VERSION 5.8 ;
BUSBITCHARS "[]" ;
DIVIDERCHAR "/" ;
UNITS
    DATABASE MICRONS 1000 ;
END UNITS

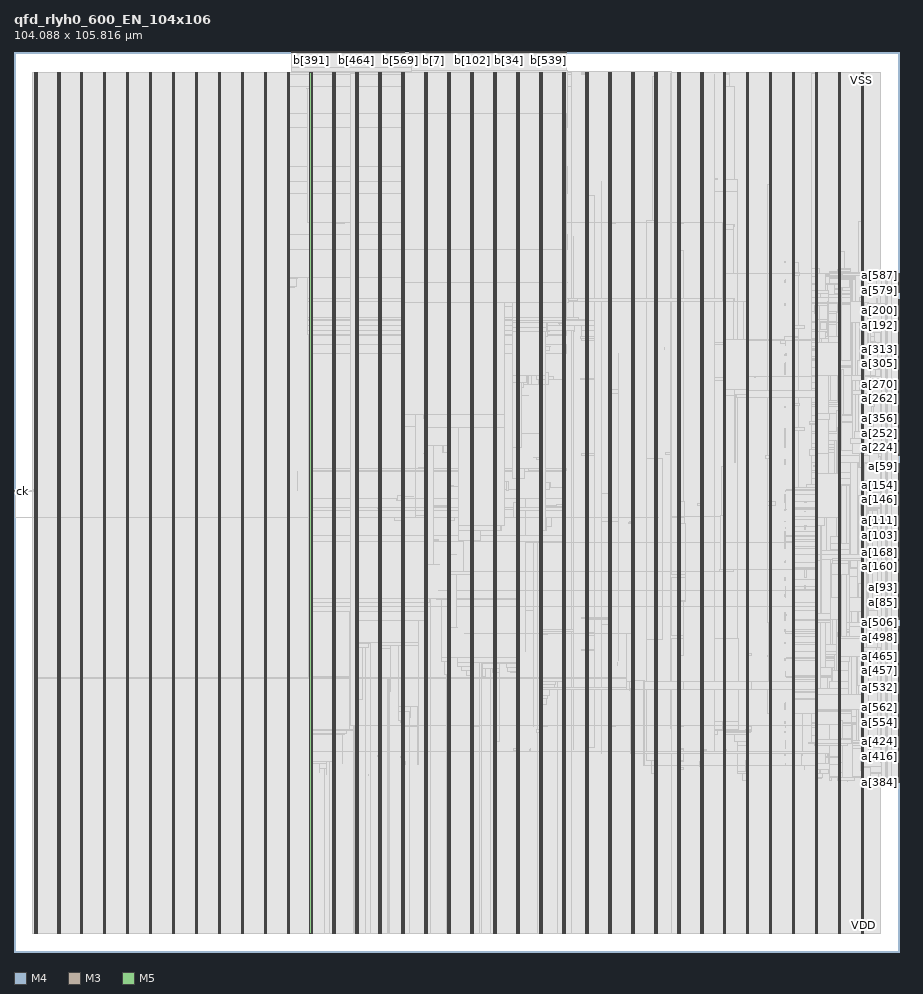
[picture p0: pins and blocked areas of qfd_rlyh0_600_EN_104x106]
MACRO qfd_rlyh0_600_EN_104x106
  FOREIGN qfd_rlyh0_600_EN_104x106 0 0 ;
  CLASS BLOCK ;
  SIZE 104.088 BY 105.816 ;
  PIN a[0]
    DIRECTION INPUT ;
    USE SIGNAL ;
    PORT
      LAYER M4 ;
        RECT  104.004 42.192 104.088 42.216 ;
    END
  END a[0]
  PIN a[100]
    DIRECTION INPUT ;
    USE SIGNAL ;
    PORT
      LAYER M4 ;
        RECT  104.004 48.72 104.088 48.744 ;
    END
  END a[100]
  PIN a[101]
    DIRECTION INPUT ;
    USE SIGNAL ;
    PORT
      LAYER M4 ;
        RECT  104.004 48.816 104.088 48.84 ;
    END
  END a[101]
  PIN a[102]
    DIRECTION INPUT ;
    USE SIGNAL ;
    PORT
      LAYER M4 ;
        RECT  104.004 48.912 104.088 48.936 ;
    END
  END a[102]
  PIN a[103]
    DIRECTION INPUT ;
    USE SIGNAL ;
    PORT
      LAYER M4 ;
        RECT  104.004 49.008 104.088 49.032 ;
    END
  END a[103]
  PIN a[104]
    DIRECTION INPUT ;
    USE SIGNAL ;
    PORT
      LAYER M4 ;
        RECT  104.004 49.104 104.088 49.128 ;
    END
  END a[104]
  PIN a[105]
    DIRECTION INPUT ;
    USE SIGNAL ;
    PORT
      LAYER M4 ;
        RECT  104.004 49.2 104.088 49.224 ;
    END
  END a[105]
  PIN a[106]
    DIRECTION INPUT ;
    USE SIGNAL ;
    PORT
      LAYER M4 ;
        RECT  104.004 49.296 104.088 49.32 ;
    END
  END a[106]
  PIN a[107]
    DIRECTION INPUT ;
    USE SIGNAL ;
    PORT
      LAYER M4 ;
        RECT  104.004 49.392 104.088 49.416 ;
    END
  END a[107]
  PIN a[108]
    DIRECTION INPUT ;
    USE SIGNAL ;
    PORT
      LAYER M4 ;
        RECT  104.004 49.488 104.088 49.512 ;
    END
  END a[108]
  PIN a[109]
    DIRECTION INPUT ;
    USE SIGNAL ;
    PORT
      LAYER M4 ;
        RECT  104.004 49.584 104.088 49.608 ;
    END
  END a[109]
  PIN a[10]
    DIRECTION INPUT ;
    USE SIGNAL ;
    PORT
      LAYER M4 ;
        RECT  104.004 43.152 104.088 43.176 ;
    END
  END a[10]
  PIN a[110]
    DIRECTION INPUT ;
    USE SIGNAL ;
    PORT
      LAYER M4 ;
        RECT  104.004 49.68 104.088 49.704 ;
    END
  END a[110]
  PIN a[111]
    DIRECTION INPUT ;
    USE SIGNAL ;
    PORT
      LAYER M4 ;
        RECT  104.004 49.776 104.088 49.8 ;
    END
  END a[111]
  PIN a[112]
    DIRECTION INPUT ;
    USE SIGNAL ;
    PORT
      LAYER M4 ;
        RECT  104.004 49.872 104.088 49.896 ;
    END
  END a[112]
  PIN a[113]
    DIRECTION INPUT ;
    USE SIGNAL ;
    PORT
      LAYER M4 ;
        RECT  104.004 49.968 104.088 49.992 ;
    END
  END a[113]
  PIN a[114]
    DIRECTION INPUT ;
    USE SIGNAL ;
    PORT
      LAYER M4 ;
        RECT  104.004 50.064 104.088 50.088 ;
    END
  END a[114]
  PIN a[115]
    DIRECTION INPUT ;
    USE SIGNAL ;
    PORT
      LAYER M4 ;
        RECT  104.004 50.16 104.088 50.184 ;
    END
  END a[115]
  PIN a[116]
    DIRECTION INPUT ;
    USE SIGNAL ;
    PORT
      LAYER M4 ;
        RECT  104.004 50.256 104.088 50.28 ;
    END
  END a[116]
  PIN a[117]
    DIRECTION INPUT ;
    USE SIGNAL ;
    PORT
      LAYER M4 ;
        RECT  104.004 50.352 104.088 50.376 ;
    END
  END a[117]
  PIN a[118]
    DIRECTION INPUT ;
    USE SIGNAL ;
    PORT
      LAYER M4 ;
        RECT  104.004 50.448 104.088 50.472 ;
    END
  END a[118]
  PIN a[119]
    DIRECTION INPUT ;
    USE SIGNAL ;
    PORT
      LAYER M4 ;
        RECT  104.004 50.544 104.088 50.568 ;
    END
  END a[119]
  PIN a[11]
    DIRECTION INPUT ;
    USE SIGNAL ;
    PORT
      LAYER M4 ;
        RECT  104.004 43.248 104.088 43.272 ;
    END
  END a[11]
  PIN a[120]
    DIRECTION INPUT ;
    USE SIGNAL ;
    PORT
      LAYER M4 ;
        RECT  104.004 50.64 104.088 50.664 ;
    END
  END a[120]
  PIN a[121]
    DIRECTION INPUT ;
    USE SIGNAL ;
    PORT
      LAYER M4 ;
        RECT  104.004 50.736 104.088 50.76 ;
    END
  END a[121]
  PIN a[122]
    DIRECTION INPUT ;
    USE SIGNAL ;
    PORT
      LAYER M4 ;
        RECT  104.004 50.832 104.088 50.856 ;
    END
  END a[122]
  PIN a[123]
    DIRECTION INPUT ;
    USE SIGNAL ;
    PORT
      LAYER M4 ;
        RECT  104.004 50.928 104.088 50.952 ;
    END
  END a[123]
  PIN a[124]
    DIRECTION INPUT ;
    USE SIGNAL ;
    PORT
      LAYER M4 ;
        RECT  104.004 51.024 104.088 51.048 ;
    END
  END a[124]
  PIN a[125]
    DIRECTION INPUT ;
    USE SIGNAL ;
    PORT
      LAYER M4 ;
        RECT  104.004 51.12 104.088 51.144 ;
    END
  END a[125]
  PIN a[126]
    DIRECTION INPUT ;
    USE SIGNAL ;
    PORT
      LAYER M4 ;
        RECT  104.004 51.216 104.088 51.24 ;
    END
  END a[126]
  PIN a[127]
    DIRECTION INPUT ;
    USE SIGNAL ;
    PORT
      LAYER M4 ;
        RECT  104.004 51.312 104.088 51.336 ;
    END
  END a[127]
  PIN a[128]
    DIRECTION INPUT ;
    USE SIGNAL ;
    PORT
      LAYER M4 ;
        RECT  104.004 51.408 104.088 51.432 ;
    END
  END a[128]
  PIN a[129]
    DIRECTION INPUT ;
    USE SIGNAL ;
    PORT
      LAYER M4 ;
        RECT  104.004 51.504 104.088 51.528 ;
    END
  END a[129]
  PIN a[12]
    DIRECTION INPUT ;
    USE SIGNAL ;
    PORT
      LAYER M4 ;
        RECT  104.004 43.344 104.088 43.368 ;
    END
  END a[12]
  PIN a[130]
    DIRECTION INPUT ;
    USE SIGNAL ;
    PORT
      LAYER M4 ;
        RECT  104.004 51.6 104.088 51.624 ;
    END
  END a[130]
  PIN a[131]
    DIRECTION INPUT ;
    USE SIGNAL ;
    PORT
      LAYER M4 ;
        RECT  104.004 51.696 104.088 51.72 ;
    END
  END a[131]
  PIN a[132]
    DIRECTION INPUT ;
    USE SIGNAL ;
    PORT
      LAYER M4 ;
        RECT  104.004 51.792 104.088 51.816 ;
    END
  END a[132]
  PIN a[133]
    DIRECTION INPUT ;
    USE SIGNAL ;
    PORT
      LAYER M4 ;
        RECT  104.004 51.888 104.088 51.912 ;
    END
  END a[133]
  PIN a[134]
    DIRECTION INPUT ;
    USE SIGNAL ;
    PORT
      LAYER M4 ;
        RECT  104.004 51.984 104.088 52.008 ;
    END
  END a[134]
  PIN a[135]
    DIRECTION INPUT ;
    USE SIGNAL ;
    PORT
      LAYER M4 ;
        RECT  104.004 52.08 104.088 52.104 ;
    END
  END a[135]
  PIN a[136]
    DIRECTION INPUT ;
    USE SIGNAL ;
    PORT
      LAYER M4 ;
        RECT  104.004 52.176 104.088 52.2 ;
    END
  END a[136]
  PIN a[137]
    DIRECTION INPUT ;
    USE SIGNAL ;
    PORT
      LAYER M4 ;
        RECT  104.004 52.272 104.088 52.296 ;
    END
  END a[137]
  PIN a[138]
    DIRECTION INPUT ;
    USE SIGNAL ;
    PORT
      LAYER M4 ;
        RECT  104.004 52.368 104.088 52.392 ;
    END
  END a[138]
  PIN a[139]
    DIRECTION INPUT ;
    USE SIGNAL ;
    PORT
      LAYER M4 ;
        RECT  104.004 52.464 104.088 52.488 ;
    END
  END a[139]
  PIN a[13]
    DIRECTION INPUT ;
    USE SIGNAL ;
    PORT
      LAYER M4 ;
        RECT  104.004 43.44 104.088 43.464 ;
    END
  END a[13]
  PIN a[140]
    DIRECTION INPUT ;
    USE SIGNAL ;
    PORT
      LAYER M4 ;
        RECT  104.004 52.56 104.088 52.584 ;
    END
  END a[140]
  PIN a[141]
    DIRECTION INPUT ;
    USE SIGNAL ;
    PORT
      LAYER M4 ;
        RECT  104.004 52.656 104.088 52.68 ;
    END
  END a[141]
  PIN a[142]
    DIRECTION INPUT ;
    USE SIGNAL ;
    PORT
      LAYER M4 ;
        RECT  104.004 52.752 104.088 52.776 ;
    END
  END a[142]
  PIN a[143]
    DIRECTION INPUT ;
    USE SIGNAL ;
    PORT
      LAYER M4 ;
        RECT  104.004 52.848 104.088 52.872 ;
    END
  END a[143]
  PIN a[144]
    DIRECTION INPUT ;
    USE SIGNAL ;
    PORT
      LAYER M4 ;
        RECT  104.004 52.944 104.088 52.968 ;
    END
  END a[144]
  PIN a[145]
    DIRECTION INPUT ;
    USE SIGNAL ;
    PORT
      LAYER M4 ;
        RECT  104.004 53.04 104.088 53.064 ;
    END
  END a[145]
  PIN a[146]
    DIRECTION INPUT ;
    USE SIGNAL ;
    PORT
      LAYER M4 ;
        RECT  104.004 53.136 104.088 53.16 ;
    END
  END a[146]
  PIN a[147]
    DIRECTION INPUT ;
    USE SIGNAL ;
    PORT
      LAYER M4 ;
        RECT  104.004 53.232 104.088 53.256 ;
    END
  END a[147]
  PIN a[148]
    DIRECTION INPUT ;
    USE SIGNAL ;
    PORT
      LAYER M4 ;
        RECT  104.004 53.328 104.088 53.352 ;
    END
  END a[148]
  PIN a[149]
    DIRECTION INPUT ;
    USE SIGNAL ;
    PORT
      LAYER M4 ;
        RECT  104.004 53.424 104.088 53.448 ;
    END
  END a[149]
  PIN a[14]
    DIRECTION INPUT ;
    USE SIGNAL ;
    PORT
      LAYER M4 ;
        RECT  104.004 43.536 104.088 43.56 ;
    END
  END a[14]
  PIN a[150]
    DIRECTION INPUT ;
    USE SIGNAL ;
    PORT
      LAYER M4 ;
        RECT  104.004 53.52 104.088 53.544 ;
    END
  END a[150]
  PIN a[151]
    DIRECTION INPUT ;
    USE SIGNAL ;
    PORT
      LAYER M4 ;
        RECT  104.004 53.616 104.088 53.64 ;
    END
  END a[151]
  PIN a[152]
    DIRECTION INPUT ;
    USE SIGNAL ;
    PORT
      LAYER M4 ;
        RECT  104.004 53.712 104.088 53.736 ;
    END
  END a[152]
  PIN a[153]
    DIRECTION INPUT ;
    USE SIGNAL ;
    PORT
      LAYER M4 ;
        RECT  104.004 53.808 104.088 53.832 ;
    END
  END a[153]
  PIN a[154]
    DIRECTION INPUT ;
    USE SIGNAL ;
    PORT
      LAYER M4 ;
        RECT  104.004 53.904 104.088 53.928 ;
    END
  END a[154]
  PIN a[155]
    DIRECTION INPUT ;
    USE SIGNAL ;
    PORT
      LAYER M4 ;
        RECT  104.004 54 104.088 54.024 ;
    END
  END a[155]
  PIN a[156]
    DIRECTION INPUT ;
    USE SIGNAL ;
    PORT
      LAYER M4 ;
        RECT  104.004 54.096 104.088 54.12 ;
    END
  END a[156]
  PIN a[157]
    DIRECTION INPUT ;
    USE SIGNAL ;
    PORT
      LAYER M4 ;
        RECT  104.004 54.192 104.088 54.216 ;
    END
  END a[157]
  PIN a[158]
    DIRECTION INPUT ;
    USE SIGNAL ;
    PORT
      LAYER M4 ;
        RECT  104.004 54.288 104.088 54.312 ;
    END
  END a[158]
  PIN a[159]
    DIRECTION INPUT ;
    USE SIGNAL ;
    PORT
      LAYER M4 ;
        RECT  104.004 54.384 104.088 54.408 ;
    END
  END a[159]
  PIN a[15]
    DIRECTION INPUT ;
    USE SIGNAL ;
    PORT
      LAYER M4 ;
        RECT  104.004 43.632 104.088 43.656 ;
    END
  END a[15]
  PIN a[160]
    DIRECTION INPUT ;
    USE SIGNAL ;
    PORT
      LAYER M4 ;
        RECT  104.004 45.264 104.088 45.288 ;
    END
  END a[160]
  PIN a[161]
    DIRECTION INPUT ;
    USE SIGNAL ;
    PORT
      LAYER M4 ;
        RECT  104.004 45.36 104.088 45.384 ;
    END
  END a[161]
  PIN a[162]
    DIRECTION INPUT ;
    USE SIGNAL ;
    PORT
      LAYER M4 ;
        RECT  104.004 45.456 104.088 45.48 ;
    END
  END a[162]
  PIN a[163]
    DIRECTION INPUT ;
    USE SIGNAL ;
    PORT
      LAYER M4 ;
        RECT  104.004 45.552 104.088 45.576 ;
    END
  END a[163]
  PIN a[164]
    DIRECTION INPUT ;
    USE SIGNAL ;
    PORT
      LAYER M4 ;
        RECT  104.004 45.648 104.088 45.672 ;
    END
  END a[164]
  PIN a[165]
    DIRECTION INPUT ;
    USE SIGNAL ;
    PORT
      LAYER M4 ;
        RECT  104.004 45.744 104.088 45.768 ;
    END
  END a[165]
  PIN a[166]
    DIRECTION INPUT ;
    USE SIGNAL ;
    PORT
      LAYER M4 ;
        RECT  104.004 45.84 104.088 45.864 ;
    END
  END a[166]
  PIN a[167]
    DIRECTION INPUT ;
    USE SIGNAL ;
    PORT
      LAYER M4 ;
        RECT  104.004 45.936 104.088 45.96 ;
    END
  END a[167]
  PIN a[168]
    DIRECTION INPUT ;
    USE SIGNAL ;
    PORT
      LAYER M4 ;
        RECT  104.004 46.032 104.088 46.056 ;
    END
  END a[168]
  PIN a[169]
    DIRECTION INPUT ;
    USE SIGNAL ;
    PORT
      LAYER M4 ;
        RECT  104.004 46.128 104.088 46.152 ;
    END
  END a[169]
  PIN a[16]
    DIRECTION INPUT ;
    USE SIGNAL ;
    PORT
      LAYER M4 ;
        RECT  104.004 43.728 104.088 43.752 ;
    END
  END a[16]
  PIN a[170]
    DIRECTION INPUT ;
    USE SIGNAL ;
    PORT
      LAYER M4 ;
        RECT  104.004 46.224 104.088 46.248 ;
    END
  END a[170]
  PIN a[171]
    DIRECTION INPUT ;
    USE SIGNAL ;
    PORT
      LAYER M4 ;
        RECT  104.004 46.32 104.088 46.344 ;
    END
  END a[171]
  PIN a[172]
    DIRECTION INPUT ;
    USE SIGNAL ;
    PORT
      LAYER M4 ;
        RECT  104.004 46.416 104.088 46.44 ;
    END
  END a[172]
  PIN a[173]
    DIRECTION INPUT ;
    USE SIGNAL ;
    PORT
      LAYER M4 ;
        RECT  104.004 46.512 104.088 46.536 ;
    END
  END a[173]
  PIN a[174]
    DIRECTION INPUT ;
    USE SIGNAL ;
    PORT
      LAYER M4 ;
        RECT  104.004 46.608 104.088 46.632 ;
    END
  END a[174]
  PIN a[175]
    DIRECTION INPUT ;
    USE SIGNAL ;
    PORT
      LAYER M4 ;
        RECT  104.004 46.704 104.088 46.728 ;
    END
  END a[175]
  PIN a[176]
    DIRECTION INPUT ;
    USE SIGNAL ;
    PORT
      LAYER M4 ;
        RECT  104.004 46.8 104.088 46.824 ;
    END
  END a[176]
  PIN a[177]
    DIRECTION INPUT ;
    USE SIGNAL ;
    PORT
      LAYER M4 ;
        RECT  104.004 46.896 104.088 46.92 ;
    END
  END a[177]
  PIN a[178]
    DIRECTION INPUT ;
    USE SIGNAL ;
    PORT
      LAYER M4 ;
        RECT  104.004 46.992 104.088 47.016 ;
    END
  END a[178]
  PIN a[179]
    DIRECTION INPUT ;
    USE SIGNAL ;
    PORT
      LAYER M4 ;
        RECT  104.004 47.088 104.088 47.112 ;
    END
  END a[179]
  PIN a[17]
    DIRECTION INPUT ;
    USE SIGNAL ;
    PORT
      LAYER M4 ;
        RECT  104.004 43.824 104.088 43.848 ;
    END
  END a[17]
  PIN a[180]
    DIRECTION INPUT ;
    USE SIGNAL ;
    PORT
      LAYER M4 ;
        RECT  104.004 47.184 104.088 47.208 ;
    END
  END a[180]
  PIN a[181]
    DIRECTION INPUT ;
    USE SIGNAL ;
    PORT
      LAYER M4 ;
        RECT  104.004 47.28 104.088 47.304 ;
    END
  END a[181]
  PIN a[182]
    DIRECTION INPUT ;
    USE SIGNAL ;
    PORT
      LAYER M4 ;
        RECT  104.004 47.376 104.088 47.4 ;
    END
  END a[182]
  PIN a[183]
    DIRECTION INPUT ;
    USE SIGNAL ;
    PORT
      LAYER M4 ;
        RECT  104.004 47.472 104.088 47.496 ;
    END
  END a[183]
  PIN a[184]
    DIRECTION INPUT ;
    USE SIGNAL ;
    PORT
      LAYER M4 ;
        RECT  104.004 47.568 104.088 47.592 ;
    END
  END a[184]
  PIN a[185]
    DIRECTION INPUT ;
    USE SIGNAL ;
    PORT
      LAYER M4 ;
        RECT  104.004 47.664 104.088 47.688 ;
    END
  END a[185]
  PIN a[186]
    DIRECTION INPUT ;
    USE SIGNAL ;
    PORT
      LAYER M4 ;
        RECT  104.004 47.76 104.088 47.784 ;
    END
  END a[186]
  PIN a[187]
    DIRECTION INPUT ;
    USE SIGNAL ;
    PORT
      LAYER M4 ;
        RECT  104.004 47.856 104.088 47.88 ;
    END
  END a[187]
  PIN a[188]
    DIRECTION INPUT ;
    USE SIGNAL ;
    PORT
      LAYER M4 ;
        RECT  104.004 47.952 104.088 47.976 ;
    END
  END a[188]
  PIN a[189]
    DIRECTION INPUT ;
    USE SIGNAL ;
    PORT
      LAYER M4 ;
        RECT  104.004 48.048 104.088 48.072 ;
    END
  END a[189]
  PIN a[18]
    DIRECTION INPUT ;
    USE SIGNAL ;
    PORT
      LAYER M4 ;
        RECT  104.004 43.92 104.088 43.944 ;
    END
  END a[18]
  PIN a[190]
    DIRECTION INPUT ;
    USE SIGNAL ;
    PORT
      LAYER M4 ;
        RECT  104.004 48.144 104.088 48.168 ;
    END
  END a[190]
  PIN a[191]
    DIRECTION INPUT ;
    USE SIGNAL ;
    PORT
      LAYER M4 ;
        RECT  104.004 48.24 104.088 48.264 ;
    END
  END a[191]
  PIN a[192]
    DIRECTION INPUT ;
    USE SIGNAL ;
    PORT
      LAYER M4 ;
        RECT  104.004 73.68 104.088 73.704 ;
    END
  END a[192]
  PIN a[193]
    DIRECTION INPUT ;
    USE SIGNAL ;
    PORT
      LAYER M4 ;
        RECT  104.004 73.776 104.088 73.8 ;
    END
  END a[193]
  PIN a[194]
    DIRECTION INPUT ;
    USE SIGNAL ;
    PORT
      LAYER M4 ;
        RECT  104.004 73.872 104.088 73.896 ;
    END
  END a[194]
  PIN a[195]
    DIRECTION INPUT ;
    USE SIGNAL ;
    PORT
      LAYER M4 ;
        RECT  104.004 73.968 104.088 73.992 ;
    END
  END a[195]
  PIN a[196]
    DIRECTION INPUT ;
    USE SIGNAL ;
    PORT
      LAYER M4 ;
        RECT  104.004 74.064 104.088 74.088 ;
    END
  END a[196]
  PIN a[197]
    DIRECTION INPUT ;
    USE SIGNAL ;
    PORT
      LAYER M4 ;
        RECT  104.004 74.16 104.088 74.184 ;
    END
  END a[197]
  PIN a[198]
    DIRECTION INPUT ;
    USE SIGNAL ;
    PORT
      LAYER M4 ;
        RECT  104.004 74.256 104.088 74.28 ;
    END
  END a[198]
  PIN a[199]
    DIRECTION INPUT ;
    USE SIGNAL ;
    PORT
      LAYER M4 ;
        RECT  104.004 74.352 104.088 74.376 ;
    END
  END a[199]
  PIN a[19]
    DIRECTION INPUT ;
    USE SIGNAL ;
    PORT
      LAYER M4 ;
        RECT  104.004 44.016 104.088 44.04 ;
    END
  END a[19]
  PIN a[1]
    DIRECTION INPUT ;
    USE SIGNAL ;
    PORT
      LAYER M4 ;
        RECT  104.004 42.288 104.088 42.312 ;
    END
  END a[1]
  PIN a[200]
    DIRECTION INPUT ;
    USE SIGNAL ;
    PORT
      LAYER M4 ;
        RECT  104.004 74.448 104.088 74.472 ;
    END
  END a[200]
  PIN a[201]
    DIRECTION INPUT ;
    USE SIGNAL ;
    PORT
      LAYER M4 ;
        RECT  104.004 74.544 104.088 74.568 ;
    END
  END a[201]
  PIN a[202]
    DIRECTION INPUT ;
    USE SIGNAL ;
    PORT
      LAYER M4 ;
        RECT  104.004 74.64 104.088 74.664 ;
    END
  END a[202]
  PIN a[203]
    DIRECTION INPUT ;
    USE SIGNAL ;
    PORT
      LAYER M4 ;
        RECT  104.004 74.736 104.088 74.76 ;
    END
  END a[203]
  PIN a[204]
    DIRECTION INPUT ;
    USE SIGNAL ;
    PORT
      LAYER M4 ;
        RECT  104.004 74.832 104.088 74.856 ;
    END
  END a[204]
  PIN a[205]
    DIRECTION INPUT ;
    USE SIGNAL ;
    PORT
      LAYER M4 ;
        RECT  104.004 74.928 104.088 74.952 ;
    END
  END a[205]
  PIN a[206]
    DIRECTION INPUT ;
    USE SIGNAL ;
    PORT
      LAYER M4 ;
        RECT  104.004 75.024 104.088 75.048 ;
    END
  END a[206]
  PIN a[207]
    DIRECTION INPUT ;
    USE SIGNAL ;
    PORT
      LAYER M4 ;
        RECT  104.004 75.12 104.088 75.144 ;
    END
  END a[207]
  PIN a[208]
    DIRECTION INPUT ;
    USE SIGNAL ;
    PORT
      LAYER M4 ;
        RECT  104.004 75.216 104.088 75.24 ;
    END
  END a[208]
  PIN a[209]
    DIRECTION INPUT ;
    USE SIGNAL ;
    PORT
      LAYER M4 ;
        RECT  104.004 75.312 104.088 75.336 ;
    END
  END a[209]
  PIN a[20]
    DIRECTION INPUT ;
    USE SIGNAL ;
    PORT
      LAYER M4 ;
        RECT  104.004 44.112 104.088 44.136 ;
    END
  END a[20]
  PIN a[210]
    DIRECTION INPUT ;
    USE SIGNAL ;
    PORT
      LAYER M4 ;
        RECT  104.004 75.408 104.088 75.432 ;
    END
  END a[210]
  PIN a[211]
    DIRECTION INPUT ;
    USE SIGNAL ;
    PORT
      LAYER M4 ;
        RECT  104.004 75.504 104.088 75.528 ;
    END
  END a[211]
  PIN a[212]
    DIRECTION INPUT ;
    USE SIGNAL ;
    PORT
      LAYER M4 ;
        RECT  104.004 75.6 104.088 75.624 ;
    END
  END a[212]
  PIN a[213]
    DIRECTION INPUT ;
    USE SIGNAL ;
    PORT
      LAYER M4 ;
        RECT  104.004 75.696 104.088 75.72 ;
    END
  END a[213]
  PIN a[214]
    DIRECTION INPUT ;
    USE SIGNAL ;
    PORT
      LAYER M4 ;
        RECT  104.004 75.792 104.088 75.816 ;
    END
  END a[214]
  PIN a[215]
    DIRECTION INPUT ;
    USE SIGNAL ;
    PORT
      LAYER M4 ;
        RECT  104.004 75.888 104.088 75.912 ;
    END
  END a[215]
  PIN a[216]
    DIRECTION INPUT ;
    USE SIGNAL ;
    PORT
      LAYER M4 ;
        RECT  104.004 75.984 104.088 76.008 ;
    END
  END a[216]
  PIN a[217]
    DIRECTION INPUT ;
    USE SIGNAL ;
    PORT
      LAYER M4 ;
        RECT  104.004 76.08 104.088 76.104 ;
    END
  END a[217]
  PIN a[218]
    DIRECTION INPUT ;
    USE SIGNAL ;
    PORT
      LAYER M4 ;
        RECT  104.004 76.176 104.088 76.2 ;
    END
  END a[218]
  PIN a[219]
    DIRECTION INPUT ;
    USE SIGNAL ;
    PORT
      LAYER M4 ;
        RECT  104.004 76.272 104.088 76.296 ;
    END
  END a[219]
  PIN a[21]
    DIRECTION INPUT ;
    USE SIGNAL ;
    PORT
      LAYER M4 ;
        RECT  104.004 44.208 104.088 44.232 ;
    END
  END a[21]
  PIN a[220]
    DIRECTION INPUT ;
    USE SIGNAL ;
    PORT
      LAYER M4 ;
        RECT  104.004 76.368 104.088 76.392 ;
    END
  END a[220]
  PIN a[221]
    DIRECTION INPUT ;
    USE SIGNAL ;
    PORT
      LAYER M4 ;
        RECT  104.004 76.464 104.088 76.488 ;
    END
  END a[221]
  PIN a[222]
    DIRECTION INPUT ;
    USE SIGNAL ;
    PORT
      LAYER M4 ;
        RECT  104.004 76.56 104.088 76.584 ;
    END
  END a[222]
  PIN a[223]
    DIRECTION INPUT ;
    USE SIGNAL ;
    PORT
      LAYER M4 ;
        RECT  104.004 76.656 104.088 76.68 ;
    END
  END a[223]
  PIN a[224]
    DIRECTION INPUT ;
    USE SIGNAL ;
    PORT
      LAYER M4 ;
        RECT  104.004 58.32 104.088 58.344 ;
    END
  END a[224]
  PIN a[225]
    DIRECTION INPUT ;
    USE SIGNAL ;
    PORT
      LAYER M4 ;
        RECT  104.004 58.416 104.088 58.44 ;
    END
  END a[225]
  PIN a[226]
    DIRECTION INPUT ;
    USE SIGNAL ;
    PORT
      LAYER M4 ;
        RECT  104.004 58.512 104.088 58.536 ;
    END
  END a[226]
  PIN a[227]
    DIRECTION INPUT ;
    USE SIGNAL ;
    PORT
      LAYER M4 ;
        RECT  104.004 58.608 104.088 58.632 ;
    END
  END a[227]
  PIN a[228]
    DIRECTION INPUT ;
    USE SIGNAL ;
    PORT
      LAYER M4 ;
        RECT  104.004 58.704 104.088 58.728 ;
    END
  END a[228]
  PIN a[229]
    DIRECTION INPUT ;
    USE SIGNAL ;
    PORT
      LAYER M4 ;
        RECT  104.004 58.8 104.088 58.824 ;
    END
  END a[229]
  PIN a[22]
    DIRECTION INPUT ;
    USE SIGNAL ;
    PORT
      LAYER M4 ;
        RECT  104.004 44.304 104.088 44.328 ;
    END
  END a[22]
  PIN a[230]
    DIRECTION INPUT ;
    USE SIGNAL ;
    PORT
      LAYER M4 ;
        RECT  104.004 58.896 104.088 58.92 ;
    END
  END a[230]
  PIN a[231]
    DIRECTION INPUT ;
    USE SIGNAL ;
    PORT
      LAYER M4 ;
        RECT  104.004 58.992 104.088 59.016 ;
    END
  END a[231]
  PIN a[232]
    DIRECTION INPUT ;
    USE SIGNAL ;
    PORT
      LAYER M4 ;
        RECT  104.004 59.088 104.088 59.112 ;
    END
  END a[232]
  PIN a[233]
    DIRECTION INPUT ;
    USE SIGNAL ;
    PORT
      LAYER M4 ;
        RECT  104.004 59.184 104.088 59.208 ;
    END
  END a[233]
  PIN a[234]
    DIRECTION INPUT ;
    USE SIGNAL ;
    PORT
      LAYER M4 ;
        RECT  104.004 59.28 104.088 59.304 ;
    END
  END a[234]
  PIN a[235]
    DIRECTION INPUT ;
    USE SIGNAL ;
    PORT
      LAYER M4 ;
        RECT  104.004 59.376 104.088 59.4 ;
    END
  END a[235]
  PIN a[236]
    DIRECTION INPUT ;
    USE SIGNAL ;
    PORT
      LAYER M4 ;
        RECT  104.004 59.472 104.088 59.496 ;
    END
  END a[236]
  PIN a[237]
    DIRECTION INPUT ;
    USE SIGNAL ;
    PORT
      LAYER M4 ;
        RECT  104.004 59.568 104.088 59.592 ;
    END
  END a[237]
  PIN a[238]
    DIRECTION INPUT ;
    USE SIGNAL ;
    PORT
      LAYER M4 ;
        RECT  104.004 59.664 104.088 59.688 ;
    END
  END a[238]
  PIN a[239]
    DIRECTION INPUT ;
    USE SIGNAL ;
    PORT
      LAYER M4 ;
        RECT  104.004 59.76 104.088 59.784 ;
    END
  END a[239]
  PIN a[23]
    DIRECTION INPUT ;
    USE SIGNAL ;
    PORT
      LAYER M4 ;
        RECT  104.004 44.4 104.088 44.424 ;
    END
  END a[23]
  PIN a[240]
    DIRECTION INPUT ;
    USE SIGNAL ;
    PORT
      LAYER M4 ;
        RECT  104.004 59.856 104.088 59.88 ;
    END
  END a[240]
  PIN a[241]
    DIRECTION INPUT ;
    USE SIGNAL ;
    PORT
      LAYER M4 ;
        RECT  104.004 59.952 104.088 59.976 ;
    END
  END a[241]
  PIN a[242]
    DIRECTION INPUT ;
    USE SIGNAL ;
    PORT
      LAYER M4 ;
        RECT  104.004 60.048 104.088 60.072 ;
    END
  END a[242]
  PIN a[243]
    DIRECTION INPUT ;
    USE SIGNAL ;
    PORT
      LAYER M4 ;
        RECT  104.004 60.144 104.088 60.168 ;
    END
  END a[243]
  PIN a[244]
    DIRECTION INPUT ;
    USE SIGNAL ;
    PORT
      LAYER M4 ;
        RECT  104.004 60.24 104.088 60.264 ;
    END
  END a[244]
  PIN a[245]
    DIRECTION INPUT ;
    USE SIGNAL ;
    PORT
      LAYER M4 ;
        RECT  104.004 60.336 104.088 60.36 ;
    END
  END a[245]
  PIN a[246]
    DIRECTION INPUT ;
    USE SIGNAL ;
    PORT
      LAYER M4 ;
        RECT  104.004 60.432 104.088 60.456 ;
    END
  END a[246]
  PIN a[247]
    DIRECTION INPUT ;
    USE SIGNAL ;
    PORT
      LAYER M4 ;
        RECT  104.004 60.528 104.088 60.552 ;
    END
  END a[247]
  PIN a[248]
    DIRECTION INPUT ;
    USE SIGNAL ;
    PORT
      LAYER M4 ;
        RECT  104.004 60.624 104.088 60.648 ;
    END
  END a[248]
  PIN a[249]
    DIRECTION INPUT ;
    USE SIGNAL ;
    PORT
      LAYER M4 ;
        RECT  104.004 60.72 104.088 60.744 ;
    END
  END a[249]
  PIN a[24]
    DIRECTION INPUT ;
    USE SIGNAL ;
    PORT
      LAYER M4 ;
        RECT  104.004 44.496 104.088 44.52 ;
    END
  END a[24]
  PIN a[250]
    DIRECTION INPUT ;
    USE SIGNAL ;
    PORT
      LAYER M4 ;
        RECT  104.004 60.816 104.088 60.84 ;
    END
  END a[250]
  PIN a[251]
    DIRECTION INPUT ;
    USE SIGNAL ;
    PORT
      LAYER M4 ;
        RECT  104.004 60.912 104.088 60.936 ;
    END
  END a[251]
  PIN a[252]
    DIRECTION INPUT ;
    USE SIGNAL ;
    PORT
      LAYER M4 ;
        RECT  104.004 61.008 104.088 61.032 ;
    END
  END a[252]
  PIN a[253]
    DIRECTION INPUT ;
    USE SIGNAL ;
    PORT
      LAYER M4 ;
        RECT  104.004 61.104 104.088 61.128 ;
    END
  END a[253]
  PIN a[254]
    DIRECTION INPUT ;
    USE SIGNAL ;
    PORT
      LAYER M4 ;
        RECT  104.004 61.2 104.088 61.224 ;
    END
  END a[254]
  PIN a[255]
    DIRECTION INPUT ;
    USE SIGNAL ;
    PORT
      LAYER M4 ;
        RECT  104.004 61.296 104.088 61.32 ;
    END
  END a[255]
  PIN a[256]
    DIRECTION INPUT ;
    USE SIGNAL ;
    PORT
      LAYER M4 ;
        RECT  104.004 64.464 104.088 64.488 ;
    END
  END a[256]
  PIN a[257]
    DIRECTION INPUT ;
    USE SIGNAL ;
    PORT
      LAYER M4 ;
        RECT  104.004 64.56 104.088 64.584 ;
    END
  END a[257]
  PIN a[258]
    DIRECTION INPUT ;
    USE SIGNAL ;
    PORT
      LAYER M4 ;
        RECT  104.004 64.656 104.088 64.68 ;
    END
  END a[258]
  PIN a[259]
    DIRECTION INPUT ;
    USE SIGNAL ;
    PORT
      LAYER M4 ;
        RECT  104.004 64.752 104.088 64.776 ;
    END
  END a[259]
  PIN a[25]
    DIRECTION INPUT ;
    USE SIGNAL ;
    PORT
      LAYER M4 ;
        RECT  104.004 44.592 104.088 44.616 ;
    END
  END a[25]
  PIN a[260]
    DIRECTION INPUT ;
    USE SIGNAL ;
    PORT
      LAYER M4 ;
        RECT  104.004 64.848 104.088 64.872 ;
    END
  END a[260]
  PIN a[261]
    DIRECTION INPUT ;
    USE SIGNAL ;
    PORT
      LAYER M4 ;
        RECT  104.004 64.944 104.088 64.968 ;
    END
  END a[261]
  PIN a[262]
    DIRECTION INPUT ;
    USE SIGNAL ;
    PORT
      LAYER M4 ;
        RECT  104.004 65.04 104.088 65.064 ;
    END
  END a[262]
  PIN a[263]
    DIRECTION INPUT ;
    USE SIGNAL ;
    PORT
      LAYER M4 ;
        RECT  104.004 65.136 104.088 65.16 ;
    END
  END a[263]
  PIN a[264]
    DIRECTION INPUT ;
    USE SIGNAL ;
    PORT
      LAYER M4 ;
        RECT  104.004 65.232 104.088 65.256 ;
    END
  END a[264]
  PIN a[265]
    DIRECTION INPUT ;
    USE SIGNAL ;
    PORT
      LAYER M4 ;
        RECT  104.004 65.328 104.088 65.352 ;
    END
  END a[265]
  PIN a[266]
    DIRECTION INPUT ;
    USE SIGNAL ;
    PORT
      LAYER M4 ;
        RECT  104.004 65.424 104.088 65.448 ;
    END
  END a[266]
  PIN a[267]
    DIRECTION INPUT ;
    USE SIGNAL ;
    PORT
      LAYER M4 ;
        RECT  104.004 65.52 104.088 65.544 ;
    END
  END a[267]
  PIN a[268]
    DIRECTION INPUT ;
    USE SIGNAL ;
    PORT
      LAYER M4 ;
        RECT  104.004 65.616 104.088 65.64 ;
    END
  END a[268]
  PIN a[269]
    DIRECTION INPUT ;
    USE SIGNAL ;
    PORT
      LAYER M4 ;
        RECT  104.004 65.712 104.088 65.736 ;
    END
  END a[269]
  PIN a[26]
    DIRECTION INPUT ;
    USE SIGNAL ;
    PORT
      LAYER M4 ;
        RECT  104.004 44.688 104.088 44.712 ;
    END
  END a[26]
  PIN a[270]
    DIRECTION INPUT ;
    USE SIGNAL ;
    PORT
      LAYER M4 ;
        RECT  104.004 65.808 104.088 65.832 ;
    END
  END a[270]
  PIN a[271]
    DIRECTION INPUT ;
    USE SIGNAL ;
    PORT
      LAYER M4 ;
        RECT  104.004 65.904 104.088 65.928 ;
    END
  END a[271]
  PIN a[272]
    DIRECTION INPUT ;
    USE SIGNAL ;
    PORT
      LAYER M4 ;
        RECT  104.004 66 104.088 66.024 ;
    END
  END a[272]
  PIN a[273]
    DIRECTION INPUT ;
    USE SIGNAL ;
    PORT
      LAYER M4 ;
        RECT  104.004 66.096 104.088 66.12 ;
    END
  END a[273]
  PIN a[274]
    DIRECTION INPUT ;
    USE SIGNAL ;
    PORT
      LAYER M4 ;
        RECT  104.004 66.192 104.088 66.216 ;
    END
  END a[274]
  PIN a[275]
    DIRECTION INPUT ;
    USE SIGNAL ;
    PORT
      LAYER M4 ;
        RECT  104.004 66.288 104.088 66.312 ;
    END
  END a[275]
  PIN a[276]
    DIRECTION INPUT ;
    USE SIGNAL ;
    PORT
      LAYER M4 ;
        RECT  104.004 66.384 104.088 66.408 ;
    END
  END a[276]
  PIN a[277]
    DIRECTION INPUT ;
    USE SIGNAL ;
    PORT
      LAYER M4 ;
        RECT  104.004 66.48 104.088 66.504 ;
    END
  END a[277]
  PIN a[278]
    DIRECTION INPUT ;
    USE SIGNAL ;
    PORT
      LAYER M4 ;
        RECT  104.004 66.576 104.088 66.6 ;
    END
  END a[278]
  PIN a[279]
    DIRECTION INPUT ;
    USE SIGNAL ;
    PORT
      LAYER M4 ;
        RECT  104.004 66.672 104.088 66.696 ;
    END
  END a[279]
  PIN a[27]
    DIRECTION INPUT ;
    USE SIGNAL ;
    PORT
      LAYER M4 ;
        RECT  104.004 44.784 104.088 44.808 ;
    END
  END a[27]
  PIN a[280]
    DIRECTION INPUT ;
    USE SIGNAL ;
    PORT
      LAYER M4 ;
        RECT  104.004 66.768 104.088 66.792 ;
    END
  END a[280]
  PIN a[281]
    DIRECTION INPUT ;
    USE SIGNAL ;
    PORT
      LAYER M4 ;
        RECT  104.004 66.864 104.088 66.888 ;
    END
  END a[281]
  PIN a[282]
    DIRECTION INPUT ;
    USE SIGNAL ;
    PORT
      LAYER M4 ;
        RECT  104.004 66.96 104.088 66.984 ;
    END
  END a[282]
  PIN a[283]
    DIRECTION INPUT ;
    USE SIGNAL ;
    PORT
      LAYER M4 ;
        RECT  104.004 67.056 104.088 67.08 ;
    END
  END a[283]
  PIN a[284]
    DIRECTION INPUT ;
    USE SIGNAL ;
    PORT
      LAYER M4 ;
        RECT  104.004 67.152 104.088 67.176 ;
    END
  END a[284]
  PIN a[285]
    DIRECTION INPUT ;
    USE SIGNAL ;
    PORT
      LAYER M4 ;
        RECT  104.004 67.248 104.088 67.272 ;
    END
  END a[285]
  PIN a[286]
    DIRECTION INPUT ;
    USE SIGNAL ;
    PORT
      LAYER M4 ;
        RECT  104.004 67.344 104.088 67.368 ;
    END
  END a[286]
  PIN a[287]
    DIRECTION INPUT ;
    USE SIGNAL ;
    PORT
      LAYER M4 ;
        RECT  104.004 67.44 104.088 67.464 ;
    END
  END a[287]
  PIN a[288]
    DIRECTION INPUT ;
    USE SIGNAL ;
    PORT
      LAYER M4 ;
        RECT  104.004 67.536 104.088 67.56 ;
    END
  END a[288]
  PIN a[289]
    DIRECTION INPUT ;
    USE SIGNAL ;
    PORT
      LAYER M4 ;
        RECT  104.004 67.632 104.088 67.656 ;
    END
  END a[289]
  PIN a[28]
    DIRECTION INPUT ;
    USE SIGNAL ;
    PORT
      LAYER M4 ;
        RECT  104.004 44.88 104.088 44.904 ;
    END
  END a[28]
  PIN a[290]
    DIRECTION INPUT ;
    USE SIGNAL ;
    PORT
      LAYER M4 ;
        RECT  104.004 67.728 104.088 67.752 ;
    END
  END a[290]
  PIN a[291]
    DIRECTION INPUT ;
    USE SIGNAL ;
    PORT
      LAYER M4 ;
        RECT  104.004 67.824 104.088 67.848 ;
    END
  END a[291]
  PIN a[292]
    DIRECTION INPUT ;
    USE SIGNAL ;
    PORT
      LAYER M4 ;
        RECT  104.004 67.92 104.088 67.944 ;
    END
  END a[292]
  PIN a[293]
    DIRECTION INPUT ;
    USE SIGNAL ;
    PORT
      LAYER M4 ;
        RECT  104.004 68.016 104.088 68.04 ;
    END
  END a[293]
  PIN a[294]
    DIRECTION INPUT ;
    USE SIGNAL ;
    PORT
      LAYER M4 ;
        RECT  104.004 68.112 104.088 68.136 ;
    END
  END a[294]
  PIN a[295]
    DIRECTION INPUT ;
    USE SIGNAL ;
    PORT
      LAYER M4 ;
        RECT  104.004 68.208 104.088 68.232 ;
    END
  END a[295]
  PIN a[296]
    DIRECTION INPUT ;
    USE SIGNAL ;
    PORT
      LAYER M4 ;
        RECT  104.004 68.304 104.088 68.328 ;
    END
  END a[296]
  PIN a[297]
    DIRECTION INPUT ;
    USE SIGNAL ;
    PORT
      LAYER M4 ;
        RECT  104.004 68.4 104.088 68.424 ;
    END
  END a[297]
  PIN a[298]
    DIRECTION INPUT ;
    USE SIGNAL ;
    PORT
      LAYER M4 ;
        RECT  104.004 68.496 104.088 68.52 ;
    END
  END a[298]
  PIN a[299]
    DIRECTION INPUT ;
    USE SIGNAL ;
    PORT
      LAYER M4 ;
        RECT  104.004 68.592 104.088 68.616 ;
    END
  END a[299]
  PIN a[29]
    DIRECTION INPUT ;
    USE SIGNAL ;
    PORT
      LAYER M4 ;
        RECT  104.004 44.976 104.088 45 ;
    END
  END a[29]
  PIN a[2]
    DIRECTION INPUT ;
    USE SIGNAL ;
    PORT
      LAYER M4 ;
        RECT  104.004 42.384 104.088 42.408 ;
    END
  END a[2]
  PIN a[300]
    DIRECTION INPUT ;
    USE SIGNAL ;
    PORT
      LAYER M4 ;
        RECT  104.004 68.688 104.088 68.712 ;
    END
  END a[300]
  PIN a[301]
    DIRECTION INPUT ;
    USE SIGNAL ;
    PORT
      LAYER M4 ;
        RECT  104.004 68.784 104.088 68.808 ;
    END
  END a[301]
  PIN a[302]
    DIRECTION INPUT ;
    USE SIGNAL ;
    PORT
      LAYER M4 ;
        RECT  104.004 68.88 104.088 68.904 ;
    END
  END a[302]
  PIN a[303]
    DIRECTION INPUT ;
    USE SIGNAL ;
    PORT
      LAYER M4 ;
        RECT  104.004 68.976 104.088 69 ;
    END
  END a[303]
  PIN a[304]
    DIRECTION INPUT ;
    USE SIGNAL ;
    PORT
      LAYER M4 ;
        RECT  104.004 69.072 104.088 69.096 ;
    END
  END a[304]
  PIN a[305]
    DIRECTION INPUT ;
    USE SIGNAL ;
    PORT
      LAYER M4 ;
        RECT  104.004 69.168 104.088 69.192 ;
    END
  END a[305]
  PIN a[306]
    DIRECTION INPUT ;
    USE SIGNAL ;
    PORT
      LAYER M4 ;
        RECT  104.004 69.264 104.088 69.288 ;
    END
  END a[306]
  PIN a[307]
    DIRECTION INPUT ;
    USE SIGNAL ;
    PORT
      LAYER M4 ;
        RECT  104.004 69.36 104.088 69.384 ;
    END
  END a[307]
  PIN a[308]
    DIRECTION INPUT ;
    USE SIGNAL ;
    PORT
      LAYER M4 ;
        RECT  104.004 69.456 104.088 69.48 ;
    END
  END a[308]
  PIN a[309]
    DIRECTION INPUT ;
    USE SIGNAL ;
    PORT
      LAYER M4 ;
        RECT  104.004 69.552 104.088 69.576 ;
    END
  END a[309]
  PIN a[30]
    DIRECTION INPUT ;
    USE SIGNAL ;
    PORT
      LAYER M4 ;
        RECT  104.004 45.072 104.088 45.096 ;
    END
  END a[30]
  PIN a[310]
    DIRECTION INPUT ;
    USE SIGNAL ;
    PORT
      LAYER M4 ;
        RECT  104.004 69.648 104.088 69.672 ;
    END
  END a[310]
  PIN a[311]
    DIRECTION INPUT ;
    USE SIGNAL ;
    PORT
      LAYER M4 ;
        RECT  104.004 69.744 104.088 69.768 ;
    END
  END a[311]
  PIN a[312]
    DIRECTION INPUT ;
    USE SIGNAL ;
    PORT
      LAYER M4 ;
        RECT  104.004 69.84 104.088 69.864 ;
    END
  END a[312]
  PIN a[313]
    DIRECTION INPUT ;
    USE SIGNAL ;
    PORT
      LAYER M4 ;
        RECT  104.004 69.936 104.088 69.96 ;
    END
  END a[313]
  PIN a[314]
    DIRECTION INPUT ;
    USE SIGNAL ;
    PORT
      LAYER M4 ;
        RECT  104.004 70.032 104.088 70.056 ;
    END
  END a[314]
  PIN a[315]
    DIRECTION INPUT ;
    USE SIGNAL ;
    PORT
      LAYER M4 ;
        RECT  104.004 70.128 104.088 70.152 ;
    END
  END a[315]
  PIN a[316]
    DIRECTION INPUT ;
    USE SIGNAL ;
    PORT
      LAYER M4 ;
        RECT  104.004 70.224 104.088 70.248 ;
    END
  END a[316]
  PIN a[317]
    DIRECTION INPUT ;
    USE SIGNAL ;
    PORT
      LAYER M4 ;
        RECT  104.004 70.32 104.088 70.344 ;
    END
  END a[317]
  PIN a[318]
    DIRECTION INPUT ;
    USE SIGNAL ;
    PORT
      LAYER M4 ;
        RECT  104.004 70.416 104.088 70.44 ;
    END
  END a[318]
  PIN a[319]
    DIRECTION INPUT ;
    USE SIGNAL ;
    PORT
      LAYER M4 ;
        RECT  104.004 70.512 104.088 70.536 ;
    END
  END a[319]
  PIN a[31]
    DIRECTION INPUT ;
    USE SIGNAL ;
    PORT
      LAYER M4 ;
        RECT  104.004 45.168 104.088 45.192 ;
    END
  END a[31]
  PIN a[320]
    DIRECTION INPUT ;
    USE SIGNAL ;
    PORT
      LAYER M4 ;
        RECT  104.004 70.608 104.088 70.632 ;
    END
  END a[320]
  PIN a[321]
    DIRECTION INPUT ;
    USE SIGNAL ;
    PORT
      LAYER M4 ;
        RECT  104.004 70.704 104.088 70.728 ;
    END
  END a[321]
  PIN a[322]
    DIRECTION INPUT ;
    USE SIGNAL ;
    PORT
      LAYER M4 ;
        RECT  104.004 70.8 104.088 70.824 ;
    END
  END a[322]
  PIN a[323]
    DIRECTION INPUT ;
    USE SIGNAL ;
    PORT
      LAYER M4 ;
        RECT  104.004 70.896 104.088 70.92 ;
    END
  END a[323]
  PIN a[324]
    DIRECTION INPUT ;
    USE SIGNAL ;
    PORT
      LAYER M4 ;
        RECT  104.004 70.992 104.088 71.016 ;
    END
  END a[324]
  PIN a[325]
    DIRECTION INPUT ;
    USE SIGNAL ;
    PORT
      LAYER M4 ;
        RECT  104.004 71.088 104.088 71.112 ;
    END
  END a[325]
  PIN a[326]
    DIRECTION INPUT ;
    USE SIGNAL ;
    PORT
      LAYER M4 ;
        RECT  104.004 71.184 104.088 71.208 ;
    END
  END a[326]
  PIN a[327]
    DIRECTION INPUT ;
    USE SIGNAL ;
    PORT
      LAYER M4 ;
        RECT  104.004 71.28 104.088 71.304 ;
    END
  END a[327]
  PIN a[328]
    DIRECTION INPUT ;
    USE SIGNAL ;
    PORT
      LAYER M4 ;
        RECT  104.004 71.376 104.088 71.4 ;
    END
  END a[328]
  PIN a[329]
    DIRECTION INPUT ;
    USE SIGNAL ;
    PORT
      LAYER M4 ;
        RECT  104.004 71.472 104.088 71.496 ;
    END
  END a[329]
  PIN a[32]
    DIRECTION INPUT ;
    USE SIGNAL ;
    PORT
      LAYER M4 ;
        RECT  104.004 54.48 104.088 54.504 ;
    END
  END a[32]
  PIN a[330]
    DIRECTION INPUT ;
    USE SIGNAL ;
    PORT
      LAYER M4 ;
        RECT  104.004 71.568 104.088 71.592 ;
    END
  END a[330]
  PIN a[331]
    DIRECTION INPUT ;
    USE SIGNAL ;
    PORT
      LAYER M4 ;
        RECT  104.004 71.664 104.088 71.688 ;
    END
  END a[331]
  PIN a[332]
    DIRECTION INPUT ;
    USE SIGNAL ;
    PORT
      LAYER M4 ;
        RECT  104.004 71.76 104.088 71.784 ;
    END
  END a[332]
  PIN a[333]
    DIRECTION INPUT ;
    USE SIGNAL ;
    PORT
      LAYER M4 ;
        RECT  104.004 71.856 104.088 71.88 ;
    END
  END a[333]
  PIN a[334]
    DIRECTION INPUT ;
    USE SIGNAL ;
    PORT
      LAYER M4 ;
        RECT  104.004 71.952 104.088 71.976 ;
    END
  END a[334]
  PIN a[335]
    DIRECTION INPUT ;
    USE SIGNAL ;
    PORT
      LAYER M4 ;
        RECT  104.004 72.048 104.088 72.072 ;
    END
  END a[335]
  PIN a[336]
    DIRECTION INPUT ;
    USE SIGNAL ;
    PORT
      LAYER M4 ;
        RECT  104.004 72.144 104.088 72.168 ;
    END
  END a[336]
  PIN a[337]
    DIRECTION INPUT ;
    USE SIGNAL ;
    PORT
      LAYER M4 ;
        RECT  104.004 72.24 104.088 72.264 ;
    END
  END a[337]
  PIN a[338]
    DIRECTION INPUT ;
    USE SIGNAL ;
    PORT
      LAYER M4 ;
        RECT  104.004 72.336 104.088 72.36 ;
    END
  END a[338]
  PIN a[339]
    DIRECTION INPUT ;
    USE SIGNAL ;
    PORT
      LAYER M4 ;
        RECT  104.004 72.432 104.088 72.456 ;
    END
  END a[339]
  PIN a[33]
    DIRECTION INPUT ;
    USE SIGNAL ;
    PORT
      LAYER M4 ;
        RECT  104.004 54.576 104.088 54.6 ;
    END
  END a[33]
  PIN a[340]
    DIRECTION INPUT ;
    USE SIGNAL ;
    PORT
      LAYER M4 ;
        RECT  104.004 72.528 104.088 72.552 ;
    END
  END a[340]
  PIN a[341]
    DIRECTION INPUT ;
    USE SIGNAL ;
    PORT
      LAYER M4 ;
        RECT  104.004 72.624 104.088 72.648 ;
    END
  END a[341]
  PIN a[342]
    DIRECTION INPUT ;
    USE SIGNAL ;
    PORT
      LAYER M4 ;
        RECT  104.004 72.72 104.088 72.744 ;
    END
  END a[342]
  PIN a[343]
    DIRECTION INPUT ;
    USE SIGNAL ;
    PORT
      LAYER M4 ;
        RECT  104.004 72.816 104.088 72.84 ;
    END
  END a[343]
  PIN a[344]
    DIRECTION INPUT ;
    USE SIGNAL ;
    PORT
      LAYER M4 ;
        RECT  104.004 72.912 104.088 72.936 ;
    END
  END a[344]
  PIN a[345]
    DIRECTION INPUT ;
    USE SIGNAL ;
    PORT
      LAYER M4 ;
        RECT  104.004 73.008 104.088 73.032 ;
    END
  END a[345]
  PIN a[346]
    DIRECTION INPUT ;
    USE SIGNAL ;
    PORT
      LAYER M4 ;
        RECT  104.004 73.104 104.088 73.128 ;
    END
  END a[346]
  PIN a[347]
    DIRECTION INPUT ;
    USE SIGNAL ;
    PORT
      LAYER M4 ;
        RECT  104.004 73.2 104.088 73.224 ;
    END
  END a[347]
  PIN a[348]
    DIRECTION INPUT ;
    USE SIGNAL ;
    PORT
      LAYER M4 ;
        RECT  104.004 73.296 104.088 73.32 ;
    END
  END a[348]
  PIN a[349]
    DIRECTION INPUT ;
    USE SIGNAL ;
    PORT
      LAYER M4 ;
        RECT  104.004 73.392 104.088 73.416 ;
    END
  END a[349]
  PIN a[34]
    DIRECTION INPUT ;
    USE SIGNAL ;
    PORT
      LAYER M4 ;
        RECT  104.004 54.672 104.088 54.696 ;
    END
  END a[34]
  PIN a[350]
    DIRECTION INPUT ;
    USE SIGNAL ;
    PORT
      LAYER M4 ;
        RECT  104.004 73.488 104.088 73.512 ;
    END
  END a[350]
  PIN a[351]
    DIRECTION INPUT ;
    USE SIGNAL ;
    PORT
      LAYER M4 ;
        RECT  104.004 73.584 104.088 73.608 ;
    END
  END a[351]
  PIN a[352]
    DIRECTION INPUT ;
    USE SIGNAL ;
    PORT
      LAYER M4 ;
        RECT  104.004 61.392 104.088 61.416 ;
    END
  END a[352]
  PIN a[353]
    DIRECTION INPUT ;
    USE SIGNAL ;
    PORT
      LAYER M4 ;
        RECT  104.004 61.488 104.088 61.512 ;
    END
  END a[353]
  PIN a[354]
    DIRECTION INPUT ;
    USE SIGNAL ;
    PORT
      LAYER M4 ;
        RECT  104.004 61.584 104.088 61.608 ;
    END
  END a[354]
  PIN a[355]
    DIRECTION INPUT ;
    USE SIGNAL ;
    PORT
      LAYER M4 ;
        RECT  104.004 61.68 104.088 61.704 ;
    END
  END a[355]
  PIN a[356]
    DIRECTION INPUT ;
    USE SIGNAL ;
    PORT
      LAYER M4 ;
        RECT  104.004 61.776 104.088 61.8 ;
    END
  END a[356]
  PIN a[357]
    DIRECTION INPUT ;
    USE SIGNAL ;
    PORT
      LAYER M4 ;
        RECT  104.004 61.872 104.088 61.896 ;
    END
  END a[357]
  PIN a[358]
    DIRECTION INPUT ;
    USE SIGNAL ;
    PORT
      LAYER M4 ;
        RECT  104.004 61.968 104.088 61.992 ;
    END
  END a[358]
  PIN a[359]
    DIRECTION INPUT ;
    USE SIGNAL ;
    PORT
      LAYER M4 ;
        RECT  104.004 62.064 104.088 62.088 ;
    END
  END a[359]
  PIN a[35]
    DIRECTION INPUT ;
    USE SIGNAL ;
    PORT
      LAYER M4 ;
        RECT  104.004 54.768 104.088 54.792 ;
    END
  END a[35]
  PIN a[360]
    DIRECTION INPUT ;
    USE SIGNAL ;
    PORT
      LAYER M4 ;
        RECT  104.004 62.16 104.088 62.184 ;
    END
  END a[360]
  PIN a[361]
    DIRECTION INPUT ;
    USE SIGNAL ;
    PORT
      LAYER M4 ;
        RECT  104.004 62.256 104.088 62.28 ;
    END
  END a[361]
  PIN a[362]
    DIRECTION INPUT ;
    USE SIGNAL ;
    PORT
      LAYER M4 ;
        RECT  104.004 62.352 104.088 62.376 ;
    END
  END a[362]
  PIN a[363]
    DIRECTION INPUT ;
    USE SIGNAL ;
    PORT
      LAYER M4 ;
        RECT  104.004 62.448 104.088 62.472 ;
    END
  END a[363]
  PIN a[364]
    DIRECTION INPUT ;
    USE SIGNAL ;
    PORT
      LAYER M4 ;
        RECT  104.004 62.544 104.088 62.568 ;
    END
  END a[364]
  PIN a[365]
    DIRECTION INPUT ;
    USE SIGNAL ;
    PORT
      LAYER M4 ;
        RECT  104.004 62.64 104.088 62.664 ;
    END
  END a[365]
  PIN a[366]
    DIRECTION INPUT ;
    USE SIGNAL ;
    PORT
      LAYER M4 ;
        RECT  104.004 62.736 104.088 62.76 ;
    END
  END a[366]
  PIN a[367]
    DIRECTION INPUT ;
    USE SIGNAL ;
    PORT
      LAYER M4 ;
        RECT  104.004 62.832 104.088 62.856 ;
    END
  END a[367]
  PIN a[368]
    DIRECTION INPUT ;
    USE SIGNAL ;
    PORT
      LAYER M4 ;
        RECT  104.004 62.928 104.088 62.952 ;
    END
  END a[368]
  PIN a[369]
    DIRECTION INPUT ;
    USE SIGNAL ;
    PORT
      LAYER M4 ;
        RECT  104.004 63.024 104.088 63.048 ;
    END
  END a[369]
  PIN a[36]
    DIRECTION INPUT ;
    USE SIGNAL ;
    PORT
      LAYER M4 ;
        RECT  104.004 54.864 104.088 54.888 ;
    END
  END a[36]
  PIN a[370]
    DIRECTION INPUT ;
    USE SIGNAL ;
    PORT
      LAYER M4 ;
        RECT  104.004 63.12 104.088 63.144 ;
    END
  END a[370]
  PIN a[371]
    DIRECTION INPUT ;
    USE SIGNAL ;
    PORT
      LAYER M4 ;
        RECT  104.004 63.216 104.088 63.24 ;
    END
  END a[371]
  PIN a[372]
    DIRECTION INPUT ;
    USE SIGNAL ;
    PORT
      LAYER M4 ;
        RECT  104.004 63.312 104.088 63.336 ;
    END
  END a[372]
  PIN a[373]
    DIRECTION INPUT ;
    USE SIGNAL ;
    PORT
      LAYER M4 ;
        RECT  104.004 63.408 104.088 63.432 ;
    END
  END a[373]
  PIN a[374]
    DIRECTION INPUT ;
    USE SIGNAL ;
    PORT
      LAYER M4 ;
        RECT  104.004 63.504 104.088 63.528 ;
    END
  END a[374]
  PIN a[375]
    DIRECTION INPUT ;
    USE SIGNAL ;
    PORT
      LAYER M4 ;
        RECT  104.004 63.6 104.088 63.624 ;
    END
  END a[375]
  PIN a[376]
    DIRECTION INPUT ;
    USE SIGNAL ;
    PORT
      LAYER M4 ;
        RECT  104.004 63.696 104.088 63.72 ;
    END
  END a[376]
  PIN a[377]
    DIRECTION INPUT ;
    USE SIGNAL ;
    PORT
      LAYER M4 ;
        RECT  104.004 63.792 104.088 63.816 ;
    END
  END a[377]
  PIN a[378]
    DIRECTION INPUT ;
    USE SIGNAL ;
    PORT
      LAYER M4 ;
        RECT  104.004 63.888 104.088 63.912 ;
    END
  END a[378]
  PIN a[379]
    DIRECTION INPUT ;
    USE SIGNAL ;
    PORT
      LAYER M4 ;
        RECT  104.004 63.984 104.088 64.008 ;
    END
  END a[379]
  PIN a[37]
    DIRECTION INPUT ;
    USE SIGNAL ;
    PORT
      LAYER M4 ;
        RECT  104.004 54.96 104.088 54.984 ;
    END
  END a[37]
  PIN a[380]
    DIRECTION INPUT ;
    USE SIGNAL ;
    PORT
      LAYER M4 ;
        RECT  104.004 64.08 104.088 64.104 ;
    END
  END a[380]
  PIN a[381]
    DIRECTION INPUT ;
    USE SIGNAL ;
    PORT
      LAYER M4 ;
        RECT  104.004 64.176 104.088 64.2 ;
    END
  END a[381]
  PIN a[382]
    DIRECTION INPUT ;
    USE SIGNAL ;
    PORT
      LAYER M4 ;
        RECT  104.004 64.272 104.088 64.296 ;
    END
  END a[382]
  PIN a[383]
    DIRECTION INPUT ;
    USE SIGNAL ;
    PORT
      LAYER M4 ;
        RECT  104.004 64.368 104.088 64.392 ;
    END
  END a[383]
  PIN a[384]
    DIRECTION INPUT ;
    USE SIGNAL ;
    PORT
      LAYER M4 ;
        RECT  104.004 19.92 104.088 19.944 ;
    END
  END a[384]
  PIN a[385]
    DIRECTION INPUT ;
    USE SIGNAL ;
    PORT
      LAYER M4 ;
        RECT  104.004 20.016 104.088 20.04 ;
    END
  END a[385]
  PIN a[386]
    DIRECTION INPUT ;
    USE SIGNAL ;
    PORT
      LAYER M4 ;
        RECT  104.004 20.112 104.088 20.136 ;
    END
  END a[386]
  PIN a[387]
    DIRECTION INPUT ;
    USE SIGNAL ;
    PORT
      LAYER M4 ;
        RECT  104.004 20.208 104.088 20.232 ;
    END
  END a[387]
  PIN a[388]
    DIRECTION INPUT ;
    USE SIGNAL ;
    PORT
      LAYER M4 ;
        RECT  104.004 20.304 104.088 20.328 ;
    END
  END a[388]
  PIN a[389]
    DIRECTION INPUT ;
    USE SIGNAL ;
    PORT
      LAYER M4 ;
        RECT  104.004 20.4 104.088 20.424 ;
    END
  END a[389]
  PIN a[38]
    DIRECTION INPUT ;
    USE SIGNAL ;
    PORT
      LAYER M4 ;
        RECT  104.004 55.056 104.088 55.08 ;
    END
  END a[38]
  PIN a[390]
    DIRECTION INPUT ;
    USE SIGNAL ;
    PORT
      LAYER M4 ;
        RECT  104.004 20.496 104.088 20.52 ;
    END
  END a[390]
  PIN a[391]
    DIRECTION INPUT ;
    USE SIGNAL ;
    PORT
      LAYER M4 ;
        RECT  104.004 20.592 104.088 20.616 ;
    END
  END a[391]
  PIN a[392]
    DIRECTION INPUT ;
    USE SIGNAL ;
    PORT
      LAYER M4 ;
        RECT  104.004 20.688 104.088 20.712 ;
    END
  END a[392]
  PIN a[393]
    DIRECTION INPUT ;
    USE SIGNAL ;
    PORT
      LAYER M4 ;
        RECT  104.004 20.784 104.088 20.808 ;
    END
  END a[393]
  PIN a[394]
    DIRECTION INPUT ;
    USE SIGNAL ;
    PORT
      LAYER M4 ;
        RECT  104.004 20.88 104.088 20.904 ;
    END
  END a[394]
  PIN a[395]
    DIRECTION INPUT ;
    USE SIGNAL ;
    PORT
      LAYER M4 ;
        RECT  104.004 20.976 104.088 21 ;
    END
  END a[395]
  PIN a[396]
    DIRECTION INPUT ;
    USE SIGNAL ;
    PORT
      LAYER M4 ;
        RECT  104.004 21.072 104.088 21.096 ;
    END
  END a[396]
  PIN a[397]
    DIRECTION INPUT ;
    USE SIGNAL ;
    PORT
      LAYER M4 ;
        RECT  104.004 21.168 104.088 21.192 ;
    END
  END a[397]
  PIN a[398]
    DIRECTION INPUT ;
    USE SIGNAL ;
    PORT
      LAYER M4 ;
        RECT  104.004 21.264 104.088 21.288 ;
    END
  END a[398]
  PIN a[399]
    DIRECTION INPUT ;
    USE SIGNAL ;
    PORT
      LAYER M4 ;
        RECT  104.004 21.36 104.088 21.384 ;
    END
  END a[399]
  PIN a[39]
    DIRECTION INPUT ;
    USE SIGNAL ;
    PORT
      LAYER M4 ;
        RECT  104.004 55.152 104.088 55.176 ;
    END
  END a[39]
  PIN a[3]
    DIRECTION INPUT ;
    USE SIGNAL ;
    PORT
      LAYER M4 ;
        RECT  104.004 42.48 104.088 42.504 ;
    END
  END a[3]
  PIN a[400]
    DIRECTION INPUT ;
    USE SIGNAL ;
    PORT
      LAYER M4 ;
        RECT  104.004 21.456 104.088 21.48 ;
    END
  END a[400]
  PIN a[401]
    DIRECTION INPUT ;
    USE SIGNAL ;
    PORT
      LAYER M4 ;
        RECT  104.004 21.552 104.088 21.576 ;
    END
  END a[401]
  PIN a[402]
    DIRECTION INPUT ;
    USE SIGNAL ;
    PORT
      LAYER M4 ;
        RECT  104.004 21.648 104.088 21.672 ;
    END
  END a[402]
  PIN a[403]
    DIRECTION INPUT ;
    USE SIGNAL ;
    PORT
      LAYER M4 ;
        RECT  104.004 21.744 104.088 21.768 ;
    END
  END a[403]
  PIN a[404]
    DIRECTION INPUT ;
    USE SIGNAL ;
    PORT
      LAYER M4 ;
        RECT  104.004 21.84 104.088 21.864 ;
    END
  END a[404]
  PIN a[405]
    DIRECTION INPUT ;
    USE SIGNAL ;
    PORT
      LAYER M4 ;
        RECT  104.004 21.936 104.088 21.96 ;
    END
  END a[405]
  PIN a[406]
    DIRECTION INPUT ;
    USE SIGNAL ;
    PORT
      LAYER M4 ;
        RECT  104.004 22.032 104.088 22.056 ;
    END
  END a[406]
  PIN a[407]
    DIRECTION INPUT ;
    USE SIGNAL ;
    PORT
      LAYER M4 ;
        RECT  104.004 22.128 104.088 22.152 ;
    END
  END a[407]
  PIN a[408]
    DIRECTION INPUT ;
    USE SIGNAL ;
    PORT
      LAYER M4 ;
        RECT  104.004 22.224 104.088 22.248 ;
    END
  END a[408]
  PIN a[409]
    DIRECTION INPUT ;
    USE SIGNAL ;
    PORT
      LAYER M4 ;
        RECT  104.004 22.32 104.088 22.344 ;
    END
  END a[409]
  PIN a[40]
    DIRECTION INPUT ;
    USE SIGNAL ;
    PORT
      LAYER M4 ;
        RECT  104.004 55.248 104.088 55.272 ;
    END
  END a[40]
  PIN a[410]
    DIRECTION INPUT ;
    USE SIGNAL ;
    PORT
      LAYER M4 ;
        RECT  104.004 22.416 104.088 22.44 ;
    END
  END a[410]
  PIN a[411]
    DIRECTION INPUT ;
    USE SIGNAL ;
    PORT
      LAYER M4 ;
        RECT  104.004 22.512 104.088 22.536 ;
    END
  END a[411]
  PIN a[412]
    DIRECTION INPUT ;
    USE SIGNAL ;
    PORT
      LAYER M4 ;
        RECT  104.004 22.608 104.088 22.632 ;
    END
  END a[412]
  PIN a[413]
    DIRECTION INPUT ;
    USE SIGNAL ;
    PORT
      LAYER M4 ;
        RECT  104.004 22.704 104.088 22.728 ;
    END
  END a[413]
  PIN a[414]
    DIRECTION INPUT ;
    USE SIGNAL ;
    PORT
      LAYER M4 ;
        RECT  104.004 22.8 104.088 22.824 ;
    END
  END a[414]
  PIN a[415]
    DIRECTION INPUT ;
    USE SIGNAL ;
    PORT
      LAYER M4 ;
        RECT  104.004 22.896 104.088 22.92 ;
    END
  END a[415]
  PIN a[416]
    DIRECTION INPUT ;
    USE SIGNAL ;
    PORT
      LAYER M4 ;
        RECT  104.004 22.992 104.088 23.016 ;
    END
  END a[416]
  PIN a[417]
    DIRECTION INPUT ;
    USE SIGNAL ;
    PORT
      LAYER M4 ;
        RECT  104.004 23.088 104.088 23.112 ;
    END
  END a[417]
  PIN a[418]
    DIRECTION INPUT ;
    USE SIGNAL ;
    PORT
      LAYER M4 ;
        RECT  104.004 23.184 104.088 23.208 ;
    END
  END a[418]
  PIN a[419]
    DIRECTION INPUT ;
    USE SIGNAL ;
    PORT
      LAYER M4 ;
        RECT  104.004 23.28 104.088 23.304 ;
    END
  END a[419]
  PIN a[41]
    DIRECTION INPUT ;
    USE SIGNAL ;
    PORT
      LAYER M4 ;
        RECT  104.004 55.344 104.088 55.368 ;
    END
  END a[41]
  PIN a[420]
    DIRECTION INPUT ;
    USE SIGNAL ;
    PORT
      LAYER M4 ;
        RECT  104.004 23.376 104.088 23.4 ;
    END
  END a[420]
  PIN a[421]
    DIRECTION INPUT ;
    USE SIGNAL ;
    PORT
      LAYER M4 ;
        RECT  104.004 23.472 104.088 23.496 ;
    END
  END a[421]
  PIN a[422]
    DIRECTION INPUT ;
    USE SIGNAL ;
    PORT
      LAYER M4 ;
        RECT  104.004 23.568 104.088 23.592 ;
    END
  END a[422]
  PIN a[423]
    DIRECTION INPUT ;
    USE SIGNAL ;
    PORT
      LAYER M4 ;
        RECT  104.004 23.664 104.088 23.688 ;
    END
  END a[423]
  PIN a[424]
    DIRECTION INPUT ;
    USE SIGNAL ;
    PORT
      LAYER M4 ;
        RECT  104.004 23.76 104.088 23.784 ;
    END
  END a[424]
  PIN a[425]
    DIRECTION INPUT ;
    USE SIGNAL ;
    PORT
      LAYER M4 ;
        RECT  104.004 23.856 104.088 23.88 ;
    END
  END a[425]
  PIN a[426]
    DIRECTION INPUT ;
    USE SIGNAL ;
    PORT
      LAYER M4 ;
        RECT  104.004 23.952 104.088 23.976 ;
    END
  END a[426]
  PIN a[427]
    DIRECTION INPUT ;
    USE SIGNAL ;
    PORT
      LAYER M4 ;
        RECT  104.004 24.048 104.088 24.072 ;
    END
  END a[427]
  PIN a[428]
    DIRECTION INPUT ;
    USE SIGNAL ;
    PORT
      LAYER M4 ;
        RECT  104.004 24.144 104.088 24.168 ;
    END
  END a[428]
  PIN a[429]
    DIRECTION INPUT ;
    USE SIGNAL ;
    PORT
      LAYER M4 ;
        RECT  104.004 24.24 104.088 24.264 ;
    END
  END a[429]
  PIN a[42]
    DIRECTION INPUT ;
    USE SIGNAL ;
    PORT
      LAYER M4 ;
        RECT  104.004 55.44 104.088 55.464 ;
    END
  END a[42]
  PIN a[430]
    DIRECTION INPUT ;
    USE SIGNAL ;
    PORT
      LAYER M4 ;
        RECT  104.004 24.336 104.088 24.36 ;
    END
  END a[430]
  PIN a[431]
    DIRECTION INPUT ;
    USE SIGNAL ;
    PORT
      LAYER M4 ;
        RECT  104.004 24.432 104.088 24.456 ;
    END
  END a[431]
  PIN a[432]
    DIRECTION INPUT ;
    USE SIGNAL ;
    PORT
      LAYER M4 ;
        RECT  104.004 24.528 104.088 24.552 ;
    END
  END a[432]
  PIN a[433]
    DIRECTION INPUT ;
    USE SIGNAL ;
    PORT
      LAYER M4 ;
        RECT  104.004 24.624 104.088 24.648 ;
    END
  END a[433]
  PIN a[434]
    DIRECTION INPUT ;
    USE SIGNAL ;
    PORT
      LAYER M4 ;
        RECT  104.004 24.72 104.088 24.744 ;
    END
  END a[434]
  PIN a[435]
    DIRECTION INPUT ;
    USE SIGNAL ;
    PORT
      LAYER M4 ;
        RECT  104.004 24.816 104.088 24.84 ;
    END
  END a[435]
  PIN a[436]
    DIRECTION INPUT ;
    USE SIGNAL ;
    PORT
      LAYER M4 ;
        RECT  104.004 24.912 104.088 24.936 ;
    END
  END a[436]
  PIN a[437]
    DIRECTION INPUT ;
    USE SIGNAL ;
    PORT
      LAYER M4 ;
        RECT  104.004 25.008 104.088 25.032 ;
    END
  END a[437]
  PIN a[438]
    DIRECTION INPUT ;
    USE SIGNAL ;
    PORT
      LAYER M4 ;
        RECT  104.004 25.104 104.088 25.128 ;
    END
  END a[438]
  PIN a[439]
    DIRECTION INPUT ;
    USE SIGNAL ;
    PORT
      LAYER M4 ;
        RECT  104.004 25.2 104.088 25.224 ;
    END
  END a[439]
  PIN a[43]
    DIRECTION INPUT ;
    USE SIGNAL ;
    PORT
      LAYER M4 ;
        RECT  104.004 55.536 104.088 55.56 ;
    END
  END a[43]
  PIN a[440]
    DIRECTION INPUT ;
    USE SIGNAL ;
    PORT
      LAYER M4 ;
        RECT  104.004 25.296 104.088 25.32 ;
    END
  END a[440]
  PIN a[441]
    DIRECTION INPUT ;
    USE SIGNAL ;
    PORT
      LAYER M4 ;
        RECT  104.004 25.392 104.088 25.416 ;
    END
  END a[441]
  PIN a[442]
    DIRECTION INPUT ;
    USE SIGNAL ;
    PORT
      LAYER M4 ;
        RECT  104.004 25.488 104.088 25.512 ;
    END
  END a[442]
  PIN a[443]
    DIRECTION INPUT ;
    USE SIGNAL ;
    PORT
      LAYER M4 ;
        RECT  104.004 25.584 104.088 25.608 ;
    END
  END a[443]
  PIN a[444]
    DIRECTION INPUT ;
    USE SIGNAL ;
    PORT
      LAYER M4 ;
        RECT  104.004 25.68 104.088 25.704 ;
    END
  END a[444]
  PIN a[445]
    DIRECTION INPUT ;
    USE SIGNAL ;
    PORT
      LAYER M4 ;
        RECT  104.004 25.776 104.088 25.8 ;
    END
  END a[445]
  PIN a[446]
    DIRECTION INPUT ;
    USE SIGNAL ;
    PORT
      LAYER M4 ;
        RECT  104.004 25.872 104.088 25.896 ;
    END
  END a[446]
  PIN a[447]
    DIRECTION INPUT ;
    USE SIGNAL ;
    PORT
      LAYER M4 ;
        RECT  104.004 25.968 104.088 25.992 ;
    END
  END a[447]
  PIN a[448]
    DIRECTION INPUT ;
    USE SIGNAL ;
    PORT
      LAYER M4 ;
        RECT  104.004 32.208 104.088 32.232 ;
    END
  END a[448]
  PIN a[449]
    DIRECTION INPUT ;
    USE SIGNAL ;
    PORT
      LAYER M4 ;
        RECT  104.004 32.304 104.088 32.328 ;
    END
  END a[449]
  PIN a[44]
    DIRECTION INPUT ;
    USE SIGNAL ;
    PORT
      LAYER M4 ;
        RECT  104.004 55.632 104.088 55.656 ;
    END
  END a[44]
  PIN a[450]
    DIRECTION INPUT ;
    USE SIGNAL ;
    PORT
      LAYER M4 ;
        RECT  104.004 32.4 104.088 32.424 ;
    END
  END a[450]
  PIN a[451]
    DIRECTION INPUT ;
    USE SIGNAL ;
    PORT
      LAYER M4 ;
        RECT  104.004 32.496 104.088 32.52 ;
    END
  END a[451]
  PIN a[452]
    DIRECTION INPUT ;
    USE SIGNAL ;
    PORT
      LAYER M4 ;
        RECT  104.004 32.592 104.088 32.616 ;
    END
  END a[452]
  PIN a[453]
    DIRECTION INPUT ;
    USE SIGNAL ;
    PORT
      LAYER M4 ;
        RECT  104.004 32.688 104.088 32.712 ;
    END
  END a[453]
  PIN a[454]
    DIRECTION INPUT ;
    USE SIGNAL ;
    PORT
      LAYER M4 ;
        RECT  104.004 32.784 104.088 32.808 ;
    END
  END a[454]
  PIN a[455]
    DIRECTION INPUT ;
    USE SIGNAL ;
    PORT
      LAYER M4 ;
        RECT  104.004 32.88 104.088 32.904 ;
    END
  END a[455]
  PIN a[456]
    DIRECTION INPUT ;
    USE SIGNAL ;
    PORT
      LAYER M4 ;
        RECT  104.004 32.976 104.088 33 ;
    END
  END a[456]
  PIN a[457]
    DIRECTION INPUT ;
    USE SIGNAL ;
    PORT
      LAYER M4 ;
        RECT  104.004 33.072 104.088 33.096 ;
    END
  END a[457]
  PIN a[458]
    DIRECTION INPUT ;
    USE SIGNAL ;
    PORT
      LAYER M4 ;
        RECT  104.004 33.168 104.088 33.192 ;
    END
  END a[458]
  PIN a[459]
    DIRECTION INPUT ;
    USE SIGNAL ;
    PORT
      LAYER M4 ;
        RECT  104.004 33.264 104.088 33.288 ;
    END
  END a[459]
  PIN a[45]
    DIRECTION INPUT ;
    USE SIGNAL ;
    PORT
      LAYER M4 ;
        RECT  104.004 55.728 104.088 55.752 ;
    END
  END a[45]
  PIN a[460]
    DIRECTION INPUT ;
    USE SIGNAL ;
    PORT
      LAYER M4 ;
        RECT  104.004 33.36 104.088 33.384 ;
    END
  END a[460]
  PIN a[461]
    DIRECTION INPUT ;
    USE SIGNAL ;
    PORT
      LAYER M4 ;
        RECT  104.004 33.456 104.088 33.48 ;
    END
  END a[461]
  PIN a[462]
    DIRECTION INPUT ;
    USE SIGNAL ;
    PORT
      LAYER M4 ;
        RECT  104.004 33.552 104.088 33.576 ;
    END
  END a[462]
  PIN a[463]
    DIRECTION INPUT ;
    USE SIGNAL ;
    PORT
      LAYER M4 ;
        RECT  104.004 33.648 104.088 33.672 ;
    END
  END a[463]
  PIN a[464]
    DIRECTION INPUT ;
    USE SIGNAL ;
    PORT
      LAYER M4 ;
        RECT  104.004 33.744 104.088 33.768 ;
    END
  END a[464]
  PIN a[465]
    DIRECTION INPUT ;
    USE SIGNAL ;
    PORT
      LAYER M4 ;
        RECT  104.004 33.84 104.088 33.864 ;
    END
  END a[465]
  PIN a[466]
    DIRECTION INPUT ;
    USE SIGNAL ;
    PORT
      LAYER M4 ;
        RECT  104.004 33.936 104.088 33.96 ;
    END
  END a[466]
  PIN a[467]
    DIRECTION INPUT ;
    USE SIGNAL ;
    PORT
      LAYER M4 ;
        RECT  104.004 34.032 104.088 34.056 ;
    END
  END a[467]
  PIN a[468]
    DIRECTION INPUT ;
    USE SIGNAL ;
    PORT
      LAYER M4 ;
        RECT  104.004 34.128 104.088 34.152 ;
    END
  END a[468]
  PIN a[469]
    DIRECTION INPUT ;
    USE SIGNAL ;
    PORT
      LAYER M4 ;
        RECT  104.004 34.224 104.088 34.248 ;
    END
  END a[469]
  PIN a[46]
    DIRECTION INPUT ;
    USE SIGNAL ;
    PORT
      LAYER M4 ;
        RECT  104.004 55.824 104.088 55.848 ;
    END
  END a[46]
  PIN a[470]
    DIRECTION INPUT ;
    USE SIGNAL ;
    PORT
      LAYER M4 ;
        RECT  104.004 34.32 104.088 34.344 ;
    END
  END a[470]
  PIN a[471]
    DIRECTION INPUT ;
    USE SIGNAL ;
    PORT
      LAYER M4 ;
        RECT  104.004 34.416 104.088 34.44 ;
    END
  END a[471]
  PIN a[472]
    DIRECTION INPUT ;
    USE SIGNAL ;
    PORT
      LAYER M4 ;
        RECT  104.004 34.512 104.088 34.536 ;
    END
  END a[472]
  PIN a[473]
    DIRECTION INPUT ;
    USE SIGNAL ;
    PORT
      LAYER M4 ;
        RECT  104.004 34.608 104.088 34.632 ;
    END
  END a[473]
  PIN a[474]
    DIRECTION INPUT ;
    USE SIGNAL ;
    PORT
      LAYER M4 ;
        RECT  104.004 34.704 104.088 34.728 ;
    END
  END a[474]
  PIN a[475]
    DIRECTION INPUT ;
    USE SIGNAL ;
    PORT
      LAYER M4 ;
        RECT  104.004 34.8 104.088 34.824 ;
    END
  END a[475]
  PIN a[476]
    DIRECTION INPUT ;
    USE SIGNAL ;
    PORT
      LAYER M4 ;
        RECT  104.004 34.896 104.088 34.92 ;
    END
  END a[476]
  PIN a[477]
    DIRECTION INPUT ;
    USE SIGNAL ;
    PORT
      LAYER M4 ;
        RECT  104.004 34.992 104.088 35.016 ;
    END
  END a[477]
  PIN a[478]
    DIRECTION INPUT ;
    USE SIGNAL ;
    PORT
      LAYER M4 ;
        RECT  104.004 35.088 104.088 35.112 ;
    END
  END a[478]
  PIN a[479]
    DIRECTION INPUT ;
    USE SIGNAL ;
    PORT
      LAYER M4 ;
        RECT  104.004 35.184 104.088 35.208 ;
    END
  END a[479]
  PIN a[47]
    DIRECTION INPUT ;
    USE SIGNAL ;
    PORT
      LAYER M4 ;
        RECT  104.004 55.92 104.088 55.944 ;
    END
  END a[47]
  PIN a[480]
    DIRECTION INPUT ;
    USE SIGNAL ;
    PORT
      LAYER M4 ;
        RECT  104.004 35.28 104.088 35.304 ;
    END
  END a[480]
  PIN a[481]
    DIRECTION INPUT ;
    USE SIGNAL ;
    PORT
      LAYER M4 ;
        RECT  104.004 35.376 104.088 35.4 ;
    END
  END a[481]
  PIN a[482]
    DIRECTION INPUT ;
    USE SIGNAL ;
    PORT
      LAYER M4 ;
        RECT  104.004 35.472 104.088 35.496 ;
    END
  END a[482]
  PIN a[483]
    DIRECTION INPUT ;
    USE SIGNAL ;
    PORT
      LAYER M4 ;
        RECT  104.004 35.568 104.088 35.592 ;
    END
  END a[483]
  PIN a[484]
    DIRECTION INPUT ;
    USE SIGNAL ;
    PORT
      LAYER M4 ;
        RECT  104.004 35.664 104.088 35.688 ;
    END
  END a[484]
  PIN a[485]
    DIRECTION INPUT ;
    USE SIGNAL ;
    PORT
      LAYER M4 ;
        RECT  104.004 35.76 104.088 35.784 ;
    END
  END a[485]
  PIN a[486]
    DIRECTION INPUT ;
    USE SIGNAL ;
    PORT
      LAYER M4 ;
        RECT  104.004 35.856 104.088 35.88 ;
    END
  END a[486]
  PIN a[487]
    DIRECTION INPUT ;
    USE SIGNAL ;
    PORT
      LAYER M4 ;
        RECT  104.004 35.952 104.088 35.976 ;
    END
  END a[487]
  PIN a[488]
    DIRECTION INPUT ;
    USE SIGNAL ;
    PORT
      LAYER M4 ;
        RECT  104.004 36.048 104.088 36.072 ;
    END
  END a[488]
  PIN a[489]
    DIRECTION INPUT ;
    USE SIGNAL ;
    PORT
      LAYER M4 ;
        RECT  104.004 36.144 104.088 36.168 ;
    END
  END a[489]
  PIN a[48]
    DIRECTION INPUT ;
    USE SIGNAL ;
    PORT
      LAYER M4 ;
        RECT  104.004 56.016 104.088 56.04 ;
    END
  END a[48]
  PIN a[490]
    DIRECTION INPUT ;
    USE SIGNAL ;
    PORT
      LAYER M4 ;
        RECT  104.004 36.24 104.088 36.264 ;
    END
  END a[490]
  PIN a[491]
    DIRECTION INPUT ;
    USE SIGNAL ;
    PORT
      LAYER M4 ;
        RECT  104.004 36.336 104.088 36.36 ;
    END
  END a[491]
  PIN a[492]
    DIRECTION INPUT ;
    USE SIGNAL ;
    PORT
      LAYER M4 ;
        RECT  104.004 36.432 104.088 36.456 ;
    END
  END a[492]
  PIN a[493]
    DIRECTION INPUT ;
    USE SIGNAL ;
    PORT
      LAYER M4 ;
        RECT  104.004 36.528 104.088 36.552 ;
    END
  END a[493]
  PIN a[494]
    DIRECTION INPUT ;
    USE SIGNAL ;
    PORT
      LAYER M4 ;
        RECT  104.004 36.624 104.088 36.648 ;
    END
  END a[494]
  PIN a[495]
    DIRECTION INPUT ;
    USE SIGNAL ;
    PORT
      LAYER M4 ;
        RECT  104.004 36.72 104.088 36.744 ;
    END
  END a[495]
  PIN a[496]
    DIRECTION INPUT ;
    USE SIGNAL ;
    PORT
      LAYER M4 ;
        RECT  104.004 36.816 104.088 36.84 ;
    END
  END a[496]
  PIN a[497]
    DIRECTION INPUT ;
    USE SIGNAL ;
    PORT
      LAYER M4 ;
        RECT  104.004 36.912 104.088 36.936 ;
    END
  END a[497]
  PIN a[498]
    DIRECTION INPUT ;
    USE SIGNAL ;
    PORT
      LAYER M4 ;
        RECT  104.004 37.008 104.088 37.032 ;
    END
  END a[498]
  PIN a[499]
    DIRECTION INPUT ;
    USE SIGNAL ;
    PORT
      LAYER M4 ;
        RECT  104.004 37.104 104.088 37.128 ;
    END
  END a[499]
  PIN a[49]
    DIRECTION INPUT ;
    USE SIGNAL ;
    PORT
      LAYER M4 ;
        RECT  104.004 56.112 104.088 56.136 ;
    END
  END a[49]
  PIN a[4]
    DIRECTION INPUT ;
    USE SIGNAL ;
    PORT
      LAYER M4 ;
        RECT  104.004 42.576 104.088 42.6 ;
    END
  END a[4]
  PIN a[500]
    DIRECTION INPUT ;
    USE SIGNAL ;
    PORT
      LAYER M4 ;
        RECT  104.004 37.2 104.088 37.224 ;
    END
  END a[500]
  PIN a[501]
    DIRECTION INPUT ;
    USE SIGNAL ;
    PORT
      LAYER M4 ;
        RECT  104.004 37.296 104.088 37.32 ;
    END
  END a[501]
  PIN a[502]
    DIRECTION INPUT ;
    USE SIGNAL ;
    PORT
      LAYER M4 ;
        RECT  104.004 37.392 104.088 37.416 ;
    END
  END a[502]
  PIN a[503]
    DIRECTION INPUT ;
    USE SIGNAL ;
    PORT
      LAYER M4 ;
        RECT  104.004 37.488 104.088 37.512 ;
    END
  END a[503]
  PIN a[504]
    DIRECTION INPUT ;
    USE SIGNAL ;
    PORT
      LAYER M4 ;
        RECT  104.004 37.584 104.088 37.608 ;
    END
  END a[504]
  PIN a[505]
    DIRECTION INPUT ;
    USE SIGNAL ;
    PORT
      LAYER M4 ;
        RECT  104.004 37.68 104.088 37.704 ;
    END
  END a[505]
  PIN a[506]
    DIRECTION INPUT ;
    USE SIGNAL ;
    PORT
      LAYER M4 ;
        RECT  104.004 37.776 104.088 37.8 ;
    END
  END a[506]
  PIN a[507]
    DIRECTION INPUT ;
    USE SIGNAL ;
    PORT
      LAYER M4 ;
        RECT  104.004 37.872 104.088 37.896 ;
    END
  END a[507]
  PIN a[508]
    DIRECTION INPUT ;
    USE SIGNAL ;
    PORT
      LAYER M4 ;
        RECT  104.004 37.968 104.088 37.992 ;
    END
  END a[508]
  PIN a[509]
    DIRECTION INPUT ;
    USE SIGNAL ;
    PORT
      LAYER M4 ;
        RECT  104.004 38.064 104.088 38.088 ;
    END
  END a[509]
  PIN a[50]
    DIRECTION INPUT ;
    USE SIGNAL ;
    PORT
      LAYER M4 ;
        RECT  104.004 56.208 104.088 56.232 ;
    END
  END a[50]
  PIN a[510]
    DIRECTION INPUT ;
    USE SIGNAL ;
    PORT
      LAYER M4 ;
        RECT  104.004 38.16 104.088 38.184 ;
    END
  END a[510]
  PIN a[511]
    DIRECTION INPUT ;
    USE SIGNAL ;
    PORT
      LAYER M4 ;
        RECT  104.004 38.256 104.088 38.28 ;
    END
  END a[511]
  PIN a[512]
    DIRECTION INPUT ;
    USE SIGNAL ;
    PORT
      LAYER M4 ;
        RECT  104.004 29.136 104.088 29.16 ;
    END
  END a[512]
  PIN a[513]
    DIRECTION INPUT ;
    USE SIGNAL ;
    PORT
      LAYER M4 ;
        RECT  104.004 29.232 104.088 29.256 ;
    END
  END a[513]
  PIN a[514]
    DIRECTION INPUT ;
    USE SIGNAL ;
    PORT
      LAYER M4 ;
        RECT  104.004 29.328 104.088 29.352 ;
    END
  END a[514]
  PIN a[515]
    DIRECTION INPUT ;
    USE SIGNAL ;
    PORT
      LAYER M4 ;
        RECT  104.004 29.424 104.088 29.448 ;
    END
  END a[515]
  PIN a[516]
    DIRECTION INPUT ;
    USE SIGNAL ;
    PORT
      LAYER M4 ;
        RECT  104.004 29.52 104.088 29.544 ;
    END
  END a[516]
  PIN a[517]
    DIRECTION INPUT ;
    USE SIGNAL ;
    PORT
      LAYER M4 ;
        RECT  104.004 29.616 104.088 29.64 ;
    END
  END a[517]
  PIN a[518]
    DIRECTION INPUT ;
    USE SIGNAL ;
    PORT
      LAYER M4 ;
        RECT  104.004 29.712 104.088 29.736 ;
    END
  END a[518]
  PIN a[519]
    DIRECTION INPUT ;
    USE SIGNAL ;
    PORT
      LAYER M4 ;
        RECT  104.004 29.808 104.088 29.832 ;
    END
  END a[519]
  PIN a[51]
    DIRECTION INPUT ;
    USE SIGNAL ;
    PORT
      LAYER M4 ;
        RECT  104.004 56.304 104.088 56.328 ;
    END
  END a[51]
  PIN a[520]
    DIRECTION INPUT ;
    USE SIGNAL ;
    PORT
      LAYER M4 ;
        RECT  104.004 29.904 104.088 29.928 ;
    END
  END a[520]
  PIN a[521]
    DIRECTION INPUT ;
    USE SIGNAL ;
    PORT
      LAYER M4 ;
        RECT  104.004 30 104.088 30.024 ;
    END
  END a[521]
  PIN a[522]
    DIRECTION INPUT ;
    USE SIGNAL ;
    PORT
      LAYER M4 ;
        RECT  104.004 30.096 104.088 30.12 ;
    END
  END a[522]
  PIN a[523]
    DIRECTION INPUT ;
    USE SIGNAL ;
    PORT
      LAYER M4 ;
        RECT  104.004 30.192 104.088 30.216 ;
    END
  END a[523]
  PIN a[524]
    DIRECTION INPUT ;
    USE SIGNAL ;
    PORT
      LAYER M4 ;
        RECT  104.004 30.288 104.088 30.312 ;
    END
  END a[524]
  PIN a[525]
    DIRECTION INPUT ;
    USE SIGNAL ;
    PORT
      LAYER M4 ;
        RECT  104.004 30.384 104.088 30.408 ;
    END
  END a[525]
  PIN a[526]
    DIRECTION INPUT ;
    USE SIGNAL ;
    PORT
      LAYER M4 ;
        RECT  104.004 30.48 104.088 30.504 ;
    END
  END a[526]
  PIN a[527]
    DIRECTION INPUT ;
    USE SIGNAL ;
    PORT
      LAYER M4 ;
        RECT  104.004 30.576 104.088 30.6 ;
    END
  END a[527]
  PIN a[528]
    DIRECTION INPUT ;
    USE SIGNAL ;
    PORT
      LAYER M4 ;
        RECT  104.004 30.672 104.088 30.696 ;
    END
  END a[528]
  PIN a[529]
    DIRECTION INPUT ;
    USE SIGNAL ;
    PORT
      LAYER M4 ;
        RECT  104.004 30.768 104.088 30.792 ;
    END
  END a[529]
  PIN a[52]
    DIRECTION INPUT ;
    USE SIGNAL ;
    PORT
      LAYER M4 ;
        RECT  104.004 56.4 104.088 56.424 ;
    END
  END a[52]
  PIN a[530]
    DIRECTION INPUT ;
    USE SIGNAL ;
    PORT
      LAYER M4 ;
        RECT  104.004 30.864 104.088 30.888 ;
    END
  END a[530]
  PIN a[531]
    DIRECTION INPUT ;
    USE SIGNAL ;
    PORT
      LAYER M4 ;
        RECT  104.004 30.96 104.088 30.984 ;
    END
  END a[531]
  PIN a[532]
    DIRECTION INPUT ;
    USE SIGNAL ;
    PORT
      LAYER M4 ;
        RECT  104.004 31.056 104.088 31.08 ;
    END
  END a[532]
  PIN a[533]
    DIRECTION INPUT ;
    USE SIGNAL ;
    PORT
      LAYER M4 ;
        RECT  104.004 31.152 104.088 31.176 ;
    END
  END a[533]
  PIN a[534]
    DIRECTION INPUT ;
    USE SIGNAL ;
    PORT
      LAYER M4 ;
        RECT  104.004 31.248 104.088 31.272 ;
    END
  END a[534]
  PIN a[535]
    DIRECTION INPUT ;
    USE SIGNAL ;
    PORT
      LAYER M4 ;
        RECT  104.004 31.344 104.088 31.368 ;
    END
  END a[535]
  PIN a[536]
    DIRECTION INPUT ;
    USE SIGNAL ;
    PORT
      LAYER M4 ;
        RECT  104.004 31.44 104.088 31.464 ;
    END
  END a[536]
  PIN a[537]
    DIRECTION INPUT ;
    USE SIGNAL ;
    PORT
      LAYER M4 ;
        RECT  104.004 31.536 104.088 31.56 ;
    END
  END a[537]
  PIN a[538]
    DIRECTION INPUT ;
    USE SIGNAL ;
    PORT
      LAYER M4 ;
        RECT  104.004 31.632 104.088 31.656 ;
    END
  END a[538]
  PIN a[539]
    DIRECTION INPUT ;
    USE SIGNAL ;
    PORT
      LAYER M4 ;
        RECT  104.004 31.728 104.088 31.752 ;
    END
  END a[539]
  PIN a[53]
    DIRECTION INPUT ;
    USE SIGNAL ;
    PORT
      LAYER M4 ;
        RECT  104.004 56.496 104.088 56.52 ;
    END
  END a[53]
  PIN a[540]
    DIRECTION INPUT ;
    USE SIGNAL ;
    PORT
      LAYER M4 ;
        RECT  104.004 31.824 104.088 31.848 ;
    END
  END a[540]
  PIN a[541]
    DIRECTION INPUT ;
    USE SIGNAL ;
    PORT
      LAYER M4 ;
        RECT  104.004 31.92 104.088 31.944 ;
    END
  END a[541]
  PIN a[542]
    DIRECTION INPUT ;
    USE SIGNAL ;
    PORT
      LAYER M4 ;
        RECT  104.004 32.016 104.088 32.04 ;
    END
  END a[542]
  PIN a[543]
    DIRECTION INPUT ;
    USE SIGNAL ;
    PORT
      LAYER M4 ;
        RECT  104.004 32.112 104.088 32.136 ;
    END
  END a[543]
  PIN a[544]
    DIRECTION INPUT ;
    USE SIGNAL ;
    PORT
      LAYER M4 ;
        RECT  104.004 26.064 104.088 26.088 ;
    END
  END a[544]
  PIN a[545]
    DIRECTION INPUT ;
    USE SIGNAL ;
    PORT
      LAYER M4 ;
        RECT  104.004 26.16 104.088 26.184 ;
    END
  END a[545]
  PIN a[546]
    DIRECTION INPUT ;
    USE SIGNAL ;
    PORT
      LAYER M4 ;
        RECT  104.004 26.256 104.088 26.28 ;
    END
  END a[546]
  PIN a[547]
    DIRECTION INPUT ;
    USE SIGNAL ;
    PORT
      LAYER M4 ;
        RECT  104.004 26.352 104.088 26.376 ;
    END
  END a[547]
  PIN a[548]
    DIRECTION INPUT ;
    USE SIGNAL ;
    PORT
      LAYER M4 ;
        RECT  104.004 26.448 104.088 26.472 ;
    END
  END a[548]
  PIN a[549]
    DIRECTION INPUT ;
    USE SIGNAL ;
    PORT
      LAYER M4 ;
        RECT  104.004 26.544 104.088 26.568 ;
    END
  END a[549]
  PIN a[54]
    DIRECTION INPUT ;
    USE SIGNAL ;
    PORT
      LAYER M4 ;
        RECT  104.004 56.592 104.088 56.616 ;
    END
  END a[54]
  PIN a[550]
    DIRECTION INPUT ;
    USE SIGNAL ;
    PORT
      LAYER M4 ;
        RECT  104.004 26.64 104.088 26.664 ;
    END
  END a[550]
  PIN a[551]
    DIRECTION INPUT ;
    USE SIGNAL ;
    PORT
      LAYER M4 ;
        RECT  104.004 26.736 104.088 26.76 ;
    END
  END a[551]
  PIN a[552]
    DIRECTION INPUT ;
    USE SIGNAL ;
    PORT
      LAYER M4 ;
        RECT  104.004 26.832 104.088 26.856 ;
    END
  END a[552]
  PIN a[553]
    DIRECTION INPUT ;
    USE SIGNAL ;
    PORT
      LAYER M4 ;
        RECT  104.004 26.928 104.088 26.952 ;
    END
  END a[553]
  PIN a[554]
    DIRECTION INPUT ;
    USE SIGNAL ;
    PORT
      LAYER M4 ;
        RECT  104.004 27.024 104.088 27.048 ;
    END
  END a[554]
  PIN a[555]
    DIRECTION INPUT ;
    USE SIGNAL ;
    PORT
      LAYER M4 ;
        RECT  104.004 27.12 104.088 27.144 ;
    END
  END a[555]
  PIN a[556]
    DIRECTION INPUT ;
    USE SIGNAL ;
    PORT
      LAYER M4 ;
        RECT  104.004 27.216 104.088 27.24 ;
    END
  END a[556]
  PIN a[557]
    DIRECTION INPUT ;
    USE SIGNAL ;
    PORT
      LAYER M4 ;
        RECT  104.004 27.312 104.088 27.336 ;
    END
  END a[557]
  PIN a[558]
    DIRECTION INPUT ;
    USE SIGNAL ;
    PORT
      LAYER M4 ;
        RECT  104.004 27.408 104.088 27.432 ;
    END
  END a[558]
  PIN a[559]
    DIRECTION INPUT ;
    USE SIGNAL ;
    PORT
      LAYER M4 ;
        RECT  104.004 27.504 104.088 27.528 ;
    END
  END a[559]
  PIN a[55]
    DIRECTION INPUT ;
    USE SIGNAL ;
    PORT
      LAYER M4 ;
        RECT  104.004 56.688 104.088 56.712 ;
    END
  END a[55]
  PIN a[560]
    DIRECTION INPUT ;
    USE SIGNAL ;
    PORT
      LAYER M4 ;
        RECT  104.004 27.6 104.088 27.624 ;
    END
  END a[560]
  PIN a[561]
    DIRECTION INPUT ;
    USE SIGNAL ;
    PORT
      LAYER M4 ;
        RECT  104.004 27.696 104.088 27.72 ;
    END
  END a[561]
  PIN a[562]
    DIRECTION INPUT ;
    USE SIGNAL ;
    PORT
      LAYER M4 ;
        RECT  104.004 27.792 104.088 27.816 ;
    END
  END a[562]
  PIN a[563]
    DIRECTION INPUT ;
    USE SIGNAL ;
    PORT
      LAYER M4 ;
        RECT  104.004 27.888 104.088 27.912 ;
    END
  END a[563]
  PIN a[564]
    DIRECTION INPUT ;
    USE SIGNAL ;
    PORT
      LAYER M4 ;
        RECT  104.004 27.984 104.088 28.008 ;
    END
  END a[564]
  PIN a[565]
    DIRECTION INPUT ;
    USE SIGNAL ;
    PORT
      LAYER M4 ;
        RECT  104.004 28.08 104.088 28.104 ;
    END
  END a[565]
  PIN a[566]
    DIRECTION INPUT ;
    USE SIGNAL ;
    PORT
      LAYER M4 ;
        RECT  104.004 28.176 104.088 28.2 ;
    END
  END a[566]
  PIN a[567]
    DIRECTION INPUT ;
    USE SIGNAL ;
    PORT
      LAYER M4 ;
        RECT  104.004 28.272 104.088 28.296 ;
    END
  END a[567]
  PIN a[568]
    DIRECTION INPUT ;
    USE SIGNAL ;
    PORT
      LAYER M4 ;
        RECT  104.004 28.368 104.088 28.392 ;
    END
  END a[568]
  PIN a[569]
    DIRECTION INPUT ;
    USE SIGNAL ;
    PORT
      LAYER M4 ;
        RECT  104.004 28.464 104.088 28.488 ;
    END
  END a[569]
  PIN a[56]
    DIRECTION INPUT ;
    USE SIGNAL ;
    PORT
      LAYER M4 ;
        RECT  104.004 56.784 104.088 56.808 ;
    END
  END a[56]
  PIN a[570]
    DIRECTION INPUT ;
    USE SIGNAL ;
    PORT
      LAYER M4 ;
        RECT  104.004 28.56 104.088 28.584 ;
    END
  END a[570]
  PIN a[571]
    DIRECTION INPUT ;
    USE SIGNAL ;
    PORT
      LAYER M4 ;
        RECT  104.004 28.656 104.088 28.68 ;
    END
  END a[571]
  PIN a[572]
    DIRECTION INPUT ;
    USE SIGNAL ;
    PORT
      LAYER M4 ;
        RECT  104.004 28.752 104.088 28.776 ;
    END
  END a[572]
  PIN a[573]
    DIRECTION INPUT ;
    USE SIGNAL ;
    PORT
      LAYER M4 ;
        RECT  104.004 28.848 104.088 28.872 ;
    END
  END a[573]
  PIN a[574]
    DIRECTION INPUT ;
    USE SIGNAL ;
    PORT
      LAYER M4 ;
        RECT  104.004 28.944 104.088 28.968 ;
    END
  END a[574]
  PIN a[575]
    DIRECTION INPUT ;
    USE SIGNAL ;
    PORT
      LAYER M4 ;
        RECT  104.004 29.04 104.088 29.064 ;
    END
  END a[575]
  PIN a[576]
    DIRECTION INPUT ;
    USE SIGNAL ;
    PORT
      LAYER M4 ;
        RECT  104.004 77.52 104.088 77.544 ;
    END
  END a[576]
  PIN a[577]
    DIRECTION INPUT ;
    USE SIGNAL ;
    PORT
      LAYER M4 ;
        RECT  104.004 77.616 104.088 77.64 ;
    END
  END a[577]
  PIN a[578]
    DIRECTION INPUT ;
    USE SIGNAL ;
    PORT
      LAYER M4 ;
        RECT  104.004 77.712 104.088 77.736 ;
    END
  END a[578]
  PIN a[579]
    DIRECTION INPUT ;
    USE SIGNAL ;
    PORT
      LAYER M4 ;
        RECT  104.004 77.808 104.088 77.832 ;
    END
  END a[579]
  PIN a[57]
    DIRECTION INPUT ;
    USE SIGNAL ;
    PORT
      LAYER M4 ;
        RECT  104.004 56.88 104.088 56.904 ;
    END
  END a[57]
  PIN a[580]
    DIRECTION INPUT ;
    USE SIGNAL ;
    PORT
      LAYER M4 ;
        RECT  104.004 77.904 104.088 77.928 ;
    END
  END a[580]
  PIN a[581]
    DIRECTION INPUT ;
    USE SIGNAL ;
    PORT
      LAYER M4 ;
        RECT  104.004 78 104.088 78.024 ;
    END
  END a[581]
  PIN a[582]
    DIRECTION INPUT ;
    USE SIGNAL ;
    PORT
      LAYER M4 ;
        RECT  104.004 78.096 104.088 78.12 ;
    END
  END a[582]
  PIN a[583]
    DIRECTION INPUT ;
    USE SIGNAL ;
    PORT
      LAYER M4 ;
        RECT  104.004 78.192 104.088 78.216 ;
    END
  END a[583]
  PIN a[584]
    DIRECTION INPUT ;
    USE SIGNAL ;
    PORT
      LAYER M4 ;
        RECT  104.004 78.288 104.088 78.312 ;
    END
  END a[584]
  PIN a[585]
    DIRECTION INPUT ;
    USE SIGNAL ;
    PORT
      LAYER M4 ;
        RECT  104.004 78.384 104.088 78.408 ;
    END
  END a[585]
  PIN a[586]
    DIRECTION INPUT ;
    USE SIGNAL ;
    PORT
      LAYER M4 ;
        RECT  104.004 78.48 104.088 78.504 ;
    END
  END a[586]
  PIN a[587]
    DIRECTION INPUT ;
    USE SIGNAL ;
    PORT
      LAYER M4 ;
        RECT  104.004 78.576 104.088 78.6 ;
    END
  END a[587]
  PIN a[588]
    DIRECTION INPUT ;
    USE SIGNAL ;
    PORT
      LAYER M4 ;
        RECT  104.004 78.672 104.088 78.696 ;
    END
  END a[588]
  PIN a[589]
    DIRECTION INPUT ;
    USE SIGNAL ;
    PORT
      LAYER M4 ;
        RECT  104.004 78.768 104.088 78.792 ;
    END
  END a[589]
  PIN a[58]
    DIRECTION INPUT ;
    USE SIGNAL ;
    PORT
      LAYER M4 ;
        RECT  104.004 56.976 104.088 57 ;
    END
  END a[58]
  PIN a[590]
    DIRECTION INPUT ;
    USE SIGNAL ;
    PORT
      LAYER M4 ;
        RECT  104.004 78.864 104.088 78.888 ;
    END
  END a[590]
  PIN a[591]
    DIRECTION INPUT ;
    USE SIGNAL ;
    PORT
      LAYER M4 ;
        RECT  104.004 78.96 104.088 78.984 ;
    END
  END a[591]
  PIN a[592]
    DIRECTION INPUT ;
    USE SIGNAL ;
    PORT
      LAYER M4 ;
        RECT  104.004 79.056 104.088 79.08 ;
    END
  END a[592]
  PIN a[593]
    DIRECTION INPUT ;
    USE SIGNAL ;
    PORT
      LAYER M4 ;
        RECT  104.004 79.152 104.088 79.176 ;
    END
  END a[593]
  PIN a[594]
    DIRECTION INPUT ;
    USE SIGNAL ;
    PORT
      LAYER M4 ;
        RECT  104.004 79.248 104.088 79.272 ;
    END
  END a[594]
  PIN a[595]
    DIRECTION INPUT ;
    USE SIGNAL ;
    PORT
      LAYER M4 ;
        RECT  104.004 79.344 104.088 79.368 ;
    END
  END a[595]
  PIN a[596]
    DIRECTION INPUT ;
    USE SIGNAL ;
    PORT
      LAYER M4 ;
        RECT  104.004 79.44 104.088 79.464 ;
    END
  END a[596]
  PIN a[597]
    DIRECTION INPUT ;
    USE SIGNAL ;
    PORT
      LAYER M4 ;
        RECT  104.004 79.536 104.088 79.56 ;
    END
  END a[597]
  PIN a[598]
    DIRECTION INPUT ;
    USE SIGNAL ;
    PORT
      LAYER M4 ;
        RECT  104.004 79.632 104.088 79.656 ;
    END
  END a[598]
  PIN a[599]
    DIRECTION INPUT ;
    USE SIGNAL ;
    PORT
      LAYER M4 ;
        RECT  104.004 79.728 104.088 79.752 ;
    END
  END a[599]
  PIN a[59]
    DIRECTION INPUT ;
    USE SIGNAL ;
    PORT
      LAYER M4 ;
        RECT  104.004 57.072 104.088 57.096 ;
    END
  END a[59]
  PIN a[5]
    DIRECTION INPUT ;
    USE SIGNAL ;
    PORT
      LAYER M4 ;
        RECT  104.004 42.672 104.088 42.696 ;
    END
  END a[5]
  PIN a[60]
    DIRECTION INPUT ;
    USE SIGNAL ;
    PORT
      LAYER M4 ;
        RECT  104.004 57.168 104.088 57.192 ;
    END
  END a[60]
  PIN a[61]
    DIRECTION INPUT ;
    USE SIGNAL ;
    PORT
      LAYER M4 ;
        RECT  104.004 57.264 104.088 57.288 ;
    END
  END a[61]
  PIN a[62]
    DIRECTION INPUT ;
    USE SIGNAL ;
    PORT
      LAYER M4 ;
        RECT  104.004 57.36 104.088 57.384 ;
    END
  END a[62]
  PIN a[63]
    DIRECTION INPUT ;
    USE SIGNAL ;
    PORT
      LAYER M4 ;
        RECT  104.004 57.456 104.088 57.48 ;
    END
  END a[63]
  PIN a[64]
    DIRECTION INPUT ;
    USE SIGNAL ;
    PORT
      LAYER M4 ;
        RECT  104.004 39.12 104.088 39.144 ;
    END
  END a[64]
  PIN a[65]
    DIRECTION INPUT ;
    USE SIGNAL ;
    PORT
      LAYER M4 ;
        RECT  104.004 39.216 104.088 39.24 ;
    END
  END a[65]
  PIN a[66]
    DIRECTION INPUT ;
    USE SIGNAL ;
    PORT
      LAYER M4 ;
        RECT  104.004 39.312 104.088 39.336 ;
    END
  END a[66]
  PIN a[67]
    DIRECTION INPUT ;
    USE SIGNAL ;
    PORT
      LAYER M4 ;
        RECT  104.004 39.408 104.088 39.432 ;
    END
  END a[67]
  PIN a[68]
    DIRECTION INPUT ;
    USE SIGNAL ;
    PORT
      LAYER M4 ;
        RECT  104.004 39.504 104.088 39.528 ;
    END
  END a[68]
  PIN a[69]
    DIRECTION INPUT ;
    USE SIGNAL ;
    PORT
      LAYER M4 ;
        RECT  104.004 39.6 104.088 39.624 ;
    END
  END a[69]
  PIN a[6]
    DIRECTION INPUT ;
    USE SIGNAL ;
    PORT
      LAYER M4 ;
        RECT  104.004 42.768 104.088 42.792 ;
    END
  END a[6]
  PIN a[70]
    DIRECTION INPUT ;
    USE SIGNAL ;
    PORT
      LAYER M4 ;
        RECT  104.004 39.696 104.088 39.72 ;
    END
  END a[70]
  PIN a[71]
    DIRECTION INPUT ;
    USE SIGNAL ;
    PORT
      LAYER M4 ;
        RECT  104.004 39.792 104.088 39.816 ;
    END
  END a[71]
  PIN a[72]
    DIRECTION INPUT ;
    USE SIGNAL ;
    PORT
      LAYER M4 ;
        RECT  104.004 39.888 104.088 39.912 ;
    END
  END a[72]
  PIN a[73]
    DIRECTION INPUT ;
    USE SIGNAL ;
    PORT
      LAYER M4 ;
        RECT  104.004 39.984 104.088 40.008 ;
    END
  END a[73]
  PIN a[74]
    DIRECTION INPUT ;
    USE SIGNAL ;
    PORT
      LAYER M4 ;
        RECT  104.004 40.08 104.088 40.104 ;
    END
  END a[74]
  PIN a[75]
    DIRECTION INPUT ;
    USE SIGNAL ;
    PORT
      LAYER M4 ;
        RECT  104.004 40.176 104.088 40.2 ;
    END
  END a[75]
  PIN a[76]
    DIRECTION INPUT ;
    USE SIGNAL ;
    PORT
      LAYER M4 ;
        RECT  104.004 40.272 104.088 40.296 ;
    END
  END a[76]
  PIN a[77]
    DIRECTION INPUT ;
    USE SIGNAL ;
    PORT
      LAYER M4 ;
        RECT  104.004 40.368 104.088 40.392 ;
    END
  END a[77]
  PIN a[78]
    DIRECTION INPUT ;
    USE SIGNAL ;
    PORT
      LAYER M4 ;
        RECT  104.004 40.464 104.088 40.488 ;
    END
  END a[78]
  PIN a[79]
    DIRECTION INPUT ;
    USE SIGNAL ;
    PORT
      LAYER M4 ;
        RECT  104.004 40.56 104.088 40.584 ;
    END
  END a[79]
  PIN a[7]
    DIRECTION INPUT ;
    USE SIGNAL ;
    PORT
      LAYER M4 ;
        RECT  104.004 42.864 104.088 42.888 ;
    END
  END a[7]
  PIN a[80]
    DIRECTION INPUT ;
    USE SIGNAL ;
    PORT
      LAYER M4 ;
        RECT  104.004 40.656 104.088 40.68 ;
    END
  END a[80]
  PIN a[81]
    DIRECTION INPUT ;
    USE SIGNAL ;
    PORT
      LAYER M4 ;
        RECT  104.004 40.752 104.088 40.776 ;
    END
  END a[81]
  PIN a[82]
    DIRECTION INPUT ;
    USE SIGNAL ;
    PORT
      LAYER M4 ;
        RECT  104.004 40.848 104.088 40.872 ;
    END
  END a[82]
  PIN a[83]
    DIRECTION INPUT ;
    USE SIGNAL ;
    PORT
      LAYER M4 ;
        RECT  104.004 40.944 104.088 40.968 ;
    END
  END a[83]
  PIN a[84]
    DIRECTION INPUT ;
    USE SIGNAL ;
    PORT
      LAYER M4 ;
        RECT  104.004 41.04 104.088 41.064 ;
    END
  END a[84]
  PIN a[85]
    DIRECTION INPUT ;
    USE SIGNAL ;
    PORT
      LAYER M4 ;
        RECT  104.004 41.136 104.088 41.16 ;
    END
  END a[85]
  PIN a[86]
    DIRECTION INPUT ;
    USE SIGNAL ;
    PORT
      LAYER M4 ;
        RECT  104.004 41.232 104.088 41.256 ;
    END
  END a[86]
  PIN a[87]
    DIRECTION INPUT ;
    USE SIGNAL ;
    PORT
      LAYER M4 ;
        RECT  104.004 41.328 104.088 41.352 ;
    END
  END a[87]
  PIN a[88]
    DIRECTION INPUT ;
    USE SIGNAL ;
    PORT
      LAYER M4 ;
        RECT  104.004 41.424 104.088 41.448 ;
    END
  END a[88]
  PIN a[89]
    DIRECTION INPUT ;
    USE SIGNAL ;
    PORT
      LAYER M4 ;
        RECT  104.004 41.52 104.088 41.544 ;
    END
  END a[89]
  PIN a[8]
    DIRECTION INPUT ;
    USE SIGNAL ;
    PORT
      LAYER M4 ;
        RECT  104.004 42.96 104.088 42.984 ;
    END
  END a[8]
  PIN a[90]
    DIRECTION INPUT ;
    USE SIGNAL ;
    PORT
      LAYER M4 ;
        RECT  104.004 41.616 104.088 41.64 ;
    END
  END a[90]
  PIN a[91]
    DIRECTION INPUT ;
    USE SIGNAL ;
    PORT
      LAYER M4 ;
        RECT  104.004 41.712 104.088 41.736 ;
    END
  END a[91]
  PIN a[92]
    DIRECTION INPUT ;
    USE SIGNAL ;
    PORT
      LAYER M4 ;
        RECT  104.004 41.808 104.088 41.832 ;
    END
  END a[92]
  PIN a[93]
    DIRECTION INPUT ;
    USE SIGNAL ;
    PORT
      LAYER M4 ;
        RECT  104.004 41.904 104.088 41.928 ;
    END
  END a[93]
  PIN a[94]
    DIRECTION INPUT ;
    USE SIGNAL ;
    PORT
      LAYER M4 ;
        RECT  104.004 42 104.088 42.024 ;
    END
  END a[94]
  PIN a[95]
    DIRECTION INPUT ;
    USE SIGNAL ;
    PORT
      LAYER M4 ;
        RECT  104.004 42.096 104.088 42.12 ;
    END
  END a[95]
  PIN a[96]
    DIRECTION INPUT ;
    USE SIGNAL ;
    PORT
      LAYER M4 ;
        RECT  104.004 48.336 104.088 48.36 ;
    END
  END a[96]
  PIN a[97]
    DIRECTION INPUT ;
    USE SIGNAL ;
    PORT
      LAYER M4 ;
        RECT  104.004 48.432 104.088 48.456 ;
    END
  END a[97]
  PIN a[98]
    DIRECTION INPUT ;
    USE SIGNAL ;
    PORT
      LAYER M4 ;
        RECT  104.004 48.528 104.088 48.552 ;
    END
  END a[98]
  PIN a[99]
    DIRECTION INPUT ;
    USE SIGNAL ;
    PORT
      LAYER M4 ;
        RECT  104.004 48.624 104.088 48.648 ;
    END
  END a[99]
  PIN a[9]
    DIRECTION INPUT ;
    USE SIGNAL ;
    PORT
      LAYER M4 ;
        RECT  104.004 43.056 104.088 43.08 ;
    END
  END a[9]
  PIN b[0]
    DIRECTION OUTPUT ;
    USE SIGNAL ;
    PORT
      LAYER M3 ;
        RECT  48.852 105.779 48.87 105.816 ;
    END
  END b[0]
  PIN b[100]
    DIRECTION OUTPUT ;
    USE SIGNAL ;
    PORT
      LAYER M3 ;
        RECT  53.748 105.779 53.766 105.816 ;
    END
  END b[100]
  PIN b[101]
    DIRECTION OUTPUT ;
    USE SIGNAL ;
    PORT
      LAYER M3 ;
        RECT  53.82 105.779 53.838 105.816 ;
    END
  END b[101]
  PIN b[102]
    DIRECTION OUTPUT ;
    USE SIGNAL ;
    PORT
      LAYER M3 ;
        RECT  53.892 105.779 53.91 105.816 ;
    END
  END b[102]
  PIN b[103]
    DIRECTION OUTPUT ;
    USE SIGNAL ;
    PORT
      LAYER M3 ;
        RECT  53.964 105.779 53.982 105.816 ;
    END
  END b[103]
  PIN b[104]
    DIRECTION OUTPUT ;
    USE SIGNAL ;
    PORT
      LAYER M3 ;
        RECT  54.036 105.779 54.054 105.816 ;
    END
  END b[104]
  PIN b[105]
    DIRECTION OUTPUT ;
    USE SIGNAL ;
    PORT
      LAYER M3 ;
        RECT  54.108 105.779 54.126 105.816 ;
    END
  END b[105]
  PIN b[106]
    DIRECTION OUTPUT ;
    USE SIGNAL ;
    PORT
      LAYER M3 ;
        RECT  54.18 105.779 54.198 105.816 ;
    END
  END b[106]
  PIN b[107]
    DIRECTION OUTPUT ;
    USE SIGNAL ;
    PORT
      LAYER M3 ;
        RECT  54.252 105.779 54.27 105.816 ;
    END
  END b[107]
  PIN b[108]
    DIRECTION OUTPUT ;
    USE SIGNAL ;
    PORT
      LAYER M3 ;
        RECT  54.324 105.779 54.342 105.816 ;
    END
  END b[108]
  PIN b[109]
    DIRECTION OUTPUT ;
    USE SIGNAL ;
    PORT
      LAYER M3 ;
        RECT  54.396 105.779 54.414 105.816 ;
    END
  END b[109]
  PIN b[10]
    DIRECTION OUTPUT ;
    USE SIGNAL ;
    PORT
      LAYER M3 ;
        RECT  49.572 105.779 49.59 105.816 ;
    END
  END b[10]
  PIN b[110]
    DIRECTION OUTPUT ;
    USE SIGNAL ;
    PORT
      LAYER M3 ;
        RECT  54.468 105.779 54.486 105.816 ;
    END
  END b[110]
  PIN b[111]
    DIRECTION OUTPUT ;
    USE SIGNAL ;
    PORT
      LAYER M3 ;
        RECT  54.54 105.779 54.558 105.816 ;
    END
  END b[111]
  PIN b[112]
    DIRECTION OUTPUT ;
    USE SIGNAL ;
    PORT
      LAYER M3 ;
        RECT  54.612 105.779 54.63 105.816 ;
    END
  END b[112]
  PIN b[113]
    DIRECTION OUTPUT ;
    USE SIGNAL ;
    PORT
      LAYER M3 ;
        RECT  54.684 105.779 54.702 105.816 ;
    END
  END b[113]
  PIN b[114]
    DIRECTION OUTPUT ;
    USE SIGNAL ;
    PORT
      LAYER M3 ;
        RECT  54.756 105.779 54.774 105.816 ;
    END
  END b[114]
  PIN b[115]
    DIRECTION OUTPUT ;
    USE SIGNAL ;
    PORT
      LAYER M3 ;
        RECT  54.828 105.779 54.846 105.816 ;
    END
  END b[115]
  PIN b[116]
    DIRECTION OUTPUT ;
    USE SIGNAL ;
    PORT
      LAYER M3 ;
        RECT  54.9 105.779 54.918 105.816 ;
    END
  END b[116]
  PIN b[117]
    DIRECTION OUTPUT ;
    USE SIGNAL ;
    PORT
      LAYER M3 ;
        RECT  54.972 105.779 54.99 105.816 ;
    END
  END b[117]
  PIN b[118]
    DIRECTION OUTPUT ;
    USE SIGNAL ;
    PORT
      LAYER M3 ;
        RECT  55.044 105.779 55.062 105.816 ;
    END
  END b[118]
  PIN b[119]
    DIRECTION OUTPUT ;
    USE SIGNAL ;
    PORT
      LAYER M3 ;
        RECT  55.116 105.779 55.134 105.816 ;
    END
  END b[119]
  PIN b[11]
    DIRECTION OUTPUT ;
    USE SIGNAL ;
    PORT
      LAYER M3 ;
        RECT  49.644 105.779 49.662 105.816 ;
    END
  END b[11]
  PIN b[120]
    DIRECTION OUTPUT ;
    USE SIGNAL ;
    PORT
      LAYER M3 ;
        RECT  55.188 105.779 55.206 105.816 ;
    END
  END b[120]
  PIN b[121]
    DIRECTION OUTPUT ;
    USE SIGNAL ;
    PORT
      LAYER M3 ;
        RECT  55.26 105.779 55.278 105.816 ;
    END
  END b[121]
  PIN b[122]
    DIRECTION OUTPUT ;
    USE SIGNAL ;
    PORT
      LAYER M3 ;
        RECT  55.332 105.779 55.35 105.816 ;
    END
  END b[122]
  PIN b[123]
    DIRECTION OUTPUT ;
    USE SIGNAL ;
    PORT
      LAYER M3 ;
        RECT  55.404 105.779 55.422 105.816 ;
    END
  END b[123]
  PIN b[124]
    DIRECTION OUTPUT ;
    USE SIGNAL ;
    PORT
      LAYER M3 ;
        RECT  55.476 105.779 55.494 105.816 ;
    END
  END b[124]
  PIN b[125]
    DIRECTION OUTPUT ;
    USE SIGNAL ;
    PORT
      LAYER M3 ;
        RECT  55.548 105.779 55.566 105.816 ;
    END
  END b[125]
  PIN b[126]
    DIRECTION OUTPUT ;
    USE SIGNAL ;
    PORT
      LAYER M3 ;
        RECT  55.62 105.779 55.638 105.816 ;
    END
  END b[126]
  PIN b[127]
    DIRECTION OUTPUT ;
    USE SIGNAL ;
    PORT
      LAYER M3 ;
        RECT  55.692 105.779 55.71 105.816 ;
    END
  END b[127]
  PIN b[128]
    DIRECTION OUTPUT ;
    USE SIGNAL ;
    PORT
      LAYER M3 ;
        RECT  55.764 105.779 55.782 105.816 ;
    END
  END b[128]
  PIN b[129]
    DIRECTION OUTPUT ;
    USE SIGNAL ;
    PORT
      LAYER M3 ;
        RECT  55.836 105.779 55.854 105.816 ;
    END
  END b[129]
  PIN b[12]
    DIRECTION OUTPUT ;
    USE SIGNAL ;
    PORT
      LAYER M3 ;
        RECT  49.716 105.779 49.734 105.816 ;
    END
  END b[12]
  PIN b[130]
    DIRECTION OUTPUT ;
    USE SIGNAL ;
    PORT
      LAYER M3 ;
        RECT  55.908 105.779 55.926 105.816 ;
    END
  END b[130]
  PIN b[131]
    DIRECTION OUTPUT ;
    USE SIGNAL ;
    PORT
      LAYER M3 ;
        RECT  55.98 105.779 55.998 105.816 ;
    END
  END b[131]
  PIN b[132]
    DIRECTION OUTPUT ;
    USE SIGNAL ;
    PORT
      LAYER M3 ;
        RECT  56.052 105.779 56.07 105.816 ;
    END
  END b[132]
  PIN b[133]
    DIRECTION OUTPUT ;
    USE SIGNAL ;
    PORT
      LAYER M3 ;
        RECT  56.124 105.779 56.142 105.816 ;
    END
  END b[133]
  PIN b[134]
    DIRECTION OUTPUT ;
    USE SIGNAL ;
    PORT
      LAYER M3 ;
        RECT  56.196 105.779 56.214 105.816 ;
    END
  END b[134]
  PIN b[135]
    DIRECTION OUTPUT ;
    USE SIGNAL ;
    PORT
      LAYER M3 ;
        RECT  56.268 105.779 56.286 105.816 ;
    END
  END b[135]
  PIN b[136]
    DIRECTION OUTPUT ;
    USE SIGNAL ;
    PORT
      LAYER M3 ;
        RECT  56.34 105.779 56.358 105.816 ;
    END
  END b[136]
  PIN b[137]
    DIRECTION OUTPUT ;
    USE SIGNAL ;
    PORT
      LAYER M3 ;
        RECT  56.412 105.779 56.43 105.816 ;
    END
  END b[137]
  PIN b[138]
    DIRECTION OUTPUT ;
    USE SIGNAL ;
    PORT
      LAYER M3 ;
        RECT  56.484 105.779 56.502 105.816 ;
    END
  END b[138]
  PIN b[139]
    DIRECTION OUTPUT ;
    USE SIGNAL ;
    PORT
      LAYER M3 ;
        RECT  56.556 105.779 56.574 105.816 ;
    END
  END b[139]
  PIN b[13]
    DIRECTION OUTPUT ;
    USE SIGNAL ;
    PORT
      LAYER M3 ;
        RECT  49.788 105.779 49.806 105.816 ;
    END
  END b[13]
  PIN b[140]
    DIRECTION OUTPUT ;
    USE SIGNAL ;
    PORT
      LAYER M3 ;
        RECT  56.628 105.779 56.646 105.816 ;
    END
  END b[140]
  PIN b[141]
    DIRECTION OUTPUT ;
    USE SIGNAL ;
    PORT
      LAYER M3 ;
        RECT  56.7 105.779 56.718 105.816 ;
    END
  END b[141]
  PIN b[142]
    DIRECTION OUTPUT ;
    USE SIGNAL ;
    PORT
      LAYER M3 ;
        RECT  56.772 105.779 56.79 105.816 ;
    END
  END b[142]
  PIN b[143]
    DIRECTION OUTPUT ;
    USE SIGNAL ;
    PORT
      LAYER M3 ;
        RECT  56.844 105.779 56.862 105.816 ;
    END
  END b[143]
  PIN b[144]
    DIRECTION OUTPUT ;
    USE SIGNAL ;
    PORT
      LAYER M3 ;
        RECT  56.916 105.779 56.934 105.816 ;
    END
  END b[144]
  PIN b[145]
    DIRECTION OUTPUT ;
    USE SIGNAL ;
    PORT
      LAYER M3 ;
        RECT  56.988 105.779 57.006 105.816 ;
    END
  END b[145]
  PIN b[146]
    DIRECTION OUTPUT ;
    USE SIGNAL ;
    PORT
      LAYER M3 ;
        RECT  57.06 105.779 57.078 105.816 ;
    END
  END b[146]
  PIN b[147]
    DIRECTION OUTPUT ;
    USE SIGNAL ;
    PORT
      LAYER M3 ;
        RECT  57.132 105.779 57.15 105.816 ;
    END
  END b[147]
  PIN b[148]
    DIRECTION OUTPUT ;
    USE SIGNAL ;
    PORT
      LAYER M3 ;
        RECT  57.204 105.779 57.222 105.816 ;
    END
  END b[148]
  PIN b[149]
    DIRECTION OUTPUT ;
    USE SIGNAL ;
    PORT
      LAYER M3 ;
        RECT  57.276 105.779 57.294 105.816 ;
    END
  END b[149]
  PIN b[14]
    DIRECTION OUTPUT ;
    USE SIGNAL ;
    PORT
      LAYER M3 ;
        RECT  49.86 105.779 49.878 105.816 ;
    END
  END b[14]
  PIN b[150]
    DIRECTION OUTPUT ;
    USE SIGNAL ;
    PORT
      LAYER M3 ;
        RECT  57.348 105.779 57.366 105.816 ;
    END
  END b[150]
  PIN b[151]
    DIRECTION OUTPUT ;
    USE SIGNAL ;
    PORT
      LAYER M3 ;
        RECT  57.42 105.779 57.438 105.816 ;
    END
  END b[151]
  PIN b[152]
    DIRECTION OUTPUT ;
    USE SIGNAL ;
    PORT
      LAYER M3 ;
        RECT  57.492 105.779 57.51 105.816 ;
    END
  END b[152]
  PIN b[153]
    DIRECTION OUTPUT ;
    USE SIGNAL ;
    PORT
      LAYER M3 ;
        RECT  57.564 105.779 57.582 105.816 ;
    END
  END b[153]
  PIN b[154]
    DIRECTION OUTPUT ;
    USE SIGNAL ;
    PORT
      LAYER M3 ;
        RECT  57.636 105.779 57.654 105.816 ;
    END
  END b[154]
  PIN b[155]
    DIRECTION OUTPUT ;
    USE SIGNAL ;
    PORT
      LAYER M3 ;
        RECT  57.708 105.779 57.726 105.816 ;
    END
  END b[155]
  PIN b[156]
    DIRECTION OUTPUT ;
    USE SIGNAL ;
    PORT
      LAYER M3 ;
        RECT  57.78 105.779 57.798 105.816 ;
    END
  END b[156]
  PIN b[157]
    DIRECTION OUTPUT ;
    USE SIGNAL ;
    PORT
      LAYER M3 ;
        RECT  57.852 105.779 57.87 105.816 ;
    END
  END b[157]
  PIN b[158]
    DIRECTION OUTPUT ;
    USE SIGNAL ;
    PORT
      LAYER M3 ;
        RECT  57.924 105.779 57.942 105.816 ;
    END
  END b[158]
  PIN b[159]
    DIRECTION OUTPUT ;
    USE SIGNAL ;
    PORT
      LAYER M3 ;
        RECT  57.996 105.779 58.014 105.816 ;
    END
  END b[159]
  PIN b[15]
    DIRECTION OUTPUT ;
    USE SIGNAL ;
    PORT
      LAYER M3 ;
        RECT  49.932 105.779 49.95 105.816 ;
    END
  END b[15]
  PIN b[160]
    DIRECTION OUTPUT ;
    USE SIGNAL ;
    PORT
      LAYER M3 ;
        RECT  51.156 105.779 51.174 105.816 ;
    END
  END b[160]
  PIN b[161]
    DIRECTION OUTPUT ;
    USE SIGNAL ;
    PORT
      LAYER M3 ;
        RECT  51.228 105.779 51.246 105.816 ;
    END
  END b[161]
  PIN b[162]
    DIRECTION OUTPUT ;
    USE SIGNAL ;
    PORT
      LAYER M3 ;
        RECT  51.3 105.779 51.318 105.816 ;
    END
  END b[162]
  PIN b[163]
    DIRECTION OUTPUT ;
    USE SIGNAL ;
    PORT
      LAYER M3 ;
        RECT  51.372 105.779 51.39 105.816 ;
    END
  END b[163]
  PIN b[164]
    DIRECTION OUTPUT ;
    USE SIGNAL ;
    PORT
      LAYER M3 ;
        RECT  51.444 105.779 51.462 105.816 ;
    END
  END b[164]
  PIN b[165]
    DIRECTION OUTPUT ;
    USE SIGNAL ;
    PORT
      LAYER M3 ;
        RECT  51.516 105.779 51.534 105.816 ;
    END
  END b[165]
  PIN b[166]
    DIRECTION OUTPUT ;
    USE SIGNAL ;
    PORT
      LAYER M3 ;
        RECT  51.588 105.779 51.606 105.816 ;
    END
  END b[166]
  PIN b[167]
    DIRECTION OUTPUT ;
    USE SIGNAL ;
    PORT
      LAYER M3 ;
        RECT  51.66 105.779 51.678 105.816 ;
    END
  END b[167]
  PIN b[168]
    DIRECTION OUTPUT ;
    USE SIGNAL ;
    PORT
      LAYER M3 ;
        RECT  51.732 105.779 51.75 105.816 ;
    END
  END b[168]
  PIN b[169]
    DIRECTION OUTPUT ;
    USE SIGNAL ;
    PORT
      LAYER M3 ;
        RECT  51.804 105.779 51.822 105.816 ;
    END
  END b[169]
  PIN b[16]
    DIRECTION OUTPUT ;
    USE SIGNAL ;
    PORT
      LAYER M3 ;
        RECT  50.004 105.779 50.022 105.816 ;
    END
  END b[16]
  PIN b[170]
    DIRECTION OUTPUT ;
    USE SIGNAL ;
    PORT
      LAYER M3 ;
        RECT  51.876 105.779 51.894 105.816 ;
    END
  END b[170]
  PIN b[171]
    DIRECTION OUTPUT ;
    USE SIGNAL ;
    PORT
      LAYER M3 ;
        RECT  51.948 105.779 51.966 105.816 ;
    END
  END b[171]
  PIN b[172]
    DIRECTION OUTPUT ;
    USE SIGNAL ;
    PORT
      LAYER M3 ;
        RECT  52.02 105.779 52.038 105.816 ;
    END
  END b[172]
  PIN b[173]
    DIRECTION OUTPUT ;
    USE SIGNAL ;
    PORT
      LAYER M3 ;
        RECT  52.092 105.779 52.11 105.816 ;
    END
  END b[173]
  PIN b[174]
    DIRECTION OUTPUT ;
    USE SIGNAL ;
    PORT
      LAYER M3 ;
        RECT  52.164 105.779 52.182 105.816 ;
    END
  END b[174]
  PIN b[175]
    DIRECTION OUTPUT ;
    USE SIGNAL ;
    PORT
      LAYER M3 ;
        RECT  52.236 105.779 52.254 105.816 ;
    END
  END b[175]
  PIN b[176]
    DIRECTION OUTPUT ;
    USE SIGNAL ;
    PORT
      LAYER M3 ;
        RECT  52.308 105.779 52.326 105.816 ;
    END
  END b[176]
  PIN b[177]
    DIRECTION OUTPUT ;
    USE SIGNAL ;
    PORT
      LAYER M3 ;
        RECT  52.38 105.779 52.398 105.816 ;
    END
  END b[177]
  PIN b[178]
    DIRECTION OUTPUT ;
    USE SIGNAL ;
    PORT
      LAYER M3 ;
        RECT  52.452 105.779 52.47 105.816 ;
    END
  END b[178]
  PIN b[179]
    DIRECTION OUTPUT ;
    USE SIGNAL ;
    PORT
      LAYER M3 ;
        RECT  52.524 105.779 52.542 105.816 ;
    END
  END b[179]
  PIN b[17]
    DIRECTION OUTPUT ;
    USE SIGNAL ;
    PORT
      LAYER M3 ;
        RECT  50.076 105.779 50.094 105.816 ;
    END
  END b[17]
  PIN b[180]
    DIRECTION OUTPUT ;
    USE SIGNAL ;
    PORT
      LAYER M3 ;
        RECT  52.596 105.779 52.614 105.816 ;
    END
  END b[180]
  PIN b[181]
    DIRECTION OUTPUT ;
    USE SIGNAL ;
    PORT
      LAYER M3 ;
        RECT  52.668 105.779 52.686 105.816 ;
    END
  END b[181]
  PIN b[182]
    DIRECTION OUTPUT ;
    USE SIGNAL ;
    PORT
      LAYER M3 ;
        RECT  52.74 105.779 52.758 105.816 ;
    END
  END b[182]
  PIN b[183]
    DIRECTION OUTPUT ;
    USE SIGNAL ;
    PORT
      LAYER M3 ;
        RECT  52.812 105.779 52.83 105.816 ;
    END
  END b[183]
  PIN b[184]
    DIRECTION OUTPUT ;
    USE SIGNAL ;
    PORT
      LAYER M3 ;
        RECT  52.884 105.779 52.902 105.816 ;
    END
  END b[184]
  PIN b[185]
    DIRECTION OUTPUT ;
    USE SIGNAL ;
    PORT
      LAYER M3 ;
        RECT  52.956 105.779 52.974 105.816 ;
    END
  END b[185]
  PIN b[186]
    DIRECTION OUTPUT ;
    USE SIGNAL ;
    PORT
      LAYER M3 ;
        RECT  53.028 105.779 53.046 105.816 ;
    END
  END b[186]
  PIN b[187]
    DIRECTION OUTPUT ;
    USE SIGNAL ;
    PORT
      LAYER M3 ;
        RECT  53.1 105.779 53.118 105.816 ;
    END
  END b[187]
  PIN b[188]
    DIRECTION OUTPUT ;
    USE SIGNAL ;
    PORT
      LAYER M3 ;
        RECT  53.172 105.779 53.19 105.816 ;
    END
  END b[188]
  PIN b[189]
    DIRECTION OUTPUT ;
    USE SIGNAL ;
    PORT
      LAYER M3 ;
        RECT  53.244 105.779 53.262 105.816 ;
    END
  END b[189]
  PIN b[18]
    DIRECTION OUTPUT ;
    USE SIGNAL ;
    PORT
      LAYER M3 ;
        RECT  50.148 105.779 50.166 105.816 ;
    END
  END b[18]
  PIN b[190]
    DIRECTION OUTPUT ;
    USE SIGNAL ;
    PORT
      LAYER M3 ;
        RECT  53.316 105.779 53.334 105.816 ;
    END
  END b[190]
  PIN b[191]
    DIRECTION OUTPUT ;
    USE SIGNAL ;
    PORT
      LAYER M3 ;
        RECT  53.388 105.779 53.406 105.816 ;
    END
  END b[191]
  PIN b[192]
    DIRECTION OUTPUT ;
    USE SIGNAL ;
    PORT
      LAYER M5 ;
        RECT  55.824 105.732 55.848 105.816 ;
    END
  END b[192]
  PIN b[193]
    DIRECTION OUTPUT ;
    USE SIGNAL ;
    PORT
      LAYER M5 ;
        RECT  55.92 105.732 55.944 105.816 ;
    END
  END b[193]
  PIN b[194]
    DIRECTION OUTPUT ;
    USE SIGNAL ;
    PORT
      LAYER M5 ;
        RECT  56.016 105.732 56.04 105.816 ;
    END
  END b[194]
  PIN b[195]
    DIRECTION OUTPUT ;
    USE SIGNAL ;
    PORT
      LAYER M5 ;
        RECT  56.112 105.732 56.136 105.816 ;
    END
  END b[195]
  PIN b[196]
    DIRECTION OUTPUT ;
    USE SIGNAL ;
    PORT
      LAYER M5 ;
        RECT  56.208 105.732 56.232 105.816 ;
    END
  END b[196]
  PIN b[197]
    DIRECTION OUTPUT ;
    USE SIGNAL ;
    PORT
      LAYER M5 ;
        RECT  56.304 105.732 56.328 105.816 ;
    END
  END b[197]
  PIN b[198]
    DIRECTION OUTPUT ;
    USE SIGNAL ;
    PORT
      LAYER M5 ;
        RECT  56.4 105.732 56.424 105.816 ;
    END
  END b[198]
  PIN b[199]
    DIRECTION OUTPUT ;
    USE SIGNAL ;
    PORT
      LAYER M5 ;
        RECT  56.496 105.732 56.52 105.816 ;
    END
  END b[199]
  PIN b[19]
    DIRECTION OUTPUT ;
    USE SIGNAL ;
    PORT
      LAYER M3 ;
        RECT  50.22 105.779 50.238 105.816 ;
    END
  END b[19]
  PIN b[1]
    DIRECTION OUTPUT ;
    USE SIGNAL ;
    PORT
      LAYER M3 ;
        RECT  48.924 105.779 48.942 105.816 ;
    END
  END b[1]
  PIN b[200]
    DIRECTION OUTPUT ;
    USE SIGNAL ;
    PORT
      LAYER M5 ;
        RECT  56.592 105.732 56.616 105.816 ;
    END
  END b[200]
  PIN b[201]
    DIRECTION OUTPUT ;
    USE SIGNAL ;
    PORT
      LAYER M5 ;
        RECT  56.688 105.732 56.712 105.816 ;
    END
  END b[201]
  PIN b[202]
    DIRECTION OUTPUT ;
    USE SIGNAL ;
    PORT
      LAYER M5 ;
        RECT  56.784 105.732 56.808 105.816 ;
    END
  END b[202]
  PIN b[203]
    DIRECTION OUTPUT ;
    USE SIGNAL ;
    PORT
      LAYER M5 ;
        RECT  56.88 105.732 56.904 105.816 ;
    END
  END b[203]
  PIN b[204]
    DIRECTION OUTPUT ;
    USE SIGNAL ;
    PORT
      LAYER M5 ;
        RECT  56.976 105.732 57 105.816 ;
    END
  END b[204]
  PIN b[205]
    DIRECTION OUTPUT ;
    USE SIGNAL ;
    PORT
      LAYER M5 ;
        RECT  57.072 105.732 57.096 105.816 ;
    END
  END b[205]
  PIN b[206]
    DIRECTION OUTPUT ;
    USE SIGNAL ;
    PORT
      LAYER M5 ;
        RECT  57.168 105.732 57.192 105.816 ;
    END
  END b[206]
  PIN b[207]
    DIRECTION OUTPUT ;
    USE SIGNAL ;
    PORT
      LAYER M5 ;
        RECT  57.264 105.732 57.288 105.816 ;
    END
  END b[207]
  PIN b[208]
    DIRECTION OUTPUT ;
    USE SIGNAL ;
    PORT
      LAYER M5 ;
        RECT  57.36 105.732 57.384 105.816 ;
    END
  END b[208]
  PIN b[209]
    DIRECTION OUTPUT ;
    USE SIGNAL ;
    PORT
      LAYER M5 ;
        RECT  57.456 105.732 57.48 105.816 ;
    END
  END b[209]
  PIN b[20]
    DIRECTION OUTPUT ;
    USE SIGNAL ;
    PORT
      LAYER M3 ;
        RECT  50.292 105.779 50.31 105.816 ;
    END
  END b[20]
  PIN b[210]
    DIRECTION OUTPUT ;
    USE SIGNAL ;
    PORT
      LAYER M5 ;
        RECT  57.552 105.732 57.576 105.816 ;
    END
  END b[210]
  PIN b[211]
    DIRECTION OUTPUT ;
    USE SIGNAL ;
    PORT
      LAYER M5 ;
        RECT  57.648 105.732 57.672 105.816 ;
    END
  END b[211]
  PIN b[212]
    DIRECTION OUTPUT ;
    USE SIGNAL ;
    PORT
      LAYER M5 ;
        RECT  57.744 105.732 57.768 105.816 ;
    END
  END b[212]
  PIN b[213]
    DIRECTION OUTPUT ;
    USE SIGNAL ;
    PORT
      LAYER M5 ;
        RECT  57.84 105.732 57.864 105.816 ;
    END
  END b[213]
  PIN b[214]
    DIRECTION OUTPUT ;
    USE SIGNAL ;
    PORT
      LAYER M5 ;
        RECT  57.936 105.732 57.96 105.816 ;
    END
  END b[214]
  PIN b[215]
    DIRECTION OUTPUT ;
    USE SIGNAL ;
    PORT
      LAYER M5 ;
        RECT  58.032 105.732 58.056 105.816 ;
    END
  END b[215]
  PIN b[216]
    DIRECTION OUTPUT ;
    USE SIGNAL ;
    PORT
      LAYER M5 ;
        RECT  58.128 105.732 58.152 105.816 ;
    END
  END b[216]
  PIN b[217]
    DIRECTION OUTPUT ;
    USE SIGNAL ;
    PORT
      LAYER M5 ;
        RECT  58.224 105.732 58.248 105.816 ;
    END
  END b[217]
  PIN b[218]
    DIRECTION OUTPUT ;
    USE SIGNAL ;
    PORT
      LAYER M5 ;
        RECT  58.32 105.732 58.344 105.816 ;
    END
  END b[218]
  PIN b[219]
    DIRECTION OUTPUT ;
    USE SIGNAL ;
    PORT
      LAYER M5 ;
        RECT  58.416 105.732 58.44 105.816 ;
    END
  END b[219]
  PIN b[21]
    DIRECTION OUTPUT ;
    USE SIGNAL ;
    PORT
      LAYER M3 ;
        RECT  50.364 105.779 50.382 105.816 ;
    END
  END b[21]
  PIN b[220]
    DIRECTION OUTPUT ;
    USE SIGNAL ;
    PORT
      LAYER M5 ;
        RECT  58.512 105.732 58.536 105.816 ;
    END
  END b[220]
  PIN b[221]
    DIRECTION OUTPUT ;
    USE SIGNAL ;
    PORT
      LAYER M5 ;
        RECT  58.608 105.732 58.632 105.816 ;
    END
  END b[221]
  PIN b[222]
    DIRECTION OUTPUT ;
    USE SIGNAL ;
    PORT
      LAYER M5 ;
        RECT  58.704 105.732 58.728 105.816 ;
    END
  END b[222]
  PIN b[223]
    DIRECTION OUTPUT ;
    USE SIGNAL ;
    PORT
      LAYER M5 ;
        RECT  58.8 105.732 58.824 105.816 ;
    END
  END b[223]
  PIN b[224]
    DIRECTION OUTPUT ;
    USE SIGNAL ;
    PORT
      LAYER M5 ;
        RECT  49.68 105.732 49.704 105.816 ;
    END
  END b[224]
  PIN b[225]
    DIRECTION OUTPUT ;
    USE SIGNAL ;
    PORT
      LAYER M5 ;
        RECT  49.776 105.732 49.8 105.816 ;
    END
  END b[225]
  PIN b[226]
    DIRECTION OUTPUT ;
    USE SIGNAL ;
    PORT
      LAYER M5 ;
        RECT  49.872 105.732 49.896 105.816 ;
    END
  END b[226]
  PIN b[227]
    DIRECTION OUTPUT ;
    USE SIGNAL ;
    PORT
      LAYER M5 ;
        RECT  49.968 105.732 49.992 105.816 ;
    END
  END b[227]
  PIN b[228]
    DIRECTION OUTPUT ;
    USE SIGNAL ;
    PORT
      LAYER M5 ;
        RECT  50.064 105.732 50.088 105.816 ;
    END
  END b[228]
  PIN b[229]
    DIRECTION OUTPUT ;
    USE SIGNAL ;
    PORT
      LAYER M5 ;
        RECT  50.16 105.732 50.184 105.816 ;
    END
  END b[229]
  PIN b[22]
    DIRECTION OUTPUT ;
    USE SIGNAL ;
    PORT
      LAYER M3 ;
        RECT  50.436 105.779 50.454 105.816 ;
    END
  END b[22]
  PIN b[230]
    DIRECTION OUTPUT ;
    USE SIGNAL ;
    PORT
      LAYER M5 ;
        RECT  50.256 105.732 50.28 105.816 ;
    END
  END b[230]
  PIN b[231]
    DIRECTION OUTPUT ;
    USE SIGNAL ;
    PORT
      LAYER M5 ;
        RECT  50.352 105.732 50.376 105.816 ;
    END
  END b[231]
  PIN b[232]
    DIRECTION OUTPUT ;
    USE SIGNAL ;
    PORT
      LAYER M5 ;
        RECT  50.448 105.732 50.472 105.816 ;
    END
  END b[232]
  PIN b[233]
    DIRECTION OUTPUT ;
    USE SIGNAL ;
    PORT
      LAYER M5 ;
        RECT  50.544 105.732 50.568 105.816 ;
    END
  END b[233]
  PIN b[234]
    DIRECTION OUTPUT ;
    USE SIGNAL ;
    PORT
      LAYER M5 ;
        RECT  50.64 105.732 50.664 105.816 ;
    END
  END b[234]
  PIN b[235]
    DIRECTION OUTPUT ;
    USE SIGNAL ;
    PORT
      LAYER M5 ;
        RECT  50.736 105.732 50.76 105.816 ;
    END
  END b[235]
  PIN b[236]
    DIRECTION OUTPUT ;
    USE SIGNAL ;
    PORT
      LAYER M5 ;
        RECT  50.832 105.732 50.856 105.816 ;
    END
  END b[236]
  PIN b[237]
    DIRECTION OUTPUT ;
    USE SIGNAL ;
    PORT
      LAYER M5 ;
        RECT  50.928 105.732 50.952 105.816 ;
    END
  END b[237]
  PIN b[238]
    DIRECTION OUTPUT ;
    USE SIGNAL ;
    PORT
      LAYER M5 ;
        RECT  51.024 105.732 51.048 105.816 ;
    END
  END b[238]
  PIN b[239]
    DIRECTION OUTPUT ;
    USE SIGNAL ;
    PORT
      LAYER M5 ;
        RECT  51.12 105.732 51.144 105.816 ;
    END
  END b[239]
  PIN b[23]
    DIRECTION OUTPUT ;
    USE SIGNAL ;
    PORT
      LAYER M3 ;
        RECT  50.508 105.779 50.526 105.816 ;
    END
  END b[23]
  PIN b[240]
    DIRECTION OUTPUT ;
    USE SIGNAL ;
    PORT
      LAYER M5 ;
        RECT  51.216 105.732 51.24 105.816 ;
    END
  END b[240]
  PIN b[241]
    DIRECTION OUTPUT ;
    USE SIGNAL ;
    PORT
      LAYER M5 ;
        RECT  51.312 105.732 51.336 105.816 ;
    END
  END b[241]
  PIN b[242]
    DIRECTION OUTPUT ;
    USE SIGNAL ;
    PORT
      LAYER M5 ;
        RECT  51.408 105.732 51.432 105.816 ;
    END
  END b[242]
  PIN b[243]
    DIRECTION OUTPUT ;
    USE SIGNAL ;
    PORT
      LAYER M5 ;
        RECT  51.504 105.732 51.528 105.816 ;
    END
  END b[243]
  PIN b[244]
    DIRECTION OUTPUT ;
    USE SIGNAL ;
    PORT
      LAYER M5 ;
        RECT  51.6 105.732 51.624 105.816 ;
    END
  END b[244]
  PIN b[245]
    DIRECTION OUTPUT ;
    USE SIGNAL ;
    PORT
      LAYER M5 ;
        RECT  51.696 105.732 51.72 105.816 ;
    END
  END b[245]
  PIN b[246]
    DIRECTION OUTPUT ;
    USE SIGNAL ;
    PORT
      LAYER M5 ;
        RECT  51.792 105.732 51.816 105.816 ;
    END
  END b[246]
  PIN b[247]
    DIRECTION OUTPUT ;
    USE SIGNAL ;
    PORT
      LAYER M5 ;
        RECT  51.888 105.732 51.912 105.816 ;
    END
  END b[247]
  PIN b[248]
    DIRECTION OUTPUT ;
    USE SIGNAL ;
    PORT
      LAYER M5 ;
        RECT  51.984 105.732 52.008 105.816 ;
    END
  END b[248]
  PIN b[249]
    DIRECTION OUTPUT ;
    USE SIGNAL ;
    PORT
      LAYER M5 ;
        RECT  52.08 105.732 52.104 105.816 ;
    END
  END b[249]
  PIN b[24]
    DIRECTION OUTPUT ;
    USE SIGNAL ;
    PORT
      LAYER M3 ;
        RECT  50.58 105.779 50.598 105.816 ;
    END
  END b[24]
  PIN b[250]
    DIRECTION OUTPUT ;
    USE SIGNAL ;
    PORT
      LAYER M5 ;
        RECT  52.176 105.732 52.2 105.816 ;
    END
  END b[250]
  PIN b[251]
    DIRECTION OUTPUT ;
    USE SIGNAL ;
    PORT
      LAYER M5 ;
        RECT  52.272 105.732 52.296 105.816 ;
    END
  END b[251]
  PIN b[252]
    DIRECTION OUTPUT ;
    USE SIGNAL ;
    PORT
      LAYER M5 ;
        RECT  52.368 105.732 52.392 105.816 ;
    END
  END b[252]
  PIN b[253]
    DIRECTION OUTPUT ;
    USE SIGNAL ;
    PORT
      LAYER M5 ;
        RECT  52.464 105.732 52.488 105.816 ;
    END
  END b[253]
  PIN b[254]
    DIRECTION OUTPUT ;
    USE SIGNAL ;
    PORT
      LAYER M5 ;
        RECT  52.56 105.732 52.584 105.816 ;
    END
  END b[254]
  PIN b[255]
    DIRECTION OUTPUT ;
    USE SIGNAL ;
    PORT
      LAYER M5 ;
        RECT  52.656 105.732 52.68 105.816 ;
    END
  END b[255]
  PIN b[256]
    DIRECTION OUTPUT ;
    USE SIGNAL ;
    PORT
      LAYER M5 ;
        RECT  58.896 105.732 58.92 105.816 ;
    END
  END b[256]
  PIN b[257]
    DIRECTION OUTPUT ;
    USE SIGNAL ;
    PORT
      LAYER M5 ;
        RECT  58.992 105.732 59.016 105.816 ;
    END
  END b[257]
  PIN b[258]
    DIRECTION OUTPUT ;
    USE SIGNAL ;
    PORT
      LAYER M5 ;
        RECT  59.088 105.732 59.112 105.816 ;
    END
  END b[258]
  PIN b[259]
    DIRECTION OUTPUT ;
    USE SIGNAL ;
    PORT
      LAYER M5 ;
        RECT  59.184 105.732 59.208 105.816 ;
    END
  END b[259]
  PIN b[25]
    DIRECTION OUTPUT ;
    USE SIGNAL ;
    PORT
      LAYER M3 ;
        RECT  50.652 105.779 50.67 105.816 ;
    END
  END b[25]
  PIN b[260]
    DIRECTION OUTPUT ;
    USE SIGNAL ;
    PORT
      LAYER M5 ;
        RECT  59.28 105.732 59.304 105.816 ;
    END
  END b[260]
  PIN b[261]
    DIRECTION OUTPUT ;
    USE SIGNAL ;
    PORT
      LAYER M5 ;
        RECT  59.376 105.732 59.4 105.816 ;
    END
  END b[261]
  PIN b[262]
    DIRECTION OUTPUT ;
    USE SIGNAL ;
    PORT
      LAYER M5 ;
        RECT  59.472 105.732 59.496 105.816 ;
    END
  END b[262]
  PIN b[263]
    DIRECTION OUTPUT ;
    USE SIGNAL ;
    PORT
      LAYER M5 ;
        RECT  59.568 105.732 59.592 105.816 ;
    END
  END b[263]
  PIN b[264]
    DIRECTION OUTPUT ;
    USE SIGNAL ;
    PORT
      LAYER M5 ;
        RECT  59.664 105.732 59.688 105.816 ;
    END
  END b[264]
  PIN b[265]
    DIRECTION OUTPUT ;
    USE SIGNAL ;
    PORT
      LAYER M5 ;
        RECT  59.76 105.732 59.784 105.816 ;
    END
  END b[265]
  PIN b[266]
    DIRECTION OUTPUT ;
    USE SIGNAL ;
    PORT
      LAYER M5 ;
        RECT  59.856 105.732 59.88 105.816 ;
    END
  END b[266]
  PIN b[267]
    DIRECTION OUTPUT ;
    USE SIGNAL ;
    PORT
      LAYER M5 ;
        RECT  59.952 105.732 59.976 105.816 ;
    END
  END b[267]
  PIN b[268]
    DIRECTION OUTPUT ;
    USE SIGNAL ;
    PORT
      LAYER M5 ;
        RECT  60.048 105.732 60.072 105.816 ;
    END
  END b[268]
  PIN b[269]
    DIRECTION OUTPUT ;
    USE SIGNAL ;
    PORT
      LAYER M5 ;
        RECT  60.144 105.732 60.168 105.816 ;
    END
  END b[269]
  PIN b[26]
    DIRECTION OUTPUT ;
    USE SIGNAL ;
    PORT
      LAYER M3 ;
        RECT  50.724 105.779 50.742 105.816 ;
    END
  END b[26]
  PIN b[270]
    DIRECTION OUTPUT ;
    USE SIGNAL ;
    PORT
      LAYER M5 ;
        RECT  60.24 105.732 60.264 105.816 ;
    END
  END b[270]
  PIN b[271]
    DIRECTION OUTPUT ;
    USE SIGNAL ;
    PORT
      LAYER M5 ;
        RECT  60.336 105.732 60.36 105.816 ;
    END
  END b[271]
  PIN b[272]
    DIRECTION OUTPUT ;
    USE SIGNAL ;
    PORT
      LAYER M5 ;
        RECT  60.432 105.732 60.456 105.816 ;
    END
  END b[272]
  PIN b[273]
    DIRECTION OUTPUT ;
    USE SIGNAL ;
    PORT
      LAYER M5 ;
        RECT  60.528 105.732 60.552 105.816 ;
    END
  END b[273]
  PIN b[274]
    DIRECTION OUTPUT ;
    USE SIGNAL ;
    PORT
      LAYER M5 ;
        RECT  60.624 105.732 60.648 105.816 ;
    END
  END b[274]
  PIN b[275]
    DIRECTION OUTPUT ;
    USE SIGNAL ;
    PORT
      LAYER M5 ;
        RECT  60.72 105.732 60.744 105.816 ;
    END
  END b[275]
  PIN b[276]
    DIRECTION OUTPUT ;
    USE SIGNAL ;
    PORT
      LAYER M5 ;
        RECT  60.816 105.732 60.84 105.816 ;
    END
  END b[276]
  PIN b[277]
    DIRECTION OUTPUT ;
    USE SIGNAL ;
    PORT
      LAYER M5 ;
        RECT  60.912 105.732 60.936 105.816 ;
    END
  END b[277]
  PIN b[278]
    DIRECTION OUTPUT ;
    USE SIGNAL ;
    PORT
      LAYER M5 ;
        RECT  61.008 105.732 61.032 105.816 ;
    END
  END b[278]
  PIN b[279]
    DIRECTION OUTPUT ;
    USE SIGNAL ;
    PORT
      LAYER M5 ;
        RECT  61.104 105.732 61.128 105.816 ;
    END
  END b[279]
  PIN b[27]
    DIRECTION OUTPUT ;
    USE SIGNAL ;
    PORT
      LAYER M3 ;
        RECT  50.796 105.779 50.814 105.816 ;
    END
  END b[27]
  PIN b[280]
    DIRECTION OUTPUT ;
    USE SIGNAL ;
    PORT
      LAYER M5 ;
        RECT  61.2 105.732 61.224 105.816 ;
    END
  END b[280]
  PIN b[281]
    DIRECTION OUTPUT ;
    USE SIGNAL ;
    PORT
      LAYER M5 ;
        RECT  61.296 105.732 61.32 105.816 ;
    END
  END b[281]
  PIN b[282]
    DIRECTION OUTPUT ;
    USE SIGNAL ;
    PORT
      LAYER M5 ;
        RECT  61.392 105.732 61.416 105.816 ;
    END
  END b[282]
  PIN b[283]
    DIRECTION OUTPUT ;
    USE SIGNAL ;
    PORT
      LAYER M5 ;
        RECT  61.488 105.732 61.512 105.816 ;
    END
  END b[283]
  PIN b[284]
    DIRECTION OUTPUT ;
    USE SIGNAL ;
    PORT
      LAYER M5 ;
        RECT  61.584 105.732 61.608 105.816 ;
    END
  END b[284]
  PIN b[285]
    DIRECTION OUTPUT ;
    USE SIGNAL ;
    PORT
      LAYER M5 ;
        RECT  61.68 105.732 61.704 105.816 ;
    END
  END b[285]
  PIN b[286]
    DIRECTION OUTPUT ;
    USE SIGNAL ;
    PORT
      LAYER M5 ;
        RECT  61.776 105.732 61.8 105.816 ;
    END
  END b[286]
  PIN b[287]
    DIRECTION OUTPUT ;
    USE SIGNAL ;
    PORT
      LAYER M5 ;
        RECT  61.872 105.732 61.896 105.816 ;
    END
  END b[287]
  PIN b[288]
    DIRECTION OUTPUT ;
    USE SIGNAL ;
    PORT
      LAYER M5 ;
        RECT  52.752 105.732 52.776 105.816 ;
    END
  END b[288]
  PIN b[289]
    DIRECTION OUTPUT ;
    USE SIGNAL ;
    PORT
      LAYER M5 ;
        RECT  52.848 105.732 52.872 105.816 ;
    END
  END b[289]
  PIN b[28]
    DIRECTION OUTPUT ;
    USE SIGNAL ;
    PORT
      LAYER M3 ;
        RECT  50.868 105.779 50.886 105.816 ;
    END
  END b[28]
  PIN b[290]
    DIRECTION OUTPUT ;
    USE SIGNAL ;
    PORT
      LAYER M5 ;
        RECT  52.944 105.732 52.968 105.816 ;
    END
  END b[290]
  PIN b[291]
    DIRECTION OUTPUT ;
    USE SIGNAL ;
    PORT
      LAYER M5 ;
        RECT  53.04 105.732 53.064 105.816 ;
    END
  END b[291]
  PIN b[292]
    DIRECTION OUTPUT ;
    USE SIGNAL ;
    PORT
      LAYER M5 ;
        RECT  53.136 105.732 53.16 105.816 ;
    END
  END b[292]
  PIN b[293]
    DIRECTION OUTPUT ;
    USE SIGNAL ;
    PORT
      LAYER M5 ;
        RECT  53.232 105.732 53.256 105.816 ;
    END
  END b[293]
  PIN b[294]
    DIRECTION OUTPUT ;
    USE SIGNAL ;
    PORT
      LAYER M5 ;
        RECT  53.328 105.732 53.352 105.816 ;
    END
  END b[294]
  PIN b[295]
    DIRECTION OUTPUT ;
    USE SIGNAL ;
    PORT
      LAYER M5 ;
        RECT  53.424 105.732 53.448 105.816 ;
    END
  END b[295]
  PIN b[296]
    DIRECTION OUTPUT ;
    USE SIGNAL ;
    PORT
      LAYER M5 ;
        RECT  53.52 105.732 53.544 105.816 ;
    END
  END b[296]
  PIN b[297]
    DIRECTION OUTPUT ;
    USE SIGNAL ;
    PORT
      LAYER M5 ;
        RECT  53.616 105.732 53.64 105.816 ;
    END
  END b[297]
  PIN b[298]
    DIRECTION OUTPUT ;
    USE SIGNAL ;
    PORT
      LAYER M5 ;
        RECT  53.712 105.732 53.736 105.816 ;
    END
  END b[298]
  PIN b[299]
    DIRECTION OUTPUT ;
    USE SIGNAL ;
    PORT
      LAYER M5 ;
        RECT  53.808 105.732 53.832 105.816 ;
    END
  END b[299]
  PIN b[29]
    DIRECTION OUTPUT ;
    USE SIGNAL ;
    PORT
      LAYER M3 ;
        RECT  50.94 105.779 50.958 105.816 ;
    END
  END b[29]
  PIN b[2]
    DIRECTION OUTPUT ;
    USE SIGNAL ;
    PORT
      LAYER M3 ;
        RECT  48.996 105.779 49.014 105.816 ;
    END
  END b[2]
  PIN b[300]
    DIRECTION OUTPUT ;
    USE SIGNAL ;
    PORT
      LAYER M5 ;
        RECT  53.904 105.732 53.928 105.816 ;
    END
  END b[300]
  PIN b[301]
    DIRECTION OUTPUT ;
    USE SIGNAL ;
    PORT
      LAYER M5 ;
        RECT  54 105.732 54.024 105.816 ;
    END
  END b[301]
  PIN b[302]
    DIRECTION OUTPUT ;
    USE SIGNAL ;
    PORT
      LAYER M5 ;
        RECT  54.096 105.732 54.12 105.816 ;
    END
  END b[302]
  PIN b[303]
    DIRECTION OUTPUT ;
    USE SIGNAL ;
    PORT
      LAYER M5 ;
        RECT  54.192 105.732 54.216 105.816 ;
    END
  END b[303]
  PIN b[304]
    DIRECTION OUTPUT ;
    USE SIGNAL ;
    PORT
      LAYER M5 ;
        RECT  54.288 105.732 54.312 105.816 ;
    END
  END b[304]
  PIN b[305]
    DIRECTION OUTPUT ;
    USE SIGNAL ;
    PORT
      LAYER M5 ;
        RECT  54.384 105.732 54.408 105.816 ;
    END
  END b[305]
  PIN b[306]
    DIRECTION OUTPUT ;
    USE SIGNAL ;
    PORT
      LAYER M5 ;
        RECT  54.48 105.732 54.504 105.816 ;
    END
  END b[306]
  PIN b[307]
    DIRECTION OUTPUT ;
    USE SIGNAL ;
    PORT
      LAYER M5 ;
        RECT  54.576 105.732 54.6 105.816 ;
    END
  END b[307]
  PIN b[308]
    DIRECTION OUTPUT ;
    USE SIGNAL ;
    PORT
      LAYER M5 ;
        RECT  54.672 105.732 54.696 105.816 ;
    END
  END b[308]
  PIN b[309]
    DIRECTION OUTPUT ;
    USE SIGNAL ;
    PORT
      LAYER M5 ;
        RECT  54.768 105.732 54.792 105.816 ;
    END
  END b[309]
  PIN b[30]
    DIRECTION OUTPUT ;
    USE SIGNAL ;
    PORT
      LAYER M3 ;
        RECT  51.012 105.779 51.03 105.816 ;
    END
  END b[30]
  PIN b[310]
    DIRECTION OUTPUT ;
    USE SIGNAL ;
    PORT
      LAYER M5 ;
        RECT  54.864 105.732 54.888 105.816 ;
    END
  END b[310]
  PIN b[311]
    DIRECTION OUTPUT ;
    USE SIGNAL ;
    PORT
      LAYER M5 ;
        RECT  54.96 105.732 54.984 105.816 ;
    END
  END b[311]
  PIN b[312]
    DIRECTION OUTPUT ;
    USE SIGNAL ;
    PORT
      LAYER M5 ;
        RECT  55.056 105.732 55.08 105.816 ;
    END
  END b[312]
  PIN b[313]
    DIRECTION OUTPUT ;
    USE SIGNAL ;
    PORT
      LAYER M5 ;
        RECT  55.152 105.732 55.176 105.816 ;
    END
  END b[313]
  PIN b[314]
    DIRECTION OUTPUT ;
    USE SIGNAL ;
    PORT
      LAYER M5 ;
        RECT  55.248 105.732 55.272 105.816 ;
    END
  END b[314]
  PIN b[315]
    DIRECTION OUTPUT ;
    USE SIGNAL ;
    PORT
      LAYER M5 ;
        RECT  55.344 105.732 55.368 105.816 ;
    END
  END b[315]
  PIN b[316]
    DIRECTION OUTPUT ;
    USE SIGNAL ;
    PORT
      LAYER M5 ;
        RECT  55.44 105.732 55.464 105.816 ;
    END
  END b[316]
  PIN b[317]
    DIRECTION OUTPUT ;
    USE SIGNAL ;
    PORT
      LAYER M5 ;
        RECT  55.536 105.732 55.56 105.816 ;
    END
  END b[317]
  PIN b[318]
    DIRECTION OUTPUT ;
    USE SIGNAL ;
    PORT
      LAYER M5 ;
        RECT  55.632 105.732 55.656 105.816 ;
    END
  END b[318]
  PIN b[319]
    DIRECTION OUTPUT ;
    USE SIGNAL ;
    PORT
      LAYER M5 ;
        RECT  55.728 105.732 55.752 105.816 ;
    END
  END b[319]
  PIN b[31]
    DIRECTION OUTPUT ;
    USE SIGNAL ;
    PORT
      LAYER M3 ;
        RECT  51.084 105.779 51.102 105.816 ;
    END
  END b[31]
  PIN b[320]
    DIRECTION OUTPUT ;
    USE SIGNAL ;
    PORT
      LAYER M5 ;
        RECT  61.968 105.732 61.992 105.816 ;
    END
  END b[320]
  PIN b[321]
    DIRECTION OUTPUT ;
    USE SIGNAL ;
    PORT
      LAYER M5 ;
        RECT  62.064 105.732 62.088 105.816 ;
    END
  END b[321]
  PIN b[322]
    DIRECTION OUTPUT ;
    USE SIGNAL ;
    PORT
      LAYER M5 ;
        RECT  62.16 105.732 62.184 105.816 ;
    END
  END b[322]
  PIN b[323]
    DIRECTION OUTPUT ;
    USE SIGNAL ;
    PORT
      LAYER M5 ;
        RECT  62.256 105.732 62.28 105.816 ;
    END
  END b[323]
  PIN b[324]
    DIRECTION OUTPUT ;
    USE SIGNAL ;
    PORT
      LAYER M5 ;
        RECT  62.352 105.732 62.376 105.816 ;
    END
  END b[324]
  PIN b[325]
    DIRECTION OUTPUT ;
    USE SIGNAL ;
    PORT
      LAYER M5 ;
        RECT  62.448 105.732 62.472 105.816 ;
    END
  END b[325]
  PIN b[326]
    DIRECTION OUTPUT ;
    USE SIGNAL ;
    PORT
      LAYER M5 ;
        RECT  62.544 105.732 62.568 105.816 ;
    END
  END b[326]
  PIN b[327]
    DIRECTION OUTPUT ;
    USE SIGNAL ;
    PORT
      LAYER M5 ;
        RECT  62.64 105.732 62.664 105.816 ;
    END
  END b[327]
  PIN b[328]
    DIRECTION OUTPUT ;
    USE SIGNAL ;
    PORT
      LAYER M5 ;
        RECT  62.736 105.732 62.76 105.816 ;
    END
  END b[328]
  PIN b[329]
    DIRECTION OUTPUT ;
    USE SIGNAL ;
    PORT
      LAYER M5 ;
        RECT  62.832 105.732 62.856 105.816 ;
    END
  END b[329]
  PIN b[32]
    DIRECTION OUTPUT ;
    USE SIGNAL ;
    PORT
      LAYER M3 ;
        RECT  58.068 105.779 58.086 105.816 ;
    END
  END b[32]
  PIN b[330]
    DIRECTION OUTPUT ;
    USE SIGNAL ;
    PORT
      LAYER M5 ;
        RECT  62.928 105.732 62.952 105.816 ;
    END
  END b[330]
  PIN b[331]
    DIRECTION OUTPUT ;
    USE SIGNAL ;
    PORT
      LAYER M5 ;
        RECT  63.024 105.732 63.048 105.816 ;
    END
  END b[331]
  PIN b[332]
    DIRECTION OUTPUT ;
    USE SIGNAL ;
    PORT
      LAYER M5 ;
        RECT  63.12 105.732 63.144 105.816 ;
    END
  END b[332]
  PIN b[333]
    DIRECTION OUTPUT ;
    USE SIGNAL ;
    PORT
      LAYER M5 ;
        RECT  63.216 105.732 63.24 105.816 ;
    END
  END b[333]
  PIN b[334]
    DIRECTION OUTPUT ;
    USE SIGNAL ;
    PORT
      LAYER M5 ;
        RECT  63.312 105.732 63.336 105.816 ;
    END
  END b[334]
  PIN b[335]
    DIRECTION OUTPUT ;
    USE SIGNAL ;
    PORT
      LAYER M5 ;
        RECT  63.408 105.732 63.432 105.816 ;
    END
  END b[335]
  PIN b[336]
    DIRECTION OUTPUT ;
    USE SIGNAL ;
    PORT
      LAYER M5 ;
        RECT  63.504 105.732 63.528 105.816 ;
    END
  END b[336]
  PIN b[337]
    DIRECTION OUTPUT ;
    USE SIGNAL ;
    PORT
      LAYER M5 ;
        RECT  63.6 105.732 63.624 105.816 ;
    END
  END b[337]
  PIN b[338]
    DIRECTION OUTPUT ;
    USE SIGNAL ;
    PORT
      LAYER M5 ;
        RECT  63.696 105.732 63.72 105.816 ;
    END
  END b[338]
  PIN b[339]
    DIRECTION OUTPUT ;
    USE SIGNAL ;
    PORT
      LAYER M5 ;
        RECT  63.792 105.732 63.816 105.816 ;
    END
  END b[339]
  PIN b[33]
    DIRECTION OUTPUT ;
    USE SIGNAL ;
    PORT
      LAYER M3 ;
        RECT  58.14 105.779 58.158 105.816 ;
    END
  END b[33]
  PIN b[340]
    DIRECTION OUTPUT ;
    USE SIGNAL ;
    PORT
      LAYER M5 ;
        RECT  63.888 105.732 63.912 105.816 ;
    END
  END b[340]
  PIN b[341]
    DIRECTION OUTPUT ;
    USE SIGNAL ;
    PORT
      LAYER M5 ;
        RECT  63.984 105.732 64.008 105.816 ;
    END
  END b[341]
  PIN b[342]
    DIRECTION OUTPUT ;
    USE SIGNAL ;
    PORT
      LAYER M5 ;
        RECT  64.08 105.732 64.104 105.816 ;
    END
  END b[342]
  PIN b[343]
    DIRECTION OUTPUT ;
    USE SIGNAL ;
    PORT
      LAYER M5 ;
        RECT  64.176 105.732 64.2 105.816 ;
    END
  END b[343]
  PIN b[344]
    DIRECTION OUTPUT ;
    USE SIGNAL ;
    PORT
      LAYER M5 ;
        RECT  64.272 105.732 64.296 105.816 ;
    END
  END b[344]
  PIN b[345]
    DIRECTION OUTPUT ;
    USE SIGNAL ;
    PORT
      LAYER M5 ;
        RECT  64.368 105.732 64.392 105.816 ;
    END
  END b[345]
  PIN b[346]
    DIRECTION OUTPUT ;
    USE SIGNAL ;
    PORT
      LAYER M5 ;
        RECT  64.464 105.732 64.488 105.816 ;
    END
  END b[346]
  PIN b[347]
    DIRECTION OUTPUT ;
    USE SIGNAL ;
    PORT
      LAYER M5 ;
        RECT  64.56 105.732 64.584 105.816 ;
    END
  END b[347]
  PIN b[348]
    DIRECTION OUTPUT ;
    USE SIGNAL ;
    PORT
      LAYER M5 ;
        RECT  64.656 105.732 64.68 105.816 ;
    END
  END b[348]
  PIN b[349]
    DIRECTION OUTPUT ;
    USE SIGNAL ;
    PORT
      LAYER M5 ;
        RECT  64.752 105.732 64.776 105.816 ;
    END
  END b[349]
  PIN b[34]
    DIRECTION OUTPUT ;
    USE SIGNAL ;
    PORT
      LAYER M3 ;
        RECT  58.212 105.779 58.23 105.816 ;
    END
  END b[34]
  PIN b[350]
    DIRECTION OUTPUT ;
    USE SIGNAL ;
    PORT
      LAYER M5 ;
        RECT  64.848 105.732 64.872 105.816 ;
    END
  END b[350]
  PIN b[351]
    DIRECTION OUTPUT ;
    USE SIGNAL ;
    PORT
      LAYER M5 ;
        RECT  64.944 105.732 64.968 105.816 ;
    END
  END b[351]
  PIN b[352]
    DIRECTION OUTPUT ;
    USE SIGNAL ;
    PORT
      LAYER M5 ;
        RECT  46.608 105.732 46.632 105.816 ;
    END
  END b[352]
  PIN b[353]
    DIRECTION OUTPUT ;
    USE SIGNAL ;
    PORT
      LAYER M5 ;
        RECT  46.704 105.732 46.728 105.816 ;
    END
  END b[353]
  PIN b[354]
    DIRECTION OUTPUT ;
    USE SIGNAL ;
    PORT
      LAYER M5 ;
        RECT  46.8 105.732 46.824 105.816 ;
    END
  END b[354]
  PIN b[355]
    DIRECTION OUTPUT ;
    USE SIGNAL ;
    PORT
      LAYER M5 ;
        RECT  46.896 105.732 46.92 105.816 ;
    END
  END b[355]
  PIN b[356]
    DIRECTION OUTPUT ;
    USE SIGNAL ;
    PORT
      LAYER M5 ;
        RECT  46.992 105.732 47.016 105.816 ;
    END
  END b[356]
  PIN b[357]
    DIRECTION OUTPUT ;
    USE SIGNAL ;
    PORT
      LAYER M5 ;
        RECT  47.088 105.732 47.112 105.816 ;
    END
  END b[357]
  PIN b[358]
    DIRECTION OUTPUT ;
    USE SIGNAL ;
    PORT
      LAYER M5 ;
        RECT  47.184 105.732 47.208 105.816 ;
    END
  END b[358]
  PIN b[359]
    DIRECTION OUTPUT ;
    USE SIGNAL ;
    PORT
      LAYER M5 ;
        RECT  47.28 105.732 47.304 105.816 ;
    END
  END b[359]
  PIN b[35]
    DIRECTION OUTPUT ;
    USE SIGNAL ;
    PORT
      LAYER M3 ;
        RECT  58.284 105.779 58.302 105.816 ;
    END
  END b[35]
  PIN b[360]
    DIRECTION OUTPUT ;
    USE SIGNAL ;
    PORT
      LAYER M5 ;
        RECT  47.376 105.732 47.4 105.816 ;
    END
  END b[360]
  PIN b[361]
    DIRECTION OUTPUT ;
    USE SIGNAL ;
    PORT
      LAYER M5 ;
        RECT  47.472 105.732 47.496 105.816 ;
    END
  END b[361]
  PIN b[362]
    DIRECTION OUTPUT ;
    USE SIGNAL ;
    PORT
      LAYER M5 ;
        RECT  47.568 105.732 47.592 105.816 ;
    END
  END b[362]
  PIN b[363]
    DIRECTION OUTPUT ;
    USE SIGNAL ;
    PORT
      LAYER M5 ;
        RECT  47.664 105.732 47.688 105.816 ;
    END
  END b[363]
  PIN b[364]
    DIRECTION OUTPUT ;
    USE SIGNAL ;
    PORT
      LAYER M5 ;
        RECT  47.76 105.732 47.784 105.816 ;
    END
  END b[364]
  PIN b[365]
    DIRECTION OUTPUT ;
    USE SIGNAL ;
    PORT
      LAYER M5 ;
        RECT  47.856 105.732 47.88 105.816 ;
    END
  END b[365]
  PIN b[366]
    DIRECTION OUTPUT ;
    USE SIGNAL ;
    PORT
      LAYER M5 ;
        RECT  47.952 105.732 47.976 105.816 ;
    END
  END b[366]
  PIN b[367]
    DIRECTION OUTPUT ;
    USE SIGNAL ;
    PORT
      LAYER M5 ;
        RECT  48.048 105.732 48.072 105.816 ;
    END
  END b[367]
  PIN b[368]
    DIRECTION OUTPUT ;
    USE SIGNAL ;
    PORT
      LAYER M5 ;
        RECT  48.144 105.732 48.168 105.816 ;
    END
  END b[368]
  PIN b[369]
    DIRECTION OUTPUT ;
    USE SIGNAL ;
    PORT
      LAYER M5 ;
        RECT  48.24 105.732 48.264 105.816 ;
    END
  END b[369]
  PIN b[36]
    DIRECTION OUTPUT ;
    USE SIGNAL ;
    PORT
      LAYER M3 ;
        RECT  58.356 105.779 58.374 105.816 ;
    END
  END b[36]
  PIN b[370]
    DIRECTION OUTPUT ;
    USE SIGNAL ;
    PORT
      LAYER M5 ;
        RECT  48.336 105.732 48.36 105.816 ;
    END
  END b[370]
  PIN b[371]
    DIRECTION OUTPUT ;
    USE SIGNAL ;
    PORT
      LAYER M5 ;
        RECT  48.432 105.732 48.456 105.816 ;
    END
  END b[371]
  PIN b[372]
    DIRECTION OUTPUT ;
    USE SIGNAL ;
    PORT
      LAYER M5 ;
        RECT  48.528 105.732 48.552 105.816 ;
    END
  END b[372]
  PIN b[373]
    DIRECTION OUTPUT ;
    USE SIGNAL ;
    PORT
      LAYER M5 ;
        RECT  48.624 105.732 48.648 105.816 ;
    END
  END b[373]
  PIN b[374]
    DIRECTION OUTPUT ;
    USE SIGNAL ;
    PORT
      LAYER M5 ;
        RECT  48.72 105.732 48.744 105.816 ;
    END
  END b[374]
  PIN b[375]
    DIRECTION OUTPUT ;
    USE SIGNAL ;
    PORT
      LAYER M5 ;
        RECT  48.816 105.732 48.84 105.816 ;
    END
  END b[375]
  PIN b[376]
    DIRECTION OUTPUT ;
    USE SIGNAL ;
    PORT
      LAYER M5 ;
        RECT  48.912 105.732 48.936 105.816 ;
    END
  END b[376]
  PIN b[377]
    DIRECTION OUTPUT ;
    USE SIGNAL ;
    PORT
      LAYER M5 ;
        RECT  49.008 105.732 49.032 105.816 ;
    END
  END b[377]
  PIN b[378]
    DIRECTION OUTPUT ;
    USE SIGNAL ;
    PORT
      LAYER M5 ;
        RECT  49.104 105.732 49.128 105.816 ;
    END
  END b[378]
  PIN b[379]
    DIRECTION OUTPUT ;
    USE SIGNAL ;
    PORT
      LAYER M5 ;
        RECT  49.2 105.732 49.224 105.816 ;
    END
  END b[379]
  PIN b[37]
    DIRECTION OUTPUT ;
    USE SIGNAL ;
    PORT
      LAYER M3 ;
        RECT  58.428 105.779 58.446 105.816 ;
    END
  END b[37]
  PIN b[380]
    DIRECTION OUTPUT ;
    USE SIGNAL ;
    PORT
      LAYER M5 ;
        RECT  49.296 105.732 49.32 105.816 ;
    END
  END b[380]
  PIN b[381]
    DIRECTION OUTPUT ;
    USE SIGNAL ;
    PORT
      LAYER M5 ;
        RECT  49.392 105.732 49.416 105.816 ;
    END
  END b[381]
  PIN b[382]
    DIRECTION OUTPUT ;
    USE SIGNAL ;
    PORT
      LAYER M5 ;
        RECT  49.488 105.732 49.512 105.816 ;
    END
  END b[382]
  PIN b[383]
    DIRECTION OUTPUT ;
    USE SIGNAL ;
    PORT
      LAYER M5 ;
        RECT  49.584 105.732 49.608 105.816 ;
    END
  END b[383]
  PIN b[384]
    DIRECTION OUTPUT ;
    USE SIGNAL ;
    PORT
      LAYER M3 ;
        RECT  34.452 105.779 34.47 105.816 ;
    END
  END b[384]
  PIN b[385]
    DIRECTION OUTPUT ;
    USE SIGNAL ;
    PORT
      LAYER M3 ;
        RECT  34.524 105.779 34.542 105.816 ;
    END
  END b[385]
  PIN b[386]
    DIRECTION OUTPUT ;
    USE SIGNAL ;
    PORT
      LAYER M3 ;
        RECT  34.596 105.779 34.614 105.816 ;
    END
  END b[386]
  PIN b[387]
    DIRECTION OUTPUT ;
    USE SIGNAL ;
    PORT
      LAYER M3 ;
        RECT  34.668 105.779 34.686 105.816 ;
    END
  END b[387]
  PIN b[388]
    DIRECTION OUTPUT ;
    USE SIGNAL ;
    PORT
      LAYER M3 ;
        RECT  34.74 105.779 34.758 105.816 ;
    END
  END b[388]
  PIN b[389]
    DIRECTION OUTPUT ;
    USE SIGNAL ;
    PORT
      LAYER M3 ;
        RECT  34.812 105.779 34.83 105.816 ;
    END
  END b[389]
  PIN b[38]
    DIRECTION OUTPUT ;
    USE SIGNAL ;
    PORT
      LAYER M3 ;
        RECT  58.5 105.779 58.518 105.816 ;
    END
  END b[38]
  PIN b[390]
    DIRECTION OUTPUT ;
    USE SIGNAL ;
    PORT
      LAYER M3 ;
        RECT  34.884 105.779 34.902 105.816 ;
    END
  END b[390]
  PIN b[391]
    DIRECTION OUTPUT ;
    USE SIGNAL ;
    PORT
      LAYER M3 ;
        RECT  34.956 105.779 34.974 105.816 ;
    END
  END b[391]
  PIN b[392]
    DIRECTION OUTPUT ;
    USE SIGNAL ;
    PORT
      LAYER M3 ;
        RECT  35.028 105.779 35.046 105.816 ;
    END
  END b[392]
  PIN b[393]
    DIRECTION OUTPUT ;
    USE SIGNAL ;
    PORT
      LAYER M3 ;
        RECT  35.1 105.779 35.118 105.816 ;
    END
  END b[393]
  PIN b[394]
    DIRECTION OUTPUT ;
    USE SIGNAL ;
    PORT
      LAYER M3 ;
        RECT  35.172 105.779 35.19 105.816 ;
    END
  END b[394]
  PIN b[395]
    DIRECTION OUTPUT ;
    USE SIGNAL ;
    PORT
      LAYER M3 ;
        RECT  35.244 105.779 35.262 105.816 ;
    END
  END b[395]
  PIN b[396]
    DIRECTION OUTPUT ;
    USE SIGNAL ;
    PORT
      LAYER M3 ;
        RECT  35.316 105.779 35.334 105.816 ;
    END
  END b[396]
  PIN b[397]
    DIRECTION OUTPUT ;
    USE SIGNAL ;
    PORT
      LAYER M3 ;
        RECT  35.388 105.779 35.406 105.816 ;
    END
  END b[397]
  PIN b[398]
    DIRECTION OUTPUT ;
    USE SIGNAL ;
    PORT
      LAYER M3 ;
        RECT  35.46 105.779 35.478 105.816 ;
    END
  END b[398]
  PIN b[399]
    DIRECTION OUTPUT ;
    USE SIGNAL ;
    PORT
      LAYER M3 ;
        RECT  35.532 105.779 35.55 105.816 ;
    END
  END b[399]
  PIN b[39]
    DIRECTION OUTPUT ;
    USE SIGNAL ;
    PORT
      LAYER M3 ;
        RECT  58.572 105.779 58.59 105.816 ;
    END
  END b[39]
  PIN b[3]
    DIRECTION OUTPUT ;
    USE SIGNAL ;
    PORT
      LAYER M3 ;
        RECT  49.068 105.779 49.086 105.816 ;
    END
  END b[3]
  PIN b[400]
    DIRECTION OUTPUT ;
    USE SIGNAL ;
    PORT
      LAYER M3 ;
        RECT  35.604 105.779 35.622 105.816 ;
    END
  END b[400]
  PIN b[401]
    DIRECTION OUTPUT ;
    USE SIGNAL ;
    PORT
      LAYER M3 ;
        RECT  35.676 105.779 35.694 105.816 ;
    END
  END b[401]
  PIN b[402]
    DIRECTION OUTPUT ;
    USE SIGNAL ;
    PORT
      LAYER M3 ;
        RECT  35.748 105.779 35.766 105.816 ;
    END
  END b[402]
  PIN b[403]
    DIRECTION OUTPUT ;
    USE SIGNAL ;
    PORT
      LAYER M3 ;
        RECT  35.82 105.779 35.838 105.816 ;
    END
  END b[403]
  PIN b[404]
    DIRECTION OUTPUT ;
    USE SIGNAL ;
    PORT
      LAYER M3 ;
        RECT  35.892 105.779 35.91 105.816 ;
    END
  END b[404]
  PIN b[405]
    DIRECTION OUTPUT ;
    USE SIGNAL ;
    PORT
      LAYER M3 ;
        RECT  35.964 105.779 35.982 105.816 ;
    END
  END b[405]
  PIN b[406]
    DIRECTION OUTPUT ;
    USE SIGNAL ;
    PORT
      LAYER M3 ;
        RECT  36.036 105.779 36.054 105.816 ;
    END
  END b[406]
  PIN b[407]
    DIRECTION OUTPUT ;
    USE SIGNAL ;
    PORT
      LAYER M3 ;
        RECT  36.108 105.779 36.126 105.816 ;
    END
  END b[407]
  PIN b[408]
    DIRECTION OUTPUT ;
    USE SIGNAL ;
    PORT
      LAYER M3 ;
        RECT  36.18 105.779 36.198 105.816 ;
    END
  END b[408]
  PIN b[409]
    DIRECTION OUTPUT ;
    USE SIGNAL ;
    PORT
      LAYER M3 ;
        RECT  36.252 105.779 36.27 105.816 ;
    END
  END b[409]
  PIN b[40]
    DIRECTION OUTPUT ;
    USE SIGNAL ;
    PORT
      LAYER M3 ;
        RECT  58.644 105.779 58.662 105.816 ;
    END
  END b[40]
  PIN b[410]
    DIRECTION OUTPUT ;
    USE SIGNAL ;
    PORT
      LAYER M3 ;
        RECT  36.324 105.779 36.342 105.816 ;
    END
  END b[410]
  PIN b[411]
    DIRECTION OUTPUT ;
    USE SIGNAL ;
    PORT
      LAYER M3 ;
        RECT  36.396 105.779 36.414 105.816 ;
    END
  END b[411]
  PIN b[412]
    DIRECTION OUTPUT ;
    USE SIGNAL ;
    PORT
      LAYER M3 ;
        RECT  36.468 105.779 36.486 105.816 ;
    END
  END b[412]
  PIN b[413]
    DIRECTION OUTPUT ;
    USE SIGNAL ;
    PORT
      LAYER M3 ;
        RECT  36.54 105.779 36.558 105.816 ;
    END
  END b[413]
  PIN b[414]
    DIRECTION OUTPUT ;
    USE SIGNAL ;
    PORT
      LAYER M3 ;
        RECT  36.612 105.779 36.63 105.816 ;
    END
  END b[414]
  PIN b[415]
    DIRECTION OUTPUT ;
    USE SIGNAL ;
    PORT
      LAYER M3 ;
        RECT  36.684 105.779 36.702 105.816 ;
    END
  END b[415]
  PIN b[416]
    DIRECTION OUTPUT ;
    USE SIGNAL ;
    PORT
      LAYER M3 ;
        RECT  36.756 105.779 36.774 105.816 ;
    END
  END b[416]
  PIN b[417]
    DIRECTION OUTPUT ;
    USE SIGNAL ;
    PORT
      LAYER M3 ;
        RECT  36.828 105.779 36.846 105.816 ;
    END
  END b[417]
  PIN b[418]
    DIRECTION OUTPUT ;
    USE SIGNAL ;
    PORT
      LAYER M3 ;
        RECT  36.9 105.779 36.918 105.816 ;
    END
  END b[418]
  PIN b[419]
    DIRECTION OUTPUT ;
    USE SIGNAL ;
    PORT
      LAYER M3 ;
        RECT  36.972 105.779 36.99 105.816 ;
    END
  END b[419]
  PIN b[41]
    DIRECTION OUTPUT ;
    USE SIGNAL ;
    PORT
      LAYER M3 ;
        RECT  58.716 105.779 58.734 105.816 ;
    END
  END b[41]
  PIN b[420]
    DIRECTION OUTPUT ;
    USE SIGNAL ;
    PORT
      LAYER M3 ;
        RECT  37.044 105.779 37.062 105.816 ;
    END
  END b[420]
  PIN b[421]
    DIRECTION OUTPUT ;
    USE SIGNAL ;
    PORT
      LAYER M3 ;
        RECT  37.116 105.779 37.134 105.816 ;
    END
  END b[421]
  PIN b[422]
    DIRECTION OUTPUT ;
    USE SIGNAL ;
    PORT
      LAYER M3 ;
        RECT  37.188 105.779 37.206 105.816 ;
    END
  END b[422]
  PIN b[423]
    DIRECTION OUTPUT ;
    USE SIGNAL ;
    PORT
      LAYER M3 ;
        RECT  37.26 105.779 37.278 105.816 ;
    END
  END b[423]
  PIN b[424]
    DIRECTION OUTPUT ;
    USE SIGNAL ;
    PORT
      LAYER M3 ;
        RECT  37.332 105.779 37.35 105.816 ;
    END
  END b[424]
  PIN b[425]
    DIRECTION OUTPUT ;
    USE SIGNAL ;
    PORT
      LAYER M3 ;
        RECT  37.404 105.779 37.422 105.816 ;
    END
  END b[425]
  PIN b[426]
    DIRECTION OUTPUT ;
    USE SIGNAL ;
    PORT
      LAYER M3 ;
        RECT  37.476 105.779 37.494 105.816 ;
    END
  END b[426]
  PIN b[427]
    DIRECTION OUTPUT ;
    USE SIGNAL ;
    PORT
      LAYER M3 ;
        RECT  37.548 105.779 37.566 105.816 ;
    END
  END b[427]
  PIN b[428]
    DIRECTION OUTPUT ;
    USE SIGNAL ;
    PORT
      LAYER M3 ;
        RECT  37.62 105.779 37.638 105.816 ;
    END
  END b[428]
  PIN b[429]
    DIRECTION OUTPUT ;
    USE SIGNAL ;
    PORT
      LAYER M3 ;
        RECT  37.692 105.779 37.71 105.816 ;
    END
  END b[429]
  PIN b[42]
    DIRECTION OUTPUT ;
    USE SIGNAL ;
    PORT
      LAYER M3 ;
        RECT  58.788 105.779 58.806 105.816 ;
    END
  END b[42]
  PIN b[430]
    DIRECTION OUTPUT ;
    USE SIGNAL ;
    PORT
      LAYER M3 ;
        RECT  37.764 105.779 37.782 105.816 ;
    END
  END b[430]
  PIN b[431]
    DIRECTION OUTPUT ;
    USE SIGNAL ;
    PORT
      LAYER M3 ;
        RECT  37.836 105.779 37.854 105.816 ;
    END
  END b[431]
  PIN b[432]
    DIRECTION OUTPUT ;
    USE SIGNAL ;
    PORT
      LAYER M3 ;
        RECT  37.908 105.779 37.926 105.816 ;
    END
  END b[432]
  PIN b[433]
    DIRECTION OUTPUT ;
    USE SIGNAL ;
    PORT
      LAYER M3 ;
        RECT  37.98 105.779 37.998 105.816 ;
    END
  END b[433]
  PIN b[434]
    DIRECTION OUTPUT ;
    USE SIGNAL ;
    PORT
      LAYER M3 ;
        RECT  38.052 105.779 38.07 105.816 ;
    END
  END b[434]
  PIN b[435]
    DIRECTION OUTPUT ;
    USE SIGNAL ;
    PORT
      LAYER M3 ;
        RECT  38.124 105.779 38.142 105.816 ;
    END
  END b[435]
  PIN b[436]
    DIRECTION OUTPUT ;
    USE SIGNAL ;
    PORT
      LAYER M3 ;
        RECT  38.196 105.779 38.214 105.816 ;
    END
  END b[436]
  PIN b[437]
    DIRECTION OUTPUT ;
    USE SIGNAL ;
    PORT
      LAYER M3 ;
        RECT  38.268 105.779 38.286 105.816 ;
    END
  END b[437]
  PIN b[438]
    DIRECTION OUTPUT ;
    USE SIGNAL ;
    PORT
      LAYER M3 ;
        RECT  38.34 105.779 38.358 105.816 ;
    END
  END b[438]
  PIN b[439]
    DIRECTION OUTPUT ;
    USE SIGNAL ;
    PORT
      LAYER M3 ;
        RECT  38.412 105.779 38.43 105.816 ;
    END
  END b[439]
  PIN b[43]
    DIRECTION OUTPUT ;
    USE SIGNAL ;
    PORT
      LAYER M3 ;
        RECT  58.86 105.779 58.878 105.816 ;
    END
  END b[43]
  PIN b[440]
    DIRECTION OUTPUT ;
    USE SIGNAL ;
    PORT
      LAYER M3 ;
        RECT  38.484 105.779 38.502 105.816 ;
    END
  END b[440]
  PIN b[441]
    DIRECTION OUTPUT ;
    USE SIGNAL ;
    PORT
      LAYER M3 ;
        RECT  38.556 105.779 38.574 105.816 ;
    END
  END b[441]
  PIN b[442]
    DIRECTION OUTPUT ;
    USE SIGNAL ;
    PORT
      LAYER M3 ;
        RECT  38.628 105.779 38.646 105.816 ;
    END
  END b[442]
  PIN b[443]
    DIRECTION OUTPUT ;
    USE SIGNAL ;
    PORT
      LAYER M3 ;
        RECT  38.7 105.779 38.718 105.816 ;
    END
  END b[443]
  PIN b[444]
    DIRECTION OUTPUT ;
    USE SIGNAL ;
    PORT
      LAYER M3 ;
        RECT  38.772 105.779 38.79 105.816 ;
    END
  END b[444]
  PIN b[445]
    DIRECTION OUTPUT ;
    USE SIGNAL ;
    PORT
      LAYER M3 ;
        RECT  38.844 105.779 38.862 105.816 ;
    END
  END b[445]
  PIN b[446]
    DIRECTION OUTPUT ;
    USE SIGNAL ;
    PORT
      LAYER M3 ;
        RECT  38.916 105.779 38.934 105.816 ;
    END
  END b[446]
  PIN b[447]
    DIRECTION OUTPUT ;
    USE SIGNAL ;
    PORT
      LAYER M3 ;
        RECT  38.988 105.779 39.006 105.816 ;
    END
  END b[447]
  PIN b[448]
    DIRECTION OUTPUT ;
    USE SIGNAL ;
    PORT
      LAYER M3 ;
        RECT  39.06 105.779 39.078 105.816 ;
    END
  END b[448]
  PIN b[449]
    DIRECTION OUTPUT ;
    USE SIGNAL ;
    PORT
      LAYER M3 ;
        RECT  39.132 105.779 39.15 105.816 ;
    END
  END b[449]
  PIN b[44]
    DIRECTION OUTPUT ;
    USE SIGNAL ;
    PORT
      LAYER M3 ;
        RECT  58.932 105.779 58.95 105.816 ;
    END
  END b[44]
  PIN b[450]
    DIRECTION OUTPUT ;
    USE SIGNAL ;
    PORT
      LAYER M3 ;
        RECT  39.204 105.779 39.222 105.816 ;
    END
  END b[450]
  PIN b[451]
    DIRECTION OUTPUT ;
    USE SIGNAL ;
    PORT
      LAYER M3 ;
        RECT  39.276 105.779 39.294 105.816 ;
    END
  END b[451]
  PIN b[452]
    DIRECTION OUTPUT ;
    USE SIGNAL ;
    PORT
      LAYER M3 ;
        RECT  39.348 105.779 39.366 105.816 ;
    END
  END b[452]
  PIN b[453]
    DIRECTION OUTPUT ;
    USE SIGNAL ;
    PORT
      LAYER M3 ;
        RECT  39.42 105.779 39.438 105.816 ;
    END
  END b[453]
  PIN b[454]
    DIRECTION OUTPUT ;
    USE SIGNAL ;
    PORT
      LAYER M3 ;
        RECT  39.492 105.779 39.51 105.816 ;
    END
  END b[454]
  PIN b[455]
    DIRECTION OUTPUT ;
    USE SIGNAL ;
    PORT
      LAYER M3 ;
        RECT  39.564 105.779 39.582 105.816 ;
    END
  END b[455]
  PIN b[456]
    DIRECTION OUTPUT ;
    USE SIGNAL ;
    PORT
      LAYER M3 ;
        RECT  39.636 105.779 39.654 105.816 ;
    END
  END b[456]
  PIN b[457]
    DIRECTION OUTPUT ;
    USE SIGNAL ;
    PORT
      LAYER M3 ;
        RECT  39.708 105.779 39.726 105.816 ;
    END
  END b[457]
  PIN b[458]
    DIRECTION OUTPUT ;
    USE SIGNAL ;
    PORT
      LAYER M3 ;
        RECT  39.78 105.779 39.798 105.816 ;
    END
  END b[458]
  PIN b[459]
    DIRECTION OUTPUT ;
    USE SIGNAL ;
    PORT
      LAYER M3 ;
        RECT  39.852 105.779 39.87 105.816 ;
    END
  END b[459]
  PIN b[45]
    DIRECTION OUTPUT ;
    USE SIGNAL ;
    PORT
      LAYER M3 ;
        RECT  59.004 105.779 59.022 105.816 ;
    END
  END b[45]
  PIN b[460]
    DIRECTION OUTPUT ;
    USE SIGNAL ;
    PORT
      LAYER M3 ;
        RECT  39.924 105.779 39.942 105.816 ;
    END
  END b[460]
  PIN b[461]
    DIRECTION OUTPUT ;
    USE SIGNAL ;
    PORT
      LAYER M3 ;
        RECT  39.996 105.779 40.014 105.816 ;
    END
  END b[461]
  PIN b[462]
    DIRECTION OUTPUT ;
    USE SIGNAL ;
    PORT
      LAYER M3 ;
        RECT  40.068 105.779 40.086 105.816 ;
    END
  END b[462]
  PIN b[463]
    DIRECTION OUTPUT ;
    USE SIGNAL ;
    PORT
      LAYER M3 ;
        RECT  40.14 105.779 40.158 105.816 ;
    END
  END b[463]
  PIN b[464]
    DIRECTION OUTPUT ;
    USE SIGNAL ;
    PORT
      LAYER M3 ;
        RECT  40.212 105.779 40.23 105.816 ;
    END
  END b[464]
  PIN b[465]
    DIRECTION OUTPUT ;
    USE SIGNAL ;
    PORT
      LAYER M3 ;
        RECT  40.284 105.779 40.302 105.816 ;
    END
  END b[465]
  PIN b[466]
    DIRECTION OUTPUT ;
    USE SIGNAL ;
    PORT
      LAYER M3 ;
        RECT  40.356 105.779 40.374 105.816 ;
    END
  END b[466]
  PIN b[467]
    DIRECTION OUTPUT ;
    USE SIGNAL ;
    PORT
      LAYER M3 ;
        RECT  40.428 105.779 40.446 105.816 ;
    END
  END b[467]
  PIN b[468]
    DIRECTION OUTPUT ;
    USE SIGNAL ;
    PORT
      LAYER M3 ;
        RECT  40.5 105.779 40.518 105.816 ;
    END
  END b[468]
  PIN b[469]
    DIRECTION OUTPUT ;
    USE SIGNAL ;
    PORT
      LAYER M3 ;
        RECT  40.572 105.779 40.59 105.816 ;
    END
  END b[469]
  PIN b[46]
    DIRECTION OUTPUT ;
    USE SIGNAL ;
    PORT
      LAYER M3 ;
        RECT  59.076 105.779 59.094 105.816 ;
    END
  END b[46]
  PIN b[470]
    DIRECTION OUTPUT ;
    USE SIGNAL ;
    PORT
      LAYER M3 ;
        RECT  40.644 105.779 40.662 105.816 ;
    END
  END b[470]
  PIN b[471]
    DIRECTION OUTPUT ;
    USE SIGNAL ;
    PORT
      LAYER M3 ;
        RECT  40.716 105.779 40.734 105.816 ;
    END
  END b[471]
  PIN b[472]
    DIRECTION OUTPUT ;
    USE SIGNAL ;
    PORT
      LAYER M3 ;
        RECT  40.788 105.779 40.806 105.816 ;
    END
  END b[472]
  PIN b[473]
    DIRECTION OUTPUT ;
    USE SIGNAL ;
    PORT
      LAYER M3 ;
        RECT  40.86 105.779 40.878 105.816 ;
    END
  END b[473]
  PIN b[474]
    DIRECTION OUTPUT ;
    USE SIGNAL ;
    PORT
      LAYER M3 ;
        RECT  40.932 105.779 40.95 105.816 ;
    END
  END b[474]
  PIN b[475]
    DIRECTION OUTPUT ;
    USE SIGNAL ;
    PORT
      LAYER M3 ;
        RECT  41.004 105.779 41.022 105.816 ;
    END
  END b[475]
  PIN b[476]
    DIRECTION OUTPUT ;
    USE SIGNAL ;
    PORT
      LAYER M3 ;
        RECT  41.076 105.779 41.094 105.816 ;
    END
  END b[476]
  PIN b[477]
    DIRECTION OUTPUT ;
    USE SIGNAL ;
    PORT
      LAYER M3 ;
        RECT  41.148 105.779 41.166 105.816 ;
    END
  END b[477]
  PIN b[478]
    DIRECTION OUTPUT ;
    USE SIGNAL ;
    PORT
      LAYER M3 ;
        RECT  41.22 105.779 41.238 105.816 ;
    END
  END b[478]
  PIN b[479]
    DIRECTION OUTPUT ;
    USE SIGNAL ;
    PORT
      LAYER M3 ;
        RECT  41.292 105.779 41.31 105.816 ;
    END
  END b[479]
  PIN b[47]
    DIRECTION OUTPUT ;
    USE SIGNAL ;
    PORT
      LAYER M3 ;
        RECT  59.148 105.779 59.166 105.816 ;
    END
  END b[47]
  PIN b[480]
    DIRECTION OUTPUT ;
    USE SIGNAL ;
    PORT
      LAYER M3 ;
        RECT  41.364 105.779 41.382 105.816 ;
    END
  END b[480]
  PIN b[481]
    DIRECTION OUTPUT ;
    USE SIGNAL ;
    PORT
      LAYER M3 ;
        RECT  41.436 105.779 41.454 105.816 ;
    END
  END b[481]
  PIN b[482]
    DIRECTION OUTPUT ;
    USE SIGNAL ;
    PORT
      LAYER M3 ;
        RECT  41.508 105.779 41.526 105.816 ;
    END
  END b[482]
  PIN b[483]
    DIRECTION OUTPUT ;
    USE SIGNAL ;
    PORT
      LAYER M3 ;
        RECT  41.58 105.779 41.598 105.816 ;
    END
  END b[483]
  PIN b[484]
    DIRECTION OUTPUT ;
    USE SIGNAL ;
    PORT
      LAYER M3 ;
        RECT  41.652 105.779 41.67 105.816 ;
    END
  END b[484]
  PIN b[485]
    DIRECTION OUTPUT ;
    USE SIGNAL ;
    PORT
      LAYER M3 ;
        RECT  41.724 105.779 41.742 105.816 ;
    END
  END b[485]
  PIN b[486]
    DIRECTION OUTPUT ;
    USE SIGNAL ;
    PORT
      LAYER M3 ;
        RECT  41.796 105.779 41.814 105.816 ;
    END
  END b[486]
  PIN b[487]
    DIRECTION OUTPUT ;
    USE SIGNAL ;
    PORT
      LAYER M3 ;
        RECT  41.868 105.779 41.886 105.816 ;
    END
  END b[487]
  PIN b[488]
    DIRECTION OUTPUT ;
    USE SIGNAL ;
    PORT
      LAYER M3 ;
        RECT  41.94 105.779 41.958 105.816 ;
    END
  END b[488]
  PIN b[489]
    DIRECTION OUTPUT ;
    USE SIGNAL ;
    PORT
      LAYER M3 ;
        RECT  42.012 105.779 42.03 105.816 ;
    END
  END b[489]
  PIN b[48]
    DIRECTION OUTPUT ;
    USE SIGNAL ;
    PORT
      LAYER M3 ;
        RECT  59.22 105.779 59.238 105.816 ;
    END
  END b[48]
  PIN b[490]
    DIRECTION OUTPUT ;
    USE SIGNAL ;
    PORT
      LAYER M3 ;
        RECT  42.084 105.779 42.102 105.816 ;
    END
  END b[490]
  PIN b[491]
    DIRECTION OUTPUT ;
    USE SIGNAL ;
    PORT
      LAYER M3 ;
        RECT  42.156 105.779 42.174 105.816 ;
    END
  END b[491]
  PIN b[492]
    DIRECTION OUTPUT ;
    USE SIGNAL ;
    PORT
      LAYER M3 ;
        RECT  42.228 105.779 42.246 105.816 ;
    END
  END b[492]
  PIN b[493]
    DIRECTION OUTPUT ;
    USE SIGNAL ;
    PORT
      LAYER M3 ;
        RECT  42.3 105.779 42.318 105.816 ;
    END
  END b[493]
  PIN b[494]
    DIRECTION OUTPUT ;
    USE SIGNAL ;
    PORT
      LAYER M3 ;
        RECT  42.372 105.779 42.39 105.816 ;
    END
  END b[494]
  PIN b[495]
    DIRECTION OUTPUT ;
    USE SIGNAL ;
    PORT
      LAYER M3 ;
        RECT  42.444 105.779 42.462 105.816 ;
    END
  END b[495]
  PIN b[496]
    DIRECTION OUTPUT ;
    USE SIGNAL ;
    PORT
      LAYER M3 ;
        RECT  42.516 105.779 42.534 105.816 ;
    END
  END b[496]
  PIN b[497]
    DIRECTION OUTPUT ;
    USE SIGNAL ;
    PORT
      LAYER M3 ;
        RECT  42.588 105.779 42.606 105.816 ;
    END
  END b[497]
  PIN b[498]
    DIRECTION OUTPUT ;
    USE SIGNAL ;
    PORT
      LAYER M3 ;
        RECT  42.66 105.779 42.678 105.816 ;
    END
  END b[498]
  PIN b[499]
    DIRECTION OUTPUT ;
    USE SIGNAL ;
    PORT
      LAYER M3 ;
        RECT  42.732 105.779 42.75 105.816 ;
    END
  END b[499]
  PIN b[49]
    DIRECTION OUTPUT ;
    USE SIGNAL ;
    PORT
      LAYER M3 ;
        RECT  59.292 105.779 59.31 105.816 ;
    END
  END b[49]
  PIN b[4]
    DIRECTION OUTPUT ;
    USE SIGNAL ;
    PORT
      LAYER M3 ;
        RECT  49.14 105.779 49.158 105.816 ;
    END
  END b[4]
  PIN b[500]
    DIRECTION OUTPUT ;
    USE SIGNAL ;
    PORT
      LAYER M3 ;
        RECT  42.804 105.779 42.822 105.816 ;
    END
  END b[500]
  PIN b[501]
    DIRECTION OUTPUT ;
    USE SIGNAL ;
    PORT
      LAYER M3 ;
        RECT  42.876 105.779 42.894 105.816 ;
    END
  END b[501]
  PIN b[502]
    DIRECTION OUTPUT ;
    USE SIGNAL ;
    PORT
      LAYER M3 ;
        RECT  42.948 105.779 42.966 105.816 ;
    END
  END b[502]
  PIN b[503]
    DIRECTION OUTPUT ;
    USE SIGNAL ;
    PORT
      LAYER M3 ;
        RECT  43.02 105.779 43.038 105.816 ;
    END
  END b[503]
  PIN b[504]
    DIRECTION OUTPUT ;
    USE SIGNAL ;
    PORT
      LAYER M3 ;
        RECT  43.092 105.779 43.11 105.816 ;
    END
  END b[504]
  PIN b[505]
    DIRECTION OUTPUT ;
    USE SIGNAL ;
    PORT
      LAYER M3 ;
        RECT  43.164 105.779 43.182 105.816 ;
    END
  END b[505]
  PIN b[506]
    DIRECTION OUTPUT ;
    USE SIGNAL ;
    PORT
      LAYER M3 ;
        RECT  43.236 105.779 43.254 105.816 ;
    END
  END b[506]
  PIN b[507]
    DIRECTION OUTPUT ;
    USE SIGNAL ;
    PORT
      LAYER M3 ;
        RECT  43.308 105.779 43.326 105.816 ;
    END
  END b[507]
  PIN b[508]
    DIRECTION OUTPUT ;
    USE SIGNAL ;
    PORT
      LAYER M3 ;
        RECT  43.38 105.779 43.398 105.816 ;
    END
  END b[508]
  PIN b[509]
    DIRECTION OUTPUT ;
    USE SIGNAL ;
    PORT
      LAYER M3 ;
        RECT  43.452 105.779 43.47 105.816 ;
    END
  END b[509]
  PIN b[50]
    DIRECTION OUTPUT ;
    USE SIGNAL ;
    PORT
      LAYER M3 ;
        RECT  59.364 105.779 59.382 105.816 ;
    END
  END b[50]
  PIN b[510]
    DIRECTION OUTPUT ;
    USE SIGNAL ;
    PORT
      LAYER M3 ;
        RECT  43.524 105.779 43.542 105.816 ;
    END
  END b[510]
  PIN b[511]
    DIRECTION OUTPUT ;
    USE SIGNAL ;
    PORT
      LAYER M3 ;
        RECT  43.596 105.779 43.614 105.816 ;
    END
  END b[511]
  PIN b[512]
    DIRECTION OUTPUT ;
    USE SIGNAL ;
    PORT
      LAYER M3 ;
        RECT  60.948 105.779 60.966 105.816 ;
    END
  END b[512]
  PIN b[513]
    DIRECTION OUTPUT ;
    USE SIGNAL ;
    PORT
      LAYER M3 ;
        RECT  61.02 105.779 61.038 105.816 ;
    END
  END b[513]
  PIN b[514]
    DIRECTION OUTPUT ;
    USE SIGNAL ;
    PORT
      LAYER M3 ;
        RECT  61.092 105.779 61.11 105.816 ;
    END
  END b[514]
  PIN b[515]
    DIRECTION OUTPUT ;
    USE SIGNAL ;
    PORT
      LAYER M3 ;
        RECT  61.164 105.779 61.182 105.816 ;
    END
  END b[515]
  PIN b[516]
    DIRECTION OUTPUT ;
    USE SIGNAL ;
    PORT
      LAYER M3 ;
        RECT  61.236 105.779 61.254 105.816 ;
    END
  END b[516]
  PIN b[517]
    DIRECTION OUTPUT ;
    USE SIGNAL ;
    PORT
      LAYER M3 ;
        RECT  61.308 105.779 61.326 105.816 ;
    END
  END b[517]
  PIN b[518]
    DIRECTION OUTPUT ;
    USE SIGNAL ;
    PORT
      LAYER M3 ;
        RECT  61.38 105.779 61.398 105.816 ;
    END
  END b[518]
  PIN b[519]
    DIRECTION OUTPUT ;
    USE SIGNAL ;
    PORT
      LAYER M3 ;
        RECT  61.452 105.779 61.47 105.816 ;
    END
  END b[519]
  PIN b[51]
    DIRECTION OUTPUT ;
    USE SIGNAL ;
    PORT
      LAYER M3 ;
        RECT  59.436 105.779 59.454 105.816 ;
    END
  END b[51]
  PIN b[520]
    DIRECTION OUTPUT ;
    USE SIGNAL ;
    PORT
      LAYER M3 ;
        RECT  61.524 105.779 61.542 105.816 ;
    END
  END b[520]
  PIN b[521]
    DIRECTION OUTPUT ;
    USE SIGNAL ;
    PORT
      LAYER M3 ;
        RECT  61.596 105.779 61.614 105.816 ;
    END
  END b[521]
  PIN b[522]
    DIRECTION OUTPUT ;
    USE SIGNAL ;
    PORT
      LAYER M3 ;
        RECT  61.668 105.779 61.686 105.816 ;
    END
  END b[522]
  PIN b[523]
    DIRECTION OUTPUT ;
    USE SIGNAL ;
    PORT
      LAYER M3 ;
        RECT  61.74 105.779 61.758 105.816 ;
    END
  END b[523]
  PIN b[524]
    DIRECTION OUTPUT ;
    USE SIGNAL ;
    PORT
      LAYER M3 ;
        RECT  61.812 105.779 61.83 105.816 ;
    END
  END b[524]
  PIN b[525]
    DIRECTION OUTPUT ;
    USE SIGNAL ;
    PORT
      LAYER M3 ;
        RECT  61.884 105.779 61.902 105.816 ;
    END
  END b[525]
  PIN b[526]
    DIRECTION OUTPUT ;
    USE SIGNAL ;
    PORT
      LAYER M3 ;
        RECT  61.956 105.779 61.974 105.816 ;
    END
  END b[526]
  PIN b[527]
    DIRECTION OUTPUT ;
    USE SIGNAL ;
    PORT
      LAYER M3 ;
        RECT  62.028 105.779 62.046 105.816 ;
    END
  END b[527]
  PIN b[528]
    DIRECTION OUTPUT ;
    USE SIGNAL ;
    PORT
      LAYER M3 ;
        RECT  62.1 105.779 62.118 105.816 ;
    END
  END b[528]
  PIN b[529]
    DIRECTION OUTPUT ;
    USE SIGNAL ;
    PORT
      LAYER M3 ;
        RECT  62.172 105.779 62.19 105.816 ;
    END
  END b[529]
  PIN b[52]
    DIRECTION OUTPUT ;
    USE SIGNAL ;
    PORT
      LAYER M3 ;
        RECT  59.508 105.779 59.526 105.816 ;
    END
  END b[52]
  PIN b[530]
    DIRECTION OUTPUT ;
    USE SIGNAL ;
    PORT
      LAYER M3 ;
        RECT  62.244 105.779 62.262 105.816 ;
    END
  END b[530]
  PIN b[531]
    DIRECTION OUTPUT ;
    USE SIGNAL ;
    PORT
      LAYER M3 ;
        RECT  62.316 105.779 62.334 105.816 ;
    END
  END b[531]
  PIN b[532]
    DIRECTION OUTPUT ;
    USE SIGNAL ;
    PORT
      LAYER M3 ;
        RECT  62.388 105.779 62.406 105.816 ;
    END
  END b[532]
  PIN b[533]
    DIRECTION OUTPUT ;
    USE SIGNAL ;
    PORT
      LAYER M3 ;
        RECT  62.46 105.779 62.478 105.816 ;
    END
  END b[533]
  PIN b[534]
    DIRECTION OUTPUT ;
    USE SIGNAL ;
    PORT
      LAYER M3 ;
        RECT  62.532 105.779 62.55 105.816 ;
    END
  END b[534]
  PIN b[535]
    DIRECTION OUTPUT ;
    USE SIGNAL ;
    PORT
      LAYER M3 ;
        RECT  62.604 105.779 62.622 105.816 ;
    END
  END b[535]
  PIN b[536]
    DIRECTION OUTPUT ;
    USE SIGNAL ;
    PORT
      LAYER M3 ;
        RECT  62.676 105.779 62.694 105.816 ;
    END
  END b[536]
  PIN b[537]
    DIRECTION OUTPUT ;
    USE SIGNAL ;
    PORT
      LAYER M3 ;
        RECT  62.748 105.779 62.766 105.816 ;
    END
  END b[537]
  PIN b[538]
    DIRECTION OUTPUT ;
    USE SIGNAL ;
    PORT
      LAYER M3 ;
        RECT  62.82 105.779 62.838 105.816 ;
    END
  END b[538]
  PIN b[539]
    DIRECTION OUTPUT ;
    USE SIGNAL ;
    PORT
      LAYER M3 ;
        RECT  62.892 105.779 62.91 105.816 ;
    END
  END b[539]
  PIN b[53]
    DIRECTION OUTPUT ;
    USE SIGNAL ;
    PORT
      LAYER M3 ;
        RECT  59.58 105.779 59.598 105.816 ;
    END
  END b[53]
  PIN b[540]
    DIRECTION OUTPUT ;
    USE SIGNAL ;
    PORT
      LAYER M3 ;
        RECT  62.964 105.779 62.982 105.816 ;
    END
  END b[540]
  PIN b[541]
    DIRECTION OUTPUT ;
    USE SIGNAL ;
    PORT
      LAYER M3 ;
        RECT  63.036 105.779 63.054 105.816 ;
    END
  END b[541]
  PIN b[542]
    DIRECTION OUTPUT ;
    USE SIGNAL ;
    PORT
      LAYER M3 ;
        RECT  63.108 105.779 63.126 105.816 ;
    END
  END b[542]
  PIN b[543]
    DIRECTION OUTPUT ;
    USE SIGNAL ;
    PORT
      LAYER M3 ;
        RECT  63.18 105.779 63.198 105.816 ;
    END
  END b[543]
  PIN b[544]
    DIRECTION OUTPUT ;
    USE SIGNAL ;
    PORT
      LAYER M3 ;
        RECT  43.668 105.779 43.686 105.816 ;
    END
  END b[544]
  PIN b[545]
    DIRECTION OUTPUT ;
    USE SIGNAL ;
    PORT
      LAYER M3 ;
        RECT  43.74 105.779 43.758 105.816 ;
    END
  END b[545]
  PIN b[546]
    DIRECTION OUTPUT ;
    USE SIGNAL ;
    PORT
      LAYER M3 ;
        RECT  43.812 105.779 43.83 105.816 ;
    END
  END b[546]
  PIN b[547]
    DIRECTION OUTPUT ;
    USE SIGNAL ;
    PORT
      LAYER M3 ;
        RECT  43.884 105.779 43.902 105.816 ;
    END
  END b[547]
  PIN b[548]
    DIRECTION OUTPUT ;
    USE SIGNAL ;
    PORT
      LAYER M3 ;
        RECT  43.956 105.779 43.974 105.816 ;
    END
  END b[548]
  PIN b[549]
    DIRECTION OUTPUT ;
    USE SIGNAL ;
    PORT
      LAYER M3 ;
        RECT  44.028 105.779 44.046 105.816 ;
    END
  END b[549]
  PIN b[54]
    DIRECTION OUTPUT ;
    USE SIGNAL ;
    PORT
      LAYER M3 ;
        RECT  59.652 105.779 59.67 105.816 ;
    END
  END b[54]
  PIN b[550]
    DIRECTION OUTPUT ;
    USE SIGNAL ;
    PORT
      LAYER M3 ;
        RECT  44.1 105.779 44.118 105.816 ;
    END
  END b[550]
  PIN b[551]
    DIRECTION OUTPUT ;
    USE SIGNAL ;
    PORT
      LAYER M3 ;
        RECT  44.172 105.779 44.19 105.816 ;
    END
  END b[551]
  PIN b[552]
    DIRECTION OUTPUT ;
    USE SIGNAL ;
    PORT
      LAYER M3 ;
        RECT  44.244 105.779 44.262 105.816 ;
    END
  END b[552]
  PIN b[553]
    DIRECTION OUTPUT ;
    USE SIGNAL ;
    PORT
      LAYER M3 ;
        RECT  44.316 105.779 44.334 105.816 ;
    END
  END b[553]
  PIN b[554]
    DIRECTION OUTPUT ;
    USE SIGNAL ;
    PORT
      LAYER M3 ;
        RECT  44.388 105.779 44.406 105.816 ;
    END
  END b[554]
  PIN b[555]
    DIRECTION OUTPUT ;
    USE SIGNAL ;
    PORT
      LAYER M3 ;
        RECT  44.46 105.779 44.478 105.816 ;
    END
  END b[555]
  PIN b[556]
    DIRECTION OUTPUT ;
    USE SIGNAL ;
    PORT
      LAYER M3 ;
        RECT  44.532 105.779 44.55 105.816 ;
    END
  END b[556]
  PIN b[557]
    DIRECTION OUTPUT ;
    USE SIGNAL ;
    PORT
      LAYER M3 ;
        RECT  44.604 105.779 44.622 105.816 ;
    END
  END b[557]
  PIN b[558]
    DIRECTION OUTPUT ;
    USE SIGNAL ;
    PORT
      LAYER M3 ;
        RECT  44.676 105.779 44.694 105.816 ;
    END
  END b[558]
  PIN b[559]
    DIRECTION OUTPUT ;
    USE SIGNAL ;
    PORT
      LAYER M3 ;
        RECT  44.748 105.779 44.766 105.816 ;
    END
  END b[559]
  PIN b[55]
    DIRECTION OUTPUT ;
    USE SIGNAL ;
    PORT
      LAYER M3 ;
        RECT  59.724 105.779 59.742 105.816 ;
    END
  END b[55]
  PIN b[560]
    DIRECTION OUTPUT ;
    USE SIGNAL ;
    PORT
      LAYER M3 ;
        RECT  44.82 105.779 44.838 105.816 ;
    END
  END b[560]
  PIN b[561]
    DIRECTION OUTPUT ;
    USE SIGNAL ;
    PORT
      LAYER M3 ;
        RECT  44.892 105.779 44.91 105.816 ;
    END
  END b[561]
  PIN b[562]
    DIRECTION OUTPUT ;
    USE SIGNAL ;
    PORT
      LAYER M3 ;
        RECT  44.964 105.779 44.982 105.816 ;
    END
  END b[562]
  PIN b[563]
    DIRECTION OUTPUT ;
    USE SIGNAL ;
    PORT
      LAYER M3 ;
        RECT  45.036 105.779 45.054 105.816 ;
    END
  END b[563]
  PIN b[564]
    DIRECTION OUTPUT ;
    USE SIGNAL ;
    PORT
      LAYER M3 ;
        RECT  45.108 105.779 45.126 105.816 ;
    END
  END b[564]
  PIN b[565]
    DIRECTION OUTPUT ;
    USE SIGNAL ;
    PORT
      LAYER M3 ;
        RECT  45.18 105.779 45.198 105.816 ;
    END
  END b[565]
  PIN b[566]
    DIRECTION OUTPUT ;
    USE SIGNAL ;
    PORT
      LAYER M3 ;
        RECT  45.252 105.779 45.27 105.816 ;
    END
  END b[566]
  PIN b[567]
    DIRECTION OUTPUT ;
    USE SIGNAL ;
    PORT
      LAYER M3 ;
        RECT  45.324 105.779 45.342 105.816 ;
    END
  END b[567]
  PIN b[568]
    DIRECTION OUTPUT ;
    USE SIGNAL ;
    PORT
      LAYER M3 ;
        RECT  45.396 105.779 45.414 105.816 ;
    END
  END b[568]
  PIN b[569]
    DIRECTION OUTPUT ;
    USE SIGNAL ;
    PORT
      LAYER M3 ;
        RECT  45.468 105.779 45.486 105.816 ;
    END
  END b[569]
  PIN b[56]
    DIRECTION OUTPUT ;
    USE SIGNAL ;
    PORT
      LAYER M3 ;
        RECT  59.796 105.779 59.814 105.816 ;
    END
  END b[56]
  PIN b[570]
    DIRECTION OUTPUT ;
    USE SIGNAL ;
    PORT
      LAYER M3 ;
        RECT  45.54 105.779 45.558 105.816 ;
    END
  END b[570]
  PIN b[571]
    DIRECTION OUTPUT ;
    USE SIGNAL ;
    PORT
      LAYER M3 ;
        RECT  45.612 105.779 45.63 105.816 ;
    END
  END b[571]
  PIN b[572]
    DIRECTION OUTPUT ;
    USE SIGNAL ;
    PORT
      LAYER M3 ;
        RECT  45.684 105.779 45.702 105.816 ;
    END
  END b[572]
  PIN b[573]
    DIRECTION OUTPUT ;
    USE SIGNAL ;
    PORT
      LAYER M3 ;
        RECT  45.756 105.779 45.774 105.816 ;
    END
  END b[573]
  PIN b[574]
    DIRECTION OUTPUT ;
    USE SIGNAL ;
    PORT
      LAYER M3 ;
        RECT  45.828 105.779 45.846 105.816 ;
    END
  END b[574]
  PIN b[575]
    DIRECTION OUTPUT ;
    USE SIGNAL ;
    PORT
      LAYER M3 ;
        RECT  45.9 105.779 45.918 105.816 ;
    END
  END b[575]
  PIN b[576]
    DIRECTION OUTPUT ;
    USE SIGNAL ;
    PORT
      LAYER M3 ;
        RECT  32.652 105.779 32.67 105.816 ;
    END
  END b[576]
  PIN b[577]
    DIRECTION OUTPUT ;
    USE SIGNAL ;
    PORT
      LAYER M3 ;
        RECT  32.724 105.779 32.742 105.816 ;
    END
  END b[577]
  PIN b[578]
    DIRECTION OUTPUT ;
    USE SIGNAL ;
    PORT
      LAYER M3 ;
        RECT  32.796 105.779 32.814 105.816 ;
    END
  END b[578]
  PIN b[579]
    DIRECTION OUTPUT ;
    USE SIGNAL ;
    PORT
      LAYER M3 ;
        RECT  32.868 105.779 32.886 105.816 ;
    END
  END b[579]
  PIN b[57]
    DIRECTION OUTPUT ;
    USE SIGNAL ;
    PORT
      LAYER M3 ;
        RECT  59.868 105.779 59.886 105.816 ;
    END
  END b[57]
  PIN b[580]
    DIRECTION OUTPUT ;
    USE SIGNAL ;
    PORT
      LAYER M3 ;
        RECT  32.94 105.779 32.958 105.816 ;
    END
  END b[580]
  PIN b[581]
    DIRECTION OUTPUT ;
    USE SIGNAL ;
    PORT
      LAYER M3 ;
        RECT  33.012 105.779 33.03 105.816 ;
    END
  END b[581]
  PIN b[582]
    DIRECTION OUTPUT ;
    USE SIGNAL ;
    PORT
      LAYER M3 ;
        RECT  33.084 105.779 33.102 105.816 ;
    END
  END b[582]
  PIN b[583]
    DIRECTION OUTPUT ;
    USE SIGNAL ;
    PORT
      LAYER M3 ;
        RECT  33.156 105.779 33.174 105.816 ;
    END
  END b[583]
  PIN b[584]
    DIRECTION OUTPUT ;
    USE SIGNAL ;
    PORT
      LAYER M3 ;
        RECT  33.228 105.779 33.246 105.816 ;
    END
  END b[584]
  PIN b[585]
    DIRECTION OUTPUT ;
    USE SIGNAL ;
    PORT
      LAYER M3 ;
        RECT  33.3 105.779 33.318 105.816 ;
    END
  END b[585]
  PIN b[586]
    DIRECTION OUTPUT ;
    USE SIGNAL ;
    PORT
      LAYER M3 ;
        RECT  33.372 105.779 33.39 105.816 ;
    END
  END b[586]
  PIN b[587]
    DIRECTION OUTPUT ;
    USE SIGNAL ;
    PORT
      LAYER M3 ;
        RECT  33.444 105.779 33.462 105.816 ;
    END
  END b[587]
  PIN b[588]
    DIRECTION OUTPUT ;
    USE SIGNAL ;
    PORT
      LAYER M3 ;
        RECT  33.516 105.779 33.534 105.816 ;
    END
  END b[588]
  PIN b[589]
    DIRECTION OUTPUT ;
    USE SIGNAL ;
    PORT
      LAYER M3 ;
        RECT  33.588 105.779 33.606 105.816 ;
    END
  END b[589]
  PIN b[58]
    DIRECTION OUTPUT ;
    USE SIGNAL ;
    PORT
      LAYER M3 ;
        RECT  59.94 105.779 59.958 105.816 ;
    END
  END b[58]
  PIN b[590]
    DIRECTION OUTPUT ;
    USE SIGNAL ;
    PORT
      LAYER M3 ;
        RECT  33.66 105.779 33.678 105.816 ;
    END
  END b[590]
  PIN b[591]
    DIRECTION OUTPUT ;
    USE SIGNAL ;
    PORT
      LAYER M3 ;
        RECT  33.732 105.779 33.75 105.816 ;
    END
  END b[591]
  PIN b[592]
    DIRECTION OUTPUT ;
    USE SIGNAL ;
    PORT
      LAYER M3 ;
        RECT  33.804 105.779 33.822 105.816 ;
    END
  END b[592]
  PIN b[593]
    DIRECTION OUTPUT ;
    USE SIGNAL ;
    PORT
      LAYER M3 ;
        RECT  33.876 105.779 33.894 105.816 ;
    END
  END b[593]
  PIN b[594]
    DIRECTION OUTPUT ;
    USE SIGNAL ;
    PORT
      LAYER M3 ;
        RECT  33.948 105.779 33.966 105.816 ;
    END
  END b[594]
  PIN b[595]
    DIRECTION OUTPUT ;
    USE SIGNAL ;
    PORT
      LAYER M3 ;
        RECT  34.02 105.779 34.038 105.816 ;
    END
  END b[595]
  PIN b[596]
    DIRECTION OUTPUT ;
    USE SIGNAL ;
    PORT
      LAYER M3 ;
        RECT  34.092 105.779 34.11 105.816 ;
    END
  END b[596]
  PIN b[597]
    DIRECTION OUTPUT ;
    USE SIGNAL ;
    PORT
      LAYER M3 ;
        RECT  34.164 105.779 34.182 105.816 ;
    END
  END b[597]
  PIN b[598]
    DIRECTION OUTPUT ;
    USE SIGNAL ;
    PORT
      LAYER M3 ;
        RECT  34.236 105.779 34.254 105.816 ;
    END
  END b[598]
  PIN b[599]
    DIRECTION OUTPUT ;
    USE SIGNAL ;
    PORT
      LAYER M3 ;
        RECT  34.308 105.779 34.326 105.816 ;
    END
  END b[599]
  PIN b[59]
    DIRECTION OUTPUT ;
    USE SIGNAL ;
    PORT
      LAYER M3 ;
        RECT  60.012 105.779 60.03 105.816 ;
    END
  END b[59]
  PIN b[5]
    DIRECTION OUTPUT ;
    USE SIGNAL ;
    PORT
      LAYER M3 ;
        RECT  49.212 105.779 49.23 105.816 ;
    END
  END b[5]
  PIN b[60]
    DIRECTION OUTPUT ;
    USE SIGNAL ;
    PORT
      LAYER M3 ;
        RECT  60.084 105.779 60.102 105.816 ;
    END
  END b[60]
  PIN b[61]
    DIRECTION OUTPUT ;
    USE SIGNAL ;
    PORT
      LAYER M3 ;
        RECT  60.156 105.779 60.174 105.816 ;
    END
  END b[61]
  PIN b[62]
    DIRECTION OUTPUT ;
    USE SIGNAL ;
    PORT
      LAYER M3 ;
        RECT  60.228 105.779 60.246 105.816 ;
    END
  END b[62]
  PIN b[63]
    DIRECTION OUTPUT ;
    USE SIGNAL ;
    PORT
      LAYER M3 ;
        RECT  60.3 105.779 60.318 105.816 ;
    END
  END b[63]
  PIN b[64]
    DIRECTION OUTPUT ;
    USE SIGNAL ;
    PORT
      LAYER M3 ;
        RECT  46.548 105.779 46.566 105.816 ;
    END
  END b[64]
  PIN b[65]
    DIRECTION OUTPUT ;
    USE SIGNAL ;
    PORT
      LAYER M3 ;
        RECT  46.62 105.779 46.638 105.816 ;
    END
  END b[65]
  PIN b[66]
    DIRECTION OUTPUT ;
    USE SIGNAL ;
    PORT
      LAYER M3 ;
        RECT  46.692 105.779 46.71 105.816 ;
    END
  END b[66]
  PIN b[67]
    DIRECTION OUTPUT ;
    USE SIGNAL ;
    PORT
      LAYER M3 ;
        RECT  46.764 105.779 46.782 105.816 ;
    END
  END b[67]
  PIN b[68]
    DIRECTION OUTPUT ;
    USE SIGNAL ;
    PORT
      LAYER M3 ;
        RECT  46.836 105.779 46.854 105.816 ;
    END
  END b[68]
  PIN b[69]
    DIRECTION OUTPUT ;
    USE SIGNAL ;
    PORT
      LAYER M3 ;
        RECT  46.908 105.779 46.926 105.816 ;
    END
  END b[69]
  PIN b[6]
    DIRECTION OUTPUT ;
    USE SIGNAL ;
    PORT
      LAYER M3 ;
        RECT  49.284 105.779 49.302 105.816 ;
    END
  END b[6]
  PIN b[70]
    DIRECTION OUTPUT ;
    USE SIGNAL ;
    PORT
      LAYER M3 ;
        RECT  46.98 105.779 46.998 105.816 ;
    END
  END b[70]
  PIN b[71]
    DIRECTION OUTPUT ;
    USE SIGNAL ;
    PORT
      LAYER M3 ;
        RECT  47.052 105.779 47.07 105.816 ;
    END
  END b[71]
  PIN b[72]
    DIRECTION OUTPUT ;
    USE SIGNAL ;
    PORT
      LAYER M3 ;
        RECT  47.124 105.779 47.142 105.816 ;
    END
  END b[72]
  PIN b[73]
    DIRECTION OUTPUT ;
    USE SIGNAL ;
    PORT
      LAYER M3 ;
        RECT  47.196 105.779 47.214 105.816 ;
    END
  END b[73]
  PIN b[74]
    DIRECTION OUTPUT ;
    USE SIGNAL ;
    PORT
      LAYER M3 ;
        RECT  47.268 105.779 47.286 105.816 ;
    END
  END b[74]
  PIN b[75]
    DIRECTION OUTPUT ;
    USE SIGNAL ;
    PORT
      LAYER M3 ;
        RECT  47.34 105.779 47.358 105.816 ;
    END
  END b[75]
  PIN b[76]
    DIRECTION OUTPUT ;
    USE SIGNAL ;
    PORT
      LAYER M3 ;
        RECT  47.412 105.779 47.43 105.816 ;
    END
  END b[76]
  PIN b[77]
    DIRECTION OUTPUT ;
    USE SIGNAL ;
    PORT
      LAYER M3 ;
        RECT  47.484 105.779 47.502 105.816 ;
    END
  END b[77]
  PIN b[78]
    DIRECTION OUTPUT ;
    USE SIGNAL ;
    PORT
      LAYER M3 ;
        RECT  47.556 105.779 47.574 105.816 ;
    END
  END b[78]
  PIN b[79]
    DIRECTION OUTPUT ;
    USE SIGNAL ;
    PORT
      LAYER M3 ;
        RECT  47.628 105.779 47.646 105.816 ;
    END
  END b[79]
  PIN b[7]
    DIRECTION OUTPUT ;
    USE SIGNAL ;
    PORT
      LAYER M3 ;
        RECT  49.356 105.779 49.374 105.816 ;
    END
  END b[7]
  PIN b[80]
    DIRECTION OUTPUT ;
    USE SIGNAL ;
    PORT
      LAYER M3 ;
        RECT  47.7 105.779 47.718 105.816 ;
    END
  END b[80]
  PIN b[81]
    DIRECTION OUTPUT ;
    USE SIGNAL ;
    PORT
      LAYER M3 ;
        RECT  47.772 105.779 47.79 105.816 ;
    END
  END b[81]
  PIN b[82]
    DIRECTION OUTPUT ;
    USE SIGNAL ;
    PORT
      LAYER M3 ;
        RECT  47.844 105.779 47.862 105.816 ;
    END
  END b[82]
  PIN b[83]
    DIRECTION OUTPUT ;
    USE SIGNAL ;
    PORT
      LAYER M3 ;
        RECT  47.916 105.779 47.934 105.816 ;
    END
  END b[83]
  PIN b[84]
    DIRECTION OUTPUT ;
    USE SIGNAL ;
    PORT
      LAYER M3 ;
        RECT  47.988 105.779 48.006 105.816 ;
    END
  END b[84]
  PIN b[85]
    DIRECTION OUTPUT ;
    USE SIGNAL ;
    PORT
      LAYER M3 ;
        RECT  48.06 105.779 48.078 105.816 ;
    END
  END b[85]
  PIN b[86]
    DIRECTION OUTPUT ;
    USE SIGNAL ;
    PORT
      LAYER M3 ;
        RECT  48.132 105.779 48.15 105.816 ;
    END
  END b[86]
  PIN b[87]
    DIRECTION OUTPUT ;
    USE SIGNAL ;
    PORT
      LAYER M3 ;
        RECT  48.204 105.779 48.222 105.816 ;
    END
  END b[87]
  PIN b[88]
    DIRECTION OUTPUT ;
    USE SIGNAL ;
    PORT
      LAYER M3 ;
        RECT  48.276 105.779 48.294 105.816 ;
    END
  END b[88]
  PIN b[89]
    DIRECTION OUTPUT ;
    USE SIGNAL ;
    PORT
      LAYER M3 ;
        RECT  48.348 105.779 48.366 105.816 ;
    END
  END b[89]
  PIN b[8]
    DIRECTION OUTPUT ;
    USE SIGNAL ;
    PORT
      LAYER M3 ;
        RECT  49.428 105.779 49.446 105.816 ;
    END
  END b[8]
  PIN b[90]
    DIRECTION OUTPUT ;
    USE SIGNAL ;
    PORT
      LAYER M3 ;
        RECT  48.42 105.779 48.438 105.816 ;
    END
  END b[90]
  PIN b[91]
    DIRECTION OUTPUT ;
    USE SIGNAL ;
    PORT
      LAYER M3 ;
        RECT  48.492 105.779 48.51 105.816 ;
    END
  END b[91]
  PIN b[92]
    DIRECTION OUTPUT ;
    USE SIGNAL ;
    PORT
      LAYER M3 ;
        RECT  48.564 105.779 48.582 105.816 ;
    END
  END b[92]
  PIN b[93]
    DIRECTION OUTPUT ;
    USE SIGNAL ;
    PORT
      LAYER M3 ;
        RECT  48.636 105.779 48.654 105.816 ;
    END
  END b[93]
  PIN b[94]
    DIRECTION OUTPUT ;
    USE SIGNAL ;
    PORT
      LAYER M3 ;
        RECT  48.708 105.779 48.726 105.816 ;
    END
  END b[94]
  PIN b[95]
    DIRECTION OUTPUT ;
    USE SIGNAL ;
    PORT
      LAYER M3 ;
        RECT  48.78 105.779 48.798 105.816 ;
    END
  END b[95]
  PIN b[96]
    DIRECTION OUTPUT ;
    USE SIGNAL ;
    PORT
      LAYER M3 ;
        RECT  53.46 105.779 53.478 105.816 ;
    END
  END b[96]
  PIN b[97]
    DIRECTION OUTPUT ;
    USE SIGNAL ;
    PORT
      LAYER M3 ;
        RECT  53.532 105.779 53.55 105.816 ;
    END
  END b[97]
  PIN b[98]
    DIRECTION OUTPUT ;
    USE SIGNAL ;
    PORT
      LAYER M3 ;
        RECT  53.604 105.779 53.622 105.816 ;
    END
  END b[98]
  PIN b[99]
    DIRECTION OUTPUT ;
    USE SIGNAL ;
    PORT
      LAYER M3 ;
        RECT  53.676 105.779 53.694 105.816 ;
    END
  END b[99]
  PIN b[9]
    DIRECTION OUTPUT ;
    USE SIGNAL ;
    PORT
      LAYER M3 ;
        RECT  49.5 105.779 49.518 105.816 ;
    END
  END b[9]
  PIN ck
    DIRECTION INPUT ;
    USE SIGNAL ;
    PORT
      LAYER M4 ;
        RECT  0 54.096 0.084 54.12 ;
    END
  END ck
  PIN ck_o
    DIRECTION OUTPUT ;
    USE SIGNAL ;
    PORT
      LAYER M4 ;
        RECT  0 54.192 0.084 54.216 ;
    END
  END ck_o
  PIN eb
    DIRECTION OUTPUT ;
    USE SIGNAL ;
    PORT
      LAYER M3 ;
        RECT  34.38 105.779 34.398 105.816 ;
    END
  END eb
  PIN en
    DIRECTION INPUT ;
    USE SIGNAL ;
    PORT
      LAYER M4 ;
        RECT  0 54.288 0.084 54.312 ;
    END
  END en
  PIN VDD
    DIRECTION INOUT ;
    USE POWER ;
    PORT
      LAYER M5 ;
        RECT  99.792 2.151 99.912 103.433 ;
        RECT  97.092 2.151 97.212 103.433 ;
        RECT  94.392 2.151 94.512 103.433 ;
        RECT  91.692 2.151 91.812 103.433 ;
        RECT  88.992 2.151 89.112 103.433 ;
        RECT  86.292 2.151 86.412 103.433 ;
        RECT  83.592 2.151 83.712 103.433 ;
        RECT  80.892 2.151 81.012 103.433 ;
        RECT  78.192 2.151 78.312 103.433 ;
        RECT  75.492 2.151 75.612 103.433 ;
        RECT  72.792 2.151 72.912 103.433 ;
        RECT  70.092 2.151 70.212 103.433 ;
        RECT  67.392 2.151 67.512 103.433 ;
        RECT  64.692 2.151 64.812 103.433 ;
        RECT  61.992 2.151 62.112 103.433 ;
        RECT  59.292 2.151 59.412 103.433 ;
        RECT  56.592 2.151 56.712 103.433 ;
        RECT  53.892 2.151 54.012 103.433 ;
        RECT  51.192 2.151 51.312 103.433 ;
        RECT  48.492 2.151 48.612 103.433 ;
        RECT  45.792 2.151 45.912 103.433 ;
        RECT  43.092 2.151 43.212 103.433 ;
        RECT  40.392 2.151 40.512 103.433 ;
        RECT  37.692 2.151 37.812 103.433 ;
        RECT  34.992 2.151 35.112 103.433 ;
        RECT  32.292 2.151 32.412 103.433 ;
        RECT  29.592 2.151 29.712 103.433 ;
        RECT  26.892 2.151 27.012 103.433 ;
        RECT  24.192 2.151 24.312 103.433 ;
        RECT  21.492 2.151 21.612 103.433 ;
        RECT  18.792 2.151 18.912 103.433 ;
        RECT  16.092 2.151 16.212 103.433 ;
        RECT  13.392 2.151 13.512 103.433 ;
        RECT  10.692 2.151 10.812 103.433 ;
        RECT  7.992 2.151 8.112 103.433 ;
        RECT  5.292 2.151 5.412 103.433 ;
        RECT  2.592 2.151 2.712 103.433 ;
    END
  END VDD
  PIN VSS
    DIRECTION INOUT ;
    USE GROUND ;
    PORT
      LAYER M5 ;
        RECT  99.6 2.137 99.72 103.419 ;
        RECT  96.9 2.137 97.02 103.419 ;
        RECT  94.2 2.137 94.32 103.419 ;
        RECT  91.5 2.137 91.62 103.419 ;
        RECT  88.8 2.137 88.92 103.419 ;
        RECT  86.1 2.137 86.22 103.419 ;
        RECT  83.4 2.137 83.52 103.419 ;
        RECT  80.7 2.137 80.82 103.419 ;
        RECT  78 2.137 78.12 103.419 ;
        RECT  75.3 2.137 75.42 103.419 ;
        RECT  72.6 2.137 72.72 103.419 ;
        RECT  69.9 2.137 70.02 103.419 ;
        RECT  67.2 2.137 67.32 103.419 ;
        RECT  64.5 2.137 64.62 103.419 ;
        RECT  61.8 2.137 61.92 103.419 ;
        RECT  59.1 2.137 59.22 103.419 ;
        RECT  56.4 2.137 56.52 103.419 ;
        RECT  53.7 2.137 53.82 103.419 ;
        RECT  51 2.137 51.12 103.419 ;
        RECT  48.3 2.137 48.42 103.419 ;
        RECT  45.6 2.137 45.72 103.419 ;
        RECT  42.9 2.137 43.02 103.419 ;
        RECT  40.2 2.137 40.32 103.419 ;
        RECT  37.5 2.137 37.62 103.419 ;
        RECT  34.8 2.137 34.92 103.419 ;
        RECT  32.1 2.137 32.22 103.419 ;
        RECT  29.4 2.137 29.52 103.419 ;
        RECT  26.7 2.137 26.82 103.419 ;
        RECT  24 2.137 24.12 103.419 ;
        RECT  21.3 2.137 21.42 103.419 ;
        RECT  18.6 2.137 18.72 103.419 ;
        RECT  15.9 2.137 16.02 103.419 ;
        RECT  13.2 2.137 13.32 103.419 ;
        RECT  10.5 2.137 10.62 103.419 ;
        RECT  7.8 2.137 7.92 103.419 ;
        RECT  5.1 2.137 5.22 103.419 ;
        RECT  2.4 2.137 2.52 103.419 ;
    END
  END VSS
  OBS
    LAYER RVTN ;
     RECT  2.16 2.16 101.898 2.295 ;
     RECT  2.16 2.565 101.898 2.835 ;
     RECT  2.16 3.105 101.898 3.375 ;
     RECT  2.16 3.645 101.898 3.915 ;
     RECT  2.16 4.185 101.898 4.455 ;
     RECT  2.16 4.725 101.898 4.995 ;
     RECT  2.16 5.265 101.898 5.535 ;
     RECT  2.16 5.805 101.898 6.075 ;
     RECT  2.16 6.345 101.898 6.615 ;
     RECT  2.16 6.885 101.898 7.155 ;
     RECT  2.16 7.425 101.898 7.695 ;
     RECT  2.16 7.965 101.898 8.235 ;
     RECT  2.16 8.505 101.898 8.775 ;
     RECT  2.16 9.045 101.898 9.315 ;
     RECT  2.16 9.585 101.898 9.855 ;
     RECT  2.16 10.125 101.898 10.395 ;
     RECT  2.16 10.665 101.898 10.935 ;
     RECT  2.16 11.205 101.898 11.475 ;
     RECT  2.16 11.745 101.898 12.015 ;
     RECT  2.16 12.285 101.898 12.555 ;
     RECT  2.16 12.825 101.898 13.095 ;
     RECT  2.16 13.365 101.898 13.635 ;
     RECT  2.16 13.905 101.898 14.175 ;
     RECT  2.16 14.445 101.898 14.715 ;
     RECT  2.16 14.985 101.898 15.255 ;
     RECT  2.16 15.525 101.898 15.795 ;
     RECT  2.16 16.065 101.898 16.335 ;
     RECT  2.16 16.605 101.898 16.875 ;
     RECT  2.16 17.145 101.898 17.415 ;
     RECT  2.16 17.685 101.898 17.955 ;
     RECT  2.16 18.225 101.898 18.495 ;
     RECT  2.16 18.765 101.898 19.035 ;
     RECT  2.16 19.305 101.898 19.575 ;
     RECT  2.16 19.845 101.898 20.115 ;
     RECT  2.16 20.385 101.898 20.655 ;
     RECT  2.16 20.925 101.898 21.195 ;
     RECT  2.16 21.465 101.898 21.735 ;
     RECT  2.16 22.005 101.898 22.275 ;
     RECT  2.16 22.545 101.898 22.815 ;
     RECT  2.16 23.085 101.898 23.355 ;
     RECT  2.16 23.625 101.898 23.895 ;
     RECT  2.16 24.165 101.898 24.435 ;
     RECT  2.16 24.705 101.898 24.975 ;
     RECT  2.16 25.245 101.898 25.515 ;
     RECT  2.16 25.785 101.898 26.055 ;
     RECT  2.16 26.325 101.898 26.595 ;
     RECT  2.16 26.865 101.898 27.135 ;
     RECT  2.16 27.405 101.898 27.675 ;
     RECT  2.16 27.945 101.898 28.215 ;
     RECT  2.16 28.485 101.898 28.755 ;
     RECT  2.16 29.025 101.898 29.295 ;
     RECT  2.16 29.565 101.898 29.835 ;
     RECT  2.16 30.105 101.898 30.375 ;
     RECT  2.16 30.645 101.898 30.915 ;
     RECT  2.16 31.185 101.898 31.455 ;
     RECT  2.16 31.725 101.898 31.995 ;
     RECT  2.16 32.265 101.898 32.535 ;
     RECT  2.16 32.805 101.898 33.075 ;
     RECT  2.16 33.345 101.898 33.615 ;
     RECT  2.16 33.885 101.898 34.155 ;
     RECT  2.16 34.425 101.898 34.695 ;
     RECT  2.16 34.965 101.898 35.235 ;
     RECT  2.16 35.505 101.898 35.775 ;
     RECT  2.16 36.045 101.898 36.315 ;
     RECT  2.16 36.585 101.898 36.855 ;
     RECT  2.16 37.125 101.898 37.395 ;
     RECT  2.16 37.665 101.898 37.935 ;
     RECT  2.16 38.205 101.898 38.475 ;
     RECT  2.16 38.745 101.898 39.015 ;
     RECT  2.16 39.285 101.898 39.555 ;
     RECT  2.16 39.825 101.898 40.095 ;
     RECT  2.16 40.365 101.898 40.635 ;
     RECT  2.16 40.905 101.898 41.175 ;
     RECT  2.16 41.445 101.898 41.715 ;
     RECT  2.16 41.985 101.898 42.255 ;
     RECT  2.16 42.525 101.898 42.795 ;
     RECT  2.16 43.065 101.898 43.335 ;
     RECT  2.16 43.605 101.898 43.875 ;
     RECT  2.16 44.145 101.898 44.415 ;
     RECT  2.16 44.685 101.898 44.955 ;
     RECT  2.16 45.225 101.898 45.495 ;
     RECT  2.16 45.765 101.898 46.035 ;
     RECT  2.16 46.305 101.898 46.575 ;
     RECT  2.16 46.845 101.898 47.115 ;
     RECT  2.16 47.385 101.898 47.655 ;
     RECT  2.16 47.925 101.898 48.195 ;
     RECT  2.16 48.465 101.898 48.735 ;
     RECT  2.16 49.005 101.898 49.275 ;
     RECT  2.16 49.545 101.898 49.815 ;
     RECT  2.16 50.085 101.898 50.355 ;
     RECT  2.16 50.625 101.898 50.895 ;
     RECT  2.16 51.165 101.898 51.435 ;
     RECT  2.16 51.705 101.898 51.975 ;
     RECT  2.16 52.245 101.898 52.515 ;
     RECT  2.16 52.785 101.898 53.055 ;
     RECT  2.16 53.325 101.898 53.595 ;
     RECT  2.16 53.865 101.898 54.135 ;
     RECT  2.16 54.405 101.898 54.675 ;
     RECT  2.16 54.945 101.898 55.215 ;
     RECT  2.16 55.485 101.898 55.755 ;
     RECT  2.16 56.025 101.898 56.295 ;
     RECT  2.16 56.565 101.898 56.835 ;
     RECT  2.16 57.105 101.898 57.375 ;
     RECT  2.16 57.645 101.898 57.915 ;
     RECT  2.16 58.185 101.898 58.455 ;
     RECT  2.16 58.725 101.898 58.995 ;
     RECT  2.16 59.265 101.898 59.535 ;
     RECT  2.16 59.805 101.898 60.075 ;
     RECT  2.16 60.345 101.898 60.615 ;
     RECT  2.16 60.885 101.898 61.155 ;
     RECT  2.16 61.425 101.898 61.695 ;
     RECT  2.16 61.965 101.898 62.235 ;
     RECT  2.16 62.505 101.898 62.775 ;
     RECT  2.16 63.045 101.898 63.315 ;
     RECT  2.16 63.585 101.898 63.855 ;
     RECT  2.16 64.125 101.898 64.395 ;
     RECT  2.16 64.665 101.898 64.935 ;
     RECT  2.16 65.205 101.898 65.475 ;
     RECT  2.16 65.745 101.898 66.015 ;
     RECT  2.16 66.285 101.898 66.555 ;
     RECT  2.16 66.825 101.898 67.095 ;
     RECT  2.16 67.365 101.898 67.635 ;
     RECT  2.16 67.905 101.898 68.175 ;
     RECT  2.16 68.445 101.898 68.715 ;
     RECT  2.16 68.985 101.898 69.255 ;
     RECT  2.16 69.525 101.898 69.795 ;
     RECT  2.16 70.065 101.898 70.335 ;
     RECT  2.16 70.605 101.898 70.875 ;
     RECT  2.16 71.145 101.898 71.415 ;
     RECT  2.16 71.685 101.898 71.955 ;
     RECT  2.16 72.225 101.898 72.495 ;
     RECT  2.16 72.765 101.898 73.035 ;
     RECT  2.16 73.305 101.898 73.575 ;
     RECT  2.16 73.845 101.898 74.115 ;
     RECT  2.16 74.385 101.898 74.655 ;
     RECT  2.16 74.925 101.898 75.195 ;
     RECT  2.16 75.465 101.898 75.735 ;
     RECT  2.16 76.005 101.898 76.275 ;
     RECT  2.16 76.545 101.898 76.815 ;
     RECT  2.16 77.085 101.898 77.355 ;
     RECT  2.16 77.625 101.898 77.895 ;
     RECT  2.16 78.165 101.898 78.435 ;
     RECT  2.16 78.705 101.898 78.975 ;
     RECT  2.16 79.245 101.898 79.515 ;
     RECT  2.16 79.785 101.898 80.055 ;
     RECT  2.16 80.325 101.898 80.595 ;
     RECT  2.16 80.865 101.898 81.135 ;
     RECT  2.16 81.405 101.898 81.675 ;
     RECT  2.16 81.945 101.898 82.215 ;
     RECT  2.16 82.485 101.898 82.755 ;
     RECT  2.16 83.025 101.898 83.295 ;
     RECT  2.16 83.565 101.898 83.835 ;
     RECT  2.16 84.105 101.898 84.375 ;
     RECT  2.16 84.645 101.898 84.915 ;
     RECT  2.16 85.185 101.898 85.455 ;
     RECT  2.16 85.725 101.898 85.995 ;
     RECT  2.16 86.265 101.898 86.535 ;
     RECT  2.16 86.805 101.898 87.075 ;
     RECT  2.16 87.345 101.898 87.615 ;
     RECT  2.16 87.885 101.898 88.155 ;
     RECT  2.16 88.425 101.898 88.695 ;
     RECT  2.16 88.965 101.898 89.235 ;
     RECT  2.16 89.505 101.898 89.775 ;
     RECT  2.16 90.045 101.898 90.315 ;
     RECT  2.16 90.585 101.898 90.855 ;
     RECT  2.16 91.125 101.898 91.395 ;
     RECT  2.16 91.665 101.898 91.935 ;
     RECT  2.16 92.205 101.898 92.475 ;
     RECT  2.16 92.745 101.898 93.015 ;
     RECT  2.16 93.285 101.898 93.555 ;
     RECT  2.16 93.825 101.898 94.095 ;
     RECT  2.16 94.365 101.898 94.635 ;
     RECT  2.16 94.905 101.898 95.175 ;
     RECT  2.16 95.445 101.898 95.715 ;
     RECT  2.16 95.985 101.898 96.255 ;
     RECT  2.16 96.525 101.898 96.795 ;
     RECT  2.16 97.065 101.898 97.335 ;
     RECT  2.16 97.605 101.898 97.875 ;
     RECT  2.16 98.145 101.898 98.415 ;
     RECT  2.16 98.685 101.898 98.955 ;
     RECT  2.16 99.225 101.898 99.495 ;
     RECT  2.16 99.765 101.898 100.035 ;
     RECT  2.16 100.305 101.898 100.575 ;
     RECT  2.16 100.845 101.898 101.115 ;
     RECT  2.16 101.385 101.898 101.655 ;
     RECT  2.16 101.925 101.898 102.195 ;
     RECT  2.16 102.465 101.898 102.735 ;
     RECT  2.16 103.005 101.898 103.275 ;
    LAYER RVTP ;
     RECT  2.16 2.295 101.898 2.565 ;
     RECT  2.16 2.835 101.898 3.105 ;
     RECT  2.16 3.375 101.898 3.645 ;
     RECT  2.16 3.915 101.898 4.185 ;
     RECT  2.16 4.455 101.898 4.725 ;
     RECT  2.16 4.995 101.898 5.265 ;
     RECT  2.16 5.535 101.898 5.805 ;
     RECT  2.16 6.075 101.898 6.345 ;
     RECT  2.16 6.615 101.898 6.885 ;
     RECT  2.16 7.155 101.898 7.425 ;
     RECT  2.16 7.695 101.898 7.965 ;
     RECT  2.16 8.235 101.898 8.505 ;
     RECT  2.16 8.775 101.898 9.045 ;
     RECT  2.16 9.315 101.898 9.585 ;
     RECT  2.16 9.855 101.898 10.125 ;
     RECT  2.16 10.395 101.898 10.665 ;
     RECT  2.16 10.935 101.898 11.205 ;
     RECT  2.16 11.475 101.898 11.745 ;
     RECT  2.16 12.015 101.898 12.285 ;
     RECT  2.16 12.555 101.898 12.825 ;
     RECT  2.16 13.095 101.898 13.365 ;
     RECT  2.16 13.635 101.898 13.905 ;
     RECT  2.16 14.175 101.898 14.445 ;
     RECT  2.16 14.715 101.898 14.985 ;
     RECT  2.16 15.255 101.898 15.525 ;
     RECT  2.16 15.795 101.898 16.065 ;
     RECT  2.16 16.335 101.898 16.605 ;
     RECT  2.16 16.875 101.898 17.145 ;
     RECT  2.16 17.415 101.898 17.685 ;
     RECT  2.16 17.955 101.898 18.225 ;
     RECT  2.16 18.495 101.898 18.765 ;
     RECT  2.16 19.035 101.898 19.305 ;
     RECT  2.16 19.575 101.898 19.845 ;
     RECT  2.16 20.115 101.898 20.385 ;
     RECT  2.16 20.655 101.898 20.925 ;
     RECT  2.16 21.195 101.898 21.465 ;
     RECT  2.16 21.735 101.898 22.005 ;
     RECT  2.16 22.275 101.898 22.545 ;
     RECT  2.16 22.815 101.898 23.085 ;
     RECT  2.16 23.355 101.898 23.625 ;
     RECT  2.16 23.895 101.898 24.165 ;
     RECT  2.16 24.435 101.898 24.705 ;
     RECT  2.16 24.975 101.898 25.245 ;
     RECT  2.16 25.515 101.898 25.785 ;
     RECT  2.16 26.055 101.898 26.325 ;
     RECT  2.16 26.595 101.898 26.865 ;
     RECT  2.16 27.135 101.898 27.405 ;
     RECT  2.16 27.675 101.898 27.945 ;
     RECT  2.16 28.215 101.898 28.485 ;
     RECT  2.16 28.755 101.898 29.025 ;
     RECT  2.16 29.295 101.898 29.565 ;
     RECT  2.16 29.835 101.898 30.105 ;
     RECT  2.16 30.375 101.898 30.645 ;
     RECT  2.16 30.915 101.898 31.185 ;
     RECT  2.16 31.455 101.898 31.725 ;
     RECT  2.16 31.995 101.898 32.265 ;
     RECT  2.16 32.535 101.898 32.805 ;
     RECT  2.16 33.075 101.898 33.345 ;
     RECT  2.16 33.615 101.898 33.885 ;
     RECT  2.16 34.155 101.898 34.425 ;
     RECT  2.16 34.695 101.898 34.965 ;
     RECT  2.16 35.235 101.898 35.505 ;
     RECT  2.16 35.775 101.898 36.045 ;
     RECT  2.16 36.315 101.898 36.585 ;
     RECT  2.16 36.855 101.898 37.125 ;
     RECT  2.16 37.395 101.898 37.665 ;
     RECT  2.16 37.935 101.898 38.205 ;
     RECT  2.16 38.475 101.898 38.745 ;
     RECT  2.16 39.015 101.898 39.285 ;
     RECT  2.16 39.555 101.898 39.825 ;
     RECT  2.16 40.095 101.898 40.365 ;
     RECT  2.16 40.635 101.898 40.905 ;
     RECT  2.16 41.175 101.898 41.445 ;
     RECT  2.16 41.715 101.898 41.985 ;
     RECT  2.16 42.255 101.898 42.525 ;
     RECT  2.16 42.795 101.898 43.065 ;
     RECT  2.16 43.335 101.898 43.605 ;
     RECT  2.16 43.875 101.898 44.145 ;
     RECT  2.16 44.415 101.898 44.685 ;
     RECT  2.16 44.955 101.898 45.225 ;
     RECT  2.16 45.495 101.898 45.765 ;
     RECT  2.16 46.035 101.898 46.305 ;
     RECT  2.16 46.575 101.898 46.845 ;
     RECT  2.16 47.115 101.898 47.385 ;
     RECT  2.16 47.655 101.898 47.925 ;
     RECT  2.16 48.195 101.898 48.465 ;
     RECT  2.16 48.735 101.898 49.005 ;
     RECT  2.16 49.275 101.898 49.545 ;
     RECT  2.16 49.815 101.898 50.085 ;
     RECT  2.16 50.355 101.898 50.625 ;
     RECT  2.16 50.895 101.898 51.165 ;
     RECT  2.16 51.435 101.898 51.705 ;
     RECT  2.16 51.975 101.898 52.245 ;
     RECT  2.16 52.515 101.898 52.785 ;
     RECT  2.16 53.055 101.898 53.325 ;
     RECT  2.16 53.595 101.898 53.865 ;
     RECT  2.16 54.135 101.898 54.405 ;
     RECT  2.16 54.675 101.898 54.945 ;
     RECT  2.16 55.215 101.898 55.485 ;
     RECT  2.16 55.755 101.898 56.025 ;
     RECT  2.16 56.295 101.898 56.565 ;
     RECT  2.16 56.835 101.898 57.105 ;
     RECT  2.16 57.375 101.898 57.645 ;
     RECT  2.16 57.915 101.898 58.185 ;
     RECT  2.16 58.455 101.898 58.725 ;
     RECT  2.16 58.995 101.898 59.265 ;
     RECT  2.16 59.535 101.898 59.805 ;
     RECT  2.16 60.075 101.898 60.345 ;
     RECT  2.16 60.615 101.898 60.885 ;
     RECT  2.16 61.155 101.898 61.425 ;
     RECT  2.16 61.695 101.898 61.965 ;
     RECT  2.16 62.235 101.898 62.505 ;
     RECT  2.16 62.775 101.898 63.045 ;
     RECT  2.16 63.315 101.898 63.585 ;
     RECT  2.16 63.855 101.898 64.125 ;
     RECT  2.16 64.395 101.898 64.665 ;
     RECT  2.16 64.935 101.898 65.205 ;
     RECT  2.16 65.475 101.898 65.745 ;
     RECT  2.16 66.015 101.898 66.285 ;
     RECT  2.16 66.555 101.898 66.825 ;
     RECT  2.16 67.095 101.898 67.365 ;
     RECT  2.16 67.635 101.898 67.905 ;
     RECT  2.16 68.175 101.898 68.445 ;
     RECT  2.16 68.715 101.898 68.985 ;
     RECT  2.16 69.255 101.898 69.525 ;
     RECT  2.16 69.795 101.898 70.065 ;
     RECT  2.16 70.335 101.898 70.605 ;
     RECT  2.16 70.875 101.898 71.145 ;
     RECT  2.16 71.415 101.898 71.685 ;
     RECT  2.16 71.955 101.898 72.225 ;
     RECT  2.16 72.495 101.898 72.765 ;
     RECT  2.16 73.035 101.898 73.305 ;
     RECT  2.16 73.575 101.898 73.845 ;
     RECT  2.16 74.115 101.898 74.385 ;
     RECT  2.16 74.655 101.898 74.925 ;
     RECT  2.16 75.195 101.898 75.465 ;
     RECT  2.16 75.735 101.898 76.005 ;
     RECT  2.16 76.275 101.898 76.545 ;
     RECT  2.16 76.815 101.898 77.085 ;
     RECT  2.16 77.355 101.898 77.625 ;
     RECT  2.16 77.895 101.898 78.165 ;
     RECT  2.16 78.435 101.898 78.705 ;
     RECT  2.16 78.975 101.898 79.245 ;
     RECT  2.16 79.515 101.898 79.785 ;
     RECT  2.16 80.055 101.898 80.325 ;
     RECT  2.16 80.595 101.898 80.865 ;
     RECT  2.16 81.135 101.898 81.405 ;
     RECT  2.16 81.675 101.898 81.945 ;
     RECT  2.16 82.215 101.898 82.485 ;
     RECT  2.16 82.755 101.898 83.025 ;
     RECT  2.16 83.295 101.898 83.565 ;
     RECT  2.16 83.835 101.898 84.105 ;
     RECT  2.16 84.375 101.898 84.645 ;
     RECT  2.16 84.915 101.898 85.185 ;
     RECT  2.16 85.455 101.898 85.725 ;
     RECT  2.16 85.995 101.898 86.265 ;
     RECT  2.16 86.535 101.898 86.805 ;
     RECT  2.16 87.075 101.898 87.345 ;
     RECT  2.16 87.615 101.898 87.885 ;
     RECT  2.16 88.155 101.898 88.425 ;
     RECT  2.16 88.695 101.898 88.965 ;
     RECT  2.16 89.235 101.898 89.505 ;
     RECT  2.16 89.775 101.898 90.045 ;
     RECT  2.16 90.315 101.898 90.585 ;
     RECT  2.16 90.855 101.898 91.125 ;
     RECT  2.16 91.395 101.898 91.665 ;
     RECT  2.16 91.935 101.898 92.205 ;
     RECT  2.16 92.475 101.898 92.745 ;
     RECT  2.16 93.015 101.898 93.285 ;
     RECT  2.16 93.555 101.898 93.825 ;
     RECT  2.16 94.095 101.898 94.365 ;
     RECT  2.16 94.635 101.898 94.905 ;
     RECT  2.16 95.175 101.898 95.445 ;
     RECT  2.16 95.715 101.898 95.985 ;
     RECT  2.16 96.255 101.898 96.525 ;
     RECT  2.16 96.795 101.898 97.065 ;
     RECT  2.16 97.335 101.898 97.605 ;
     RECT  2.16 97.875 101.898 98.145 ;
     RECT  2.16 98.415 101.898 98.685 ;
     RECT  2.16 98.955 101.898 99.225 ;
     RECT  2.16 99.495 101.898 99.765 ;
     RECT  2.16 100.035 101.898 100.305 ;
     RECT  2.16 100.575 101.898 100.845 ;
     RECT  2.16 101.115 101.898 101.385 ;
     RECT  2.16 101.655 101.898 101.925 ;
     RECT  2.16 102.195 101.898 102.465 ;
     RECT  2.16 102.735 101.898 103.005 ;
     RECT  2.16 103.275 101.898 103.41 ;
    LAYER M1 ;
     RECT  2.16 2.151 101.898 103.419 ;
    LAYER M2 ;
     RECT  34.447 105.75 34.807 105.768 ;
     RECT  2.16 2.151 34.843 103.419 ;
     RECT  34.807 105.516 34.907 105.768 ;
     RECT  34.907 105.606 34.979 105.768 ;
     RECT  34.979 105.642 35.231 105.768 ;
     RECT  35.231 105.678 36.455 105.768 ;
     RECT  34.843 2.151 36.535 103.536 ;
     RECT  36.535 2.151 37.039 103.608 ;
     RECT  36.455 105.75 37.615 105.768 ;
     RECT  37.615 105.516 37.859 105.768 ;
     RECT  37.859 105.561 38.723 105.768 ;
     RECT  38.723 105.678 39.487 105.768 ;
     RECT  37.039 2.151 39.919 103.734 ;
     RECT  39.487 105.561 39.991 105.768 ;
     RECT  39.919 2.151 40.063 104.04 ;
     RECT  39.991 104.868 40.063 105.768 ;
     RECT  40.063 2.151 40.451 105.768 ;
     RECT  40.451 105.714 40.631 105.768 ;
     RECT  40.451 2.151 41.351 104.886 ;
     RECT  40.631 105.75 41.647 105.768 ;
     RECT  41.647 105.516 41.819 105.768 ;
     RECT  41.351 2.151 41.927 104.31 ;
     RECT  41.819 105.642 42.583 105.768 ;
     RECT  42.583 105.516 42.755 105.768 ;
     RECT  41.927 2.151 43.015 104.04 ;
     RECT  42.755 105.561 43.331 105.768 ;
     RECT  43.015 2.151 43.879 104.274 ;
     RECT  43.879 2.151 44.015 104.346 ;
     RECT  44.015 2.151 44.159 104.04 ;
     RECT  43.331 105.678 44.455 105.768 ;
     RECT  44.455 105.561 45.031 105.768 ;
     RECT  45.031 105.516 45.347 105.768 ;
     RECT  45.347 105.561 46.031 105.768 ;
     RECT  46.031 105.678 46.067 105.768 ;
     RECT  44.159 2.151 46.543 103.536 ;
     RECT  46.067 105.714 46.795 105.768 ;
     RECT  46.795 105.561 47.335 105.768 ;
     RECT  47.335 105.516 47.479 105.768 ;
     RECT  47.479 105.444 48.271 105.768 ;
     RECT  48.271 105.408 48.443 105.768 ;
     RECT  46.543 2.151 49.019 104.04 ;
     RECT  48.443 105.561 49.595 105.768 ;
     RECT  49.595 105.606 50.791 105.768 ;
     RECT  49.019 2.151 50.827 103.536 ;
     RECT  50.827 2.151 50.963 103.644 ;
     RECT  50.791 105.516 51.079 105.768 ;
     RECT  51.079 105.48 51.179 105.768 ;
     RECT  51.179 105.561 52.331 105.768 ;
     RECT  51.223 104.292 52.511 104.31 ;
     RECT  52.331 105.606 54.139 105.768 ;
     RECT  54.139 105.561 54.707 105.768 ;
     RECT  50.963 2.151 54.787 103.536 ;
     RECT  54.787 2.151 54.959 104.274 ;
     RECT  54.707 105.606 54.995 105.768 ;
     RECT  54.995 105.678 55.939 105.768 ;
     RECT  54.959 2.151 56.011 103.536 ;
     RECT  55.939 105.561 56.011 105.768 ;
     RECT  56.011 105.516 56.219 105.768 ;
     RECT  56.011 2.151 56.687 103.734 ;
     RECT  56.219 105.678 56.795 105.768 ;
     RECT  56.795 105.75 57.559 105.768 ;
     RECT  57.559 105.516 57.731 105.768 ;
     RECT  57.731 105.561 58.091 105.768 ;
     RECT  58.091 105.606 59.503 105.768 ;
     RECT  59.503 105.516 59.783 105.768 ;
     RECT  59.783 105.561 60.035 105.768 ;
     RECT  60.035 105.642 60.179 105.768 ;
     RECT  60.179 105.75 60.979 105.768 ;
     RECT  60.979 105.516 61.159 105.768 ;
     RECT  61.159 105.444 61.583 105.768 ;
     RECT  56.687 2.151 61.591 103.536 ;
     RECT  61.583 105.516 62.483 105.768 ;
     RECT  62.483 105.561 62.699 105.768 ;
     RECT  62.699 105.678 63.095 105.768 ;
     RECT  63.095 105.75 63.275 105.768 ;
     RECT  61.591 2.151 63.887 104.04 ;
     RECT  63.887 2.151 65.579 103.572 ;
     RECT  65.579 2.151 77.351 103.536 ;
     RECT  77.351 2.151 101.898 103.419 ;
     RECT  101.898 20.124 102.515 79.776 ;
     RECT  102.515 39.87 102.587 79.776 ;
     RECT  102.515 20.124 102.623 38.844 ;
     RECT  102.587 41.688 102.623 79.776 ;
     RECT  102.623 22.896 102.659 23.994 ;
     RECT  102.623 25.83 102.659 31.014 ;
     RECT  102.623 35.514 102.659 36.954 ;
     RECT  102.623 43.686 102.659 44.514 ;
     RECT  102.623 45.27 102.659 46.836 ;
     RECT  102.623 57.384 102.659 69.786 ;
     RECT  102.623 79.416 102.659 79.776 ;
     RECT  102.659 30.771 102.695 30.978 ;
     RECT  102.623 47.736 102.695 51.264 ;
     RECT  102.659 57.384 102.695 62.568 ;
     RECT  102.659 63.324 102.695 69.786 ;
     RECT  102.659 79.416 102.695 79.47 ;
     RECT  102.695 47.736 102.731 51.228 ;
     RECT  102.695 30.96 102.839 30.978 ;
     RECT  102.695 66.798 103.091 69.786 ;
     RECT  102.623 20.124 103.127 22.104 ;
     RECT  102.659 22.896 103.163 23.454 ;
     RECT  102.623 24.75 103.163 24.804 ;
     RECT  102.623 31.932 103.163 34.452 ;
     RECT  103.127 20.124 103.199 22.068 ;
     RECT  103.163 24.786 103.199 24.804 ;
     RECT  102.659 25.83 103.199 27.504 ;
     RECT  102.659 28.26 103.199 29.934 ;
     RECT  103.163 31.932 103.199 34.416 ;
     RECT  102.623 38.106 103.199 38.844 ;
     RECT  102.587 39.87 103.199 39.888 ;
     RECT  102.587 40.644 103.199 40.932 ;
     RECT  102.623 41.688 103.199 42.714 ;
     RECT  102.659 43.686 103.199 44.406 ;
     RECT  102.659 45.27 103.199 46.638 ;
     RECT  102.731 47.736 103.199 48.564 ;
     RECT  102.731 49.32 103.199 51.228 ;
     RECT  102.623 52.146 103.199 54.972 ;
     RECT  102.623 55.764 103.199 56.286 ;
     RECT  102.695 57.456 103.199 62.028 ;
     RECT  102.695 63.324 103.199 66.006 ;
     RECT  103.091 67.068 103.199 69.786 ;
     RECT  102.623 70.65 103.199 71.982 ;
     RECT  102.623 73.116 103.199 74.484 ;
     RECT  102.623 75.276 103.199 75.834 ;
     RECT  102.623 76.788 103.199 77.616 ;
     RECT  102.695 79.416 103.199 79.434 ;
     RECT  103.199 21.816 103.235 21.834 ;
     RECT  103.163 23.058 103.235 23.454 ;
     RECT  103.199 26.136 103.235 26.964 ;
     RECT  103.199 29.646 103.235 29.898 ;
     RECT  103.199 33.786 103.235 33.804 ;
     RECT  102.659 35.514 103.235 36.342 ;
     RECT  103.199 38.106 103.235 38.304 ;
     RECT  103.199 40.68 103.235 40.896 ;
     RECT  103.199 42.696 103.235 42.714 ;
     RECT  103.199 43.848 103.235 44.334 ;
     RECT  103.199 46.548 103.235 46.566 ;
     RECT  103.199 48.276 103.235 48.492 ;
     RECT  103.199 52.146 103.235 52.164 ;
     RECT  103.199 54.756 103.235 54.774 ;
     RECT  103.199 57.456 103.235 57.474 ;
     RECT  103.199 58.698 103.235 59.328 ;
     RECT  103.199 62.01 103.235 62.028 ;
     RECT  103.199 64.476 103.235 65.268 ;
     RECT  103.199 68.49 103.235 68.544 ;
     RECT  103.199 70.956 103.235 70.974 ;
     RECT  103.199 71.964 103.235 71.982 ;
     RECT  103.199 73.116 103.235 73.134 ;
     RECT  103.199 74.196 103.235 74.484 ;
     RECT  103.199 76.788 103.235 76.806 ;
     RECT  103.235 29.88 103.271 29.898 ;
     RECT  103.235 35.514 103.271 35.532 ;
     RECT  103.235 36.324 103.271 36.342 ;
     RECT  103.235 38.286 103.271 38.304 ;
     RECT  103.235 40.68 103.271 40.698 ;
     RECT  103.235 48.474 103.271 48.492 ;
     RECT  103.199 50.832 103.271 50.85 ;
     RECT  103.199 63.324 103.271 63.576 ;
     RECT  103.235 64.746 103.271 64.764 ;
     RECT  103.235 74.196 103.271 74.214 ;
     RECT  103.235 68.49 103.307 68.508 ;
     RECT  103.235 58.698 103.991 58.716 ;
     RECT  103.963 25.146 104.063 25.164 ;
     RECT  103.963 32.076 104.063 32.094 ;
     RECT  103.963 42.066 104.063 42.084 ;
     RECT  103.963 62.046 104.063 62.064 ;
     RECT  103.963 66.996 104.063 67.014 ;
    LAYER M3 ;
     RECT  2.415 2.143 2.505 2.413 ;
     RECT  5.115 2.143 5.205 2.413 ;
     RECT  7.815 2.143 7.905 2.413 ;
     RECT  10.515 2.143 10.605 2.413 ;
     RECT  13.215 2.143 13.305 2.413 ;
     RECT  15.915 2.143 16.005 2.413 ;
     RECT  18.615 2.143 18.705 2.413 ;
     RECT  21.315 2.143 21.405 2.413 ;
     RECT  24.015 2.143 24.105 2.413 ;
     RECT  26.715 2.143 26.805 2.413 ;
     RECT  29.415 2.143 29.505 2.413 ;
     RECT  32.115 2.143 32.205 2.413 ;
     RECT  34.815 2.143 34.905 2.413 ;
     RECT  37.515 2.143 37.605 2.413 ;
     RECT  40.215 2.143 40.305 2.413 ;
     RECT  42.915 2.143 43.005 2.413 ;
     RECT  45.615 2.143 45.705 2.413 ;
     RECT  48.315 2.143 48.405 2.413 ;
     RECT  51.015 2.143 51.105 2.413 ;
     RECT  53.715 2.143 53.805 2.413 ;
     RECT  56.415 2.143 56.505 2.413 ;
     RECT  59.115 2.143 59.205 2.413 ;
     RECT  61.815 2.143 61.905 2.413 ;
     RECT  64.515 2.143 64.605 2.413 ;
     RECT  67.215 2.143 67.305 2.413 ;
     RECT  69.915 2.143 70.005 2.413 ;
     RECT  72.615 2.143 72.705 2.413 ;
     RECT  75.315 2.143 75.405 2.413 ;
     RECT  78.015 2.143 78.105 2.413 ;
     RECT  80.715 2.143 80.805 2.413 ;
     RECT  83.415 2.143 83.505 2.413 ;
     RECT  86.115 2.143 86.205 2.413 ;
     RECT  88.815 2.143 88.905 2.413 ;
     RECT  91.515 2.143 91.605 2.413 ;
     RECT  94.215 2.143 94.305 2.413 ;
     RECT  96.915 2.143 97.005 2.413 ;
     RECT  99.615 2.143 99.705 2.413 ;
     RECT  99.615 2.413 99.897 20.011 ;
     RECT  99.615 20.011 100.098 20.047 ;
     RECT  99.615 20.047 100.818 20.083 ;
     RECT  101.628 20.011 101.646 20.083 ;
     RECT  99.615 20.083 101.646 20.107 ;
     RECT  98.028 20.011 98.046 20.119 ;
     RECT  86.115 2.413 86.397 20.191 ;
     RECT  96.915 2.413 97.197 20.191 ;
     RECT  98.028 20.119 98.766 20.191 ;
     RECT  99.615 20.107 102.042 20.281 ;
     RECT  99.504 20.281 102.042 20.299 ;
     RECT  103.176 19.915 103.194 20.299 ;
     RECT  94.215 2.413 94.497 20.389 ;
     RECT  94.215 20.389 94.662 20.425 ;
     RECT  96.876 20.191 98.766 20.461 ;
     RECT  99.504 20.299 103.194 20.461 ;
     RECT  94.215 20.425 94.914 20.551 ;
     RECT  95.904 20.191 96.066 20.551 ;
     RECT  96.876 20.461 103.194 20.551 ;
     RECT  95.904 20.551 103.194 20.695 ;
     RECT  41.652 20.695 41.67 20.849 ;
     RECT  38.772 20.821 38.79 20.921 ;
     RECT  75.315 2.413 75.597 20.929 ;
     RECT  85.68 20.191 86.397 20.965 ;
     RECT  94.215 20.551 95.094 21.115 ;
     RECT  95.832 20.695 103.194 21.115 ;
     RECT  85.032 20.965 86.397 21.263 ;
     RECT  78.015 2.413 78.297 21.433 ;
     RECT  80.715 2.413 80.997 21.505 ;
     RECT  67.215 2.413 67.497 21.541 ;
     RECT  35.928 21.091 35.946 21.631 ;
     RECT  36.756 20.821 36.774 21.631 ;
     RECT  78.015 21.433 78.678 21.659 ;
     RECT  80.676 21.505 80.997 21.811 ;
     RECT  94.215 21.115 103.194 21.811 ;
     RECT  92.916 21.505 92.934 21.839 ;
     RECT  45.615 2.413 45.897 22.081 ;
     RECT  90.684 22.009 90.702 22.109 ;
     RECT  34.815 2.413 35.097 22.207 ;
     RECT  35.928 21.631 36.774 22.207 ;
     RECT  80.604 21.811 80.997 22.343 ;
     RECT  45.615 22.081 46.062 22.379 ;
     RECT  34.815 22.207 36.774 22.441 ;
     RECT  37.515 2.413 37.797 22.441 ;
     RECT  78.015 21.659 78.297 22.441 ;
     RECT  80.715 22.343 80.997 22.441 ;
     RECT  74.988 20.929 75.597 22.477 ;
     RECT  78.015 22.441 78.75 22.541 ;
     RECT  80.715 22.441 81.09 22.541 ;
     RECT  86.04 21.263 86.397 22.541 ;
     RECT  45.615 22.379 45.897 22.855 ;
     RECT  94.215 21.811 103.23 22.925 ;
     RECT  42.915 2.413 43.197 22.981 ;
     RECT  45.432 22.855 45.897 23.009 ;
     RECT  42.768 22.981 43.197 23.081 ;
     RECT  102.492 22.925 103.23 23.117 ;
     RECT  92.628 22.081 92.646 23.161 ;
     RECT  90.648 23.053 90.666 23.315 ;
     RECT  83.415 2.413 83.697 23.521 ;
     RECT  86.115 22.541 86.397 23.521 ;
     RECT  34.815 22.441 37.797 23.563 ;
     RECT  38.592 22.171 38.61 23.563 ;
     RECT  102.564 23.117 103.23 23.597 ;
     RECT  86.115 23.521 86.634 23.621 ;
     RECT  91.515 2.413 91.797 23.629 ;
     RECT  92.628 23.161 92.718 23.629 ;
     RECT  59.115 2.413 59.397 23.701 ;
     RECT  60.552 23.665 60.57 23.701 ;
     RECT  80.715 22.541 80.997 23.701 ;
     RECT  60.552 23.701 60.678 23.791 ;
     RECT  78.015 22.541 78.678 23.791 ;
     RECT  60.552 23.791 60.75 23.819 ;
     RECT  80.715 23.701 81.378 23.819 ;
     RECT  94.215 22.925 101.502 23.837 ;
     RECT  83.415 23.521 83.826 23.855 ;
     RECT  58.716 23.701 59.397 23.891 ;
     RECT  60.732 23.819 60.75 23.891 ;
     RECT  78.015 23.791 78.75 23.927 ;
     RECT  67.215 21.541 67.554 24.061 ;
     RECT  90.72 23.971 90.738 24.169 ;
     RECT  90.684 24.169 90.738 24.17 ;
     RECT  85.032 21.263 85.05 24.241 ;
     RECT  86.115 23.621 86.397 24.241 ;
     RECT  94.215 23.837 100.674 24.241 ;
     RECT  101.412 23.837 101.502 24.241 ;
     RECT  102.564 23.597 102.654 24.331 ;
     RECT  94.176 24.241 100.674 24.475 ;
     RECT  101.412 24.241 101.682 24.523 ;
     RECT  102.564 24.331 103.194 24.523 ;
     RECT  93.456 24.475 100.674 24.601 ;
     RECT  101.412 24.523 103.194 24.601 ;
     RECT  93.456 24.601 103.194 24.665 ;
     RECT  56.415 2.413 56.697 24.709 ;
     RECT  85.032 24.241 86.397 24.781 ;
     RECT  90.684 24.17 90.702 24.809 ;
     RECT  72.615 2.413 72.897 24.907 ;
     RECT  103.968 25.099 103.986 25.141 ;
     RECT  103.968 25.141 104.058 25.169 ;
     RECT  104.04 25.169 104.058 25.181 ;
     RECT  93.744 24.665 103.194 25.475 ;
     RECT  82.332 23.323 82.35 25.519 ;
     RECT  34.815 23.563 38.61 25.555 ;
     RECT  83.415 23.855 83.697 25.591 ;
     RECT  84.672 24.781 86.397 25.591 ;
     RECT  34.815 25.555 38.862 25.681 ;
     RECT  102.492 25.475 103.194 25.852 ;
     RECT  61.815 2.413 62.097 25.861 ;
     RECT  83.415 25.591 86.397 25.861 ;
     RECT  90.648 25.789 90.666 25.889 ;
     RECT  83.415 25.861 86.562 25.951 ;
     RECT  34.815 25.681 39.15 26.023 ;
     RECT  82.332 25.519 82.674 26.023 ;
     RECT  83.415 25.951 86.67 26.023 ;
     RECT  82.332 26.023 86.67 26.051 ;
     RECT  34.815 26.023 39.474 26.059 ;
     RECT  40.215 2.413 40.497 26.059 ;
     RECT  102.492 25.852 103.23 26.093 ;
     RECT  82.332 26.051 85.194 26.123 ;
     RECT  85.968 26.051 86.67 26.123 ;
     RECT  34.815 26.059 40.497 26.159 ;
     RECT  61.38 25.861 62.097 26.159 ;
     RECT  93.744 25.475 101.574 26.347 ;
     RECT  47.484 22.045 47.502 26.491 ;
     RECT  61.815 26.159 62.097 26.491 ;
     RECT  69.915 2.413 70.197 26.491 ;
     RECT  78.015 23.927 78.297 26.491 ;
     RECT  86.115 26.123 86.67 26.491 ;
     RECT  90.684 26.401 90.702 26.555 ;
     RECT  46.764 26.491 47.502 26.621 ;
     RECT  54.72 26.491 54.738 26.621 ;
     RECT  61.815 26.491 62.73 26.621 ;
     RECT  69.915 26.491 70.722 26.621 ;
     RECT  78.015 26.491 78.678 26.621 ;
     RECT  86.115 26.491 86.706 26.621 ;
     RECT  86.115 26.621 86.67 26.627 ;
     RECT  93.744 26.347 102.042 26.824 ;
     RECT  103.176 26.093 103.23 26.824 ;
     RECT  45.615 23.009 45.897 26.941 ;
     RECT  93.744 26.824 103.23 26.969 ;
     RECT  82.332 26.123 82.35 27.103 ;
     RECT  83.304 26.123 85.194 27.103 ;
     RECT  90.648 26.869 90.666 27.131 ;
     RECT  45.468 26.941 45.897 27.211 ;
     RECT  88.815 2.413 89.097 27.985 ;
     RECT  91.515 23.629 92.718 28.021 ;
     RECT  93.744 26.969 103.194 28.021 ;
     RECT  45.18 27.211 45.897 28.291 ;
     RECT  46.62 27.607 46.638 28.291 ;
     RECT  45.18 28.291 46.638 28.831 ;
     RECT  47.484 26.621 47.502 28.831 ;
     RECT  61.815 26.621 62.097 29.101 ;
     RECT  90.648 28.561 90.666 29.101 ;
     RECT  90.648 29.101 90.738 29.219 ;
     RECT  90.72 29.219 90.738 29.291 ;
     RECT  91.515 28.021 103.194 29.641 ;
     RECT  40.215 26.159 40.497 29.731 ;
     RECT  91.515 29.641 103.23 29.759 ;
     RECT  61.815 29.101 62.658 29.767 ;
     RECT  96.048 29.759 103.23 29.875 ;
     RECT  61.815 29.767 62.73 30.109 ;
     RECT  96.048 29.875 103.266 30.125 ;
     RECT  96.048 30.125 102.834 30.173 ;
     RECT  61.815 30.109 62.91 30.181 ;
     RECT  91.515 29.759 95.202 30.541 ;
     RECT  91.515 30.541 95.274 30.649 ;
     RECT  96.048 30.173 101.466 30.649 ;
     RECT  72.576 24.907 72.897 30.721 ;
     RECT  74.376 22.477 75.597 30.811 ;
     RECT  78.015 26.621 78.297 30.811 ;
     RECT  86.115 26.627 86.397 30.811 ;
     RECT  88.596 27.985 89.097 30.839 ;
     RECT  73.872 30.811 75.597 30.941 ;
     RECT  78.015 30.811 78.678 30.941 ;
     RECT  86.115 30.811 86.67 30.941 ;
     RECT  102.492 30.173 102.834 30.983 ;
     RECT  72.324 30.721 72.897 30.989 ;
     RECT  61.815 30.181 62.946 30.991 ;
     RECT  91.515 30.649 101.466 30.991 ;
     RECT  103.896 30.859 103.914 31.037 ;
     RECT  91.515 30.991 101.574 31.051 ;
     RECT  102.492 30.983 102.654 31.051 ;
     RECT  72.396 30.989 72.897 31.109 ;
     RECT  61.815 30.991 63.594 31.423 ;
     RECT  72.504 31.109 72.897 31.531 ;
     RECT  91.515 31.051 102.654 31.723 ;
     RECT  61.815 31.423 63.666 31.765 ;
     RECT  64.515 2.413 64.797 31.765 ;
     RECT  78.015 30.941 78.297 31.801 ;
     RECT  91.515 31.723 102.69 31.819 ;
     RECT  72.504 31.531 72.954 31.919 ;
     RECT  91.515 31.819 103.194 31.991 ;
     RECT  104.04 32.059 104.058 32.071 ;
     RECT  103.968 32.071 104.058 32.099 ;
     RECT  103.968 32.099 103.986 32.141 ;
     RECT  72.504 31.919 72.897 32.237 ;
     RECT  72.54 32.237 72.897 32.261 ;
     RECT  91.515 31.991 101.682 32.269 ;
     RECT  42.915 23.081 43.197 32.305 ;
     RECT  44.208 30.649 44.226 32.305 ;
     RECT  55.044 32.269 55.062 32.341 ;
     RECT  90.792 32.269 101.682 32.341 ;
     RECT  90.72 32.341 101.682 32.369 ;
     RECT  34.815 26.159 39.474 32.431 ;
     RECT  90.72 32.369 90.738 32.459 ;
     RECT  91.515 32.369 101.682 32.459 ;
     RECT  53.715 2.413 53.997 32.467 ;
     RECT  51.015 2.413 51.297 32.611 ;
     RECT  59.115 23.891 59.397 32.809 ;
     RECT  56.415 24.709 57.114 32.845 ;
     RECT  58.392 32.809 59.397 33.007 ;
     RECT  90.684 32.575 90.702 33.035 ;
     RECT  102.492 31.991 103.194 33.071 ;
     RECT  53.172 32.467 53.997 33.115 ;
     RECT  55.044 32.341 55.386 33.385 ;
     RECT  56.232 32.845 57.114 33.385 ;
     RECT  57.996 33.007 59.397 33.421 ;
     RECT  52.632 33.115 53.997 33.547 ;
     RECT  102.564 33.071 103.194 33.781 ;
     RECT  55.044 33.385 57.114 33.889 ;
     RECT  54.972 33.889 57.114 33.961 ;
     RECT  57.852 33.421 59.397 33.961 ;
     RECT  102.564 33.781 103.23 33.965 ;
     RECT  102.564 33.965 103.194 34.027 ;
     RECT  70.992 33.691 71.01 34.079 ;
     RECT  52.092 33.547 53.997 34.087 ;
     RECT  54.972 33.961 59.397 34.087 ;
     RECT  50.616 32.611 51.297 34.123 ;
     RECT  91.515 32.459 101.646 34.219 ;
     RECT  102.492 34.027 103.194 34.219 ;
     RECT  90.648 34.231 90.666 34.429 ;
     RECT  90.648 34.429 90.738 34.457 ;
     RECT  90.72 34.457 90.738 34.501 ;
     RECT  91.515 34.219 103.194 34.501 ;
     RECT  90.72 34.501 103.194 34.529 ;
     RECT  50.256 34.123 51.297 34.591 ;
     RECT  52.092 34.087 59.397 34.591 ;
     RECT  90.792 34.529 103.194 34.619 ;
     RECT  88.668 30.839 89.097 34.771 ;
     RECT  88.596 34.771 89.097 34.889 ;
     RECT  78.015 31.801 78.354 34.897 ;
     RECT  86.115 30.941 86.397 34.897 ;
     RECT  86.115 34.897 86.67 35.069 ;
     RECT  91.515 34.619 103.194 35.275 ;
     RECT  91.515 35.275 103.266 35.303 ;
     RECT  67.215 24.061 68.202 35.437 ;
     RECT  66.708 35.437 68.202 35.537 ;
     RECT  42.915 32.305 44.226 35.707 ;
     RECT  40.215 29.731 40.986 35.851 ;
     RECT  42.804 35.707 44.226 36.049 ;
     RECT  45.18 28.831 47.502 36.049 ;
     RECT  91.515 35.303 101.43 36.139 ;
     RECT  102.456 35.303 103.266 36.139 ;
     RECT  40.215 35.851 41.634 36.283 ;
     RECT  90.648 36.247 90.666 36.347 ;
     RECT  91.515 36.139 103.266 36.347 ;
     RECT  40.215 36.283 41.886 36.355 ;
     RECT  42.804 36.049 47.502 36.355 ;
     RECT  74.376 30.941 75.597 36.787 ;
     RECT  77.184 26.329 77.202 36.859 ;
     RECT  78.015 34.897 78.678 36.859 ;
     RECT  82.332 27.103 85.194 36.887 ;
     RECT  91.515 36.347 102.654 37.133 ;
     RECT  77.184 36.859 78.678 37.157 ;
     RECT  67.215 35.537 68.202 37.165 ;
     RECT  90.72 37.399 90.738 37.471 ;
     RECT  91.515 37.133 102.618 37.471 ;
     RECT  67.14 37.165 68.202 37.589 ;
     RECT  90.72 37.471 102.618 37.625 ;
     RECT  61.815 31.765 64.797 37.741 ;
     RECT  65.808 23.863 65.826 37.741 ;
     RECT  90.72 37.625 90.738 37.741 ;
     RECT  90.648 37.741 90.738 37.769 ;
     RECT  61.815 37.741 65.826 37.859 ;
     RECT  90.648 37.769 90.666 37.859 ;
     RECT  91.515 37.625 102.618 37.867 ;
     RECT  91.515 37.867 103.194 37.931 ;
     RECT  102.6 37.931 103.194 37.963 ;
     RECT  102.6 37.963 103.23 38.155 ;
     RECT  102.6 38.155 103.266 38.309 ;
     RECT  69.084 23.323 69.102 38.551 ;
     RECT  69.915 26.621 70.197 38.551 ;
     RECT  88.668 34.889 89.097 38.713 ;
     RECT  40.215 36.355 47.502 38.947 ;
     RECT  48.315 2.413 48.597 38.947 ;
     RECT  91.515 37.931 101.502 38.983 ;
     RECT  90.72 38.947 90.738 39.019 ;
     RECT  67.215 37.589 68.202 39.055 ;
     RECT  69.084 38.551 70.197 39.055 ;
     RECT  91.515 38.983 101.574 39.115 ;
     RECT  102.6 38.309 103.194 39.115 ;
     RECT  67.215 39.055 70.197 39.181 ;
     RECT  66.708 39.181 70.197 39.281 ;
     RECT  90.648 39.019 90.738 39.523 ;
     RECT  90.648 39.523 90.774 39.659 ;
     RECT  90.648 39.659 90.738 39.785 ;
     RECT  90.648 39.785 90.666 39.893 ;
     RECT  34.632 32.431 39.474 39.991 ;
     RECT  40.215 38.947 48.597 39.991 ;
     RECT  91.515 39.115 103.194 40.163 ;
     RECT  60.12 35.311 60.138 40.171 ;
     RECT  61.056 26.563 61.074 40.171 ;
     RECT  103.176 40.163 103.194 40.363 ;
     RECT  34.632 39.991 48.597 40.651 ;
     RECT  103.176 40.363 103.266 40.703 ;
     RECT  103.176 40.703 103.23 40.901 ;
     RECT  91.515 40.163 102.042 41.131 ;
     RECT  103.176 40.901 103.194 41.131 ;
     RECT  34.632 40.651 48.654 41.143 ;
     RECT  78.015 37.157 78.678 41.251 ;
     RECT  78.015 41.251 78.894 41.341 ;
     RECT  50.256 34.591 59.397 41.449 ;
     RECT  34.632 41.143 48.906 41.521 ;
     RECT  49.644 41.449 59.397 41.521 ;
     RECT  90.684 41.683 90.702 41.782 ;
     RECT  90.648 41.782 90.702 42.053 ;
     RECT  104.04 42.043 104.058 42.061 ;
     RECT  103.968 42.061 104.058 42.089 ;
     RECT  103.968 42.089 103.986 42.125 ;
     RECT  91.515 41.131 103.194 42.571 ;
     RECT  91.515 42.571 103.23 42.593 ;
     RECT  91.515 42.593 101.754 42.629 ;
     RECT  102.528 42.593 103.23 42.719 ;
     RECT  90.684 42.053 90.702 42.989 ;
     RECT  91.515 42.629 101.682 42.989 ;
     RECT  102.528 42.719 103.194 43.259 ;
     RECT  102.564 43.259 103.194 43.708 ;
     RECT  91.515 42.989 101.502 43.799 ;
     RECT  90.648 43.681 90.666 44.069 ;
     RECT  77.184 37.157 77.202 44.077 ;
     RECT  78.015 41.341 78.966 44.077 ;
     RECT  102.564 43.708 103.23 44.104 ;
     RECT  77.184 44.077 78.966 44.411 ;
     RECT  101.916 44.104 103.23 44.429 ;
     RECT  91.515 43.799 100.89 45.067 ;
     RECT  101.916 44.429 102.654 45.067 ;
     RECT  91.515 45.067 102.654 45.265 ;
     RECT  91.515 45.265 103.194 45.773 ;
     RECT  90.648 45.769 90.666 45.841 ;
     RECT  90.648 45.841 90.738 45.869 ;
     RECT  102.492 45.773 103.194 45.869 ;
     RECT  90.72 45.869 90.738 46.031 ;
     RECT  102.636 45.869 103.194 46.507 ;
     RECT  102.636 46.507 103.23 46.571 ;
     RECT  102.636 46.571 103.194 46.603 ;
     RECT  102.6 46.603 103.194 46.643 ;
     RECT  91.515 45.773 101.502 46.699 ;
     RECT  102.6 46.643 102.654 46.699 ;
     RECT  91.515 46.699 102.654 47.467 ;
     RECT  91.515 47.467 103.194 47.723 ;
     RECT  90.648 47.461 90.666 47.731 ;
     RECT  60.12 40.171 61.074 48.139 ;
     RECT  61.815 37.859 64.797 48.139 ;
     RECT  102.024 47.723 103.194 48.139 ;
     RECT  34.632 41.521 59.397 48.235 ;
     RECT  60.12 48.139 64.797 48.235 ;
     RECT  102.024 48.139 103.23 48.469 ;
     RECT  91.515 47.723 100.998 48.541 ;
     RECT  102.024 48.469 103.266 48.541 ;
     RECT  91.515 48.541 103.266 48.557 ;
     RECT  102.456 48.557 103.266 48.569 ;
     RECT  102.492 48.569 103.266 48.653 ;
     RECT  102.492 48.653 103.194 48.731 ;
     RECT  90.648 47.731 90.738 48.811 ;
     RECT  91.515 48.557 101.538 48.811 ;
     RECT  102.564 48.731 103.194 48.839 ;
     RECT  34.632 48.235 64.797 48.965 ;
     RECT  90.648 48.811 101.538 49.001 ;
     RECT  90.648 49.001 90.666 49.469 ;
     RECT  91.515 49.001 101.538 49.477 ;
     RECT  102.6 48.839 103.194 49.747 ;
     RECT  90.684 49.747 90.702 49.883 ;
     RECT  102.564 49.747 103.194 49.963 ;
     RECT  91.515 49.477 101.574 50.045 ;
     RECT  102.492 49.963 103.194 50.251 ;
     RECT  72.576 32.261 72.897 50.323 ;
     RECT  78.015 44.411 78.966 50.351 ;
     RECT  72.216 50.323 72.897 50.549 ;
     RECT  69.084 39.281 70.197 50.557 ;
     RECT  71.064 34.231 71.082 50.557 ;
     RECT  72.396 50.549 72.897 50.621 ;
     RECT  69.084 50.557 71.082 50.657 ;
     RECT  72.468 50.621 72.897 50.657 ;
     RECT  90.648 50.557 90.666 50.657 ;
     RECT  91.515 50.045 100.926 50.827 ;
     RECT  101.988 50.251 103.194 50.827 ;
     RECT  77.184 44.411 77.202 51.061 ;
     RECT  78.015 50.351 78.786 51.061 ;
     RECT  91.515 50.827 103.266 51.149 ;
     RECT  77.184 51.061 78.786 51.197 ;
     RECT  91.515 51.149 103.194 51.245 ;
     RECT  34.632 48.965 59.397 51.871 ;
     RECT  60.12 48.965 64.797 51.871 ;
     RECT  90.648 51.871 90.666 51.979 ;
     RECT  91.515 51.245 102.69 51.979 ;
     RECT  90.648 51.979 90.774 52.079 ;
     RECT  91.515 51.979 103.194 52.141 ;
     RECT  34.632 51.871 64.797 52.205 ;
     RECT  91.515 52.141 103.23 52.205 ;
     RECT  80.715 23.819 80.997 52.249 ;
     RECT  80.676 52.249 80.997 52.483 ;
     RECT  88.596 38.713 89.097 52.483 ;
     RECT  80.388 52.483 80.997 52.745 ;
     RECT  90.684 52.079 90.738 52.861 ;
     RECT  90.648 52.861 90.738 52.889 ;
     RECT  78.015 51.197 78.786 52.979 ;
     RECT  88.596 52.483 89.586 52.979 ;
     RECT  91.515 52.205 103.194 52.979 ;
     RECT  101.916 52.979 103.194 53.321 ;
     RECT  34.632 52.205 59.397 53.365 ;
     RECT  60.12 52.205 64.797 53.365 ;
     RECT  90.648 52.889 90.666 53.789 ;
     RECT  91.515 52.979 100.962 53.825 ;
     RECT  69.084 50.657 70.197 53.933 ;
     RECT  2.415 2.413 2.697 54.031 ;
     RECT  90.72 54.139 90.738 54.211 ;
     RECT  91.515 53.825 100.89 54.211 ;
     RECT  90.72 54.211 100.89 54.239 ;
     RECT  2.376 54.031 2.697 54.283 ;
     RECT  2.304 54.283 2.697 54.329 ;
     RECT  90.792 54.239 100.89 54.365 ;
     RECT  91.515 54.365 100.89 54.635 ;
     RECT  102.024 53.321 103.194 54.751 ;
     RECT  102.024 54.751 103.23 54.797 ;
     RECT  93.168 54.635 100.89 55.013 ;
     RECT  102.024 54.797 103.194 55.339 ;
     RECT  101.916 55.339 103.194 55.553 ;
     RECT  93.744 55.013 100.89 55.723 ;
     RECT  93.744 55.723 101.646 56.395 ;
     RECT  102.492 55.553 103.194 56.395 ;
     RECT  34.632 53.365 64.797 56.497 ;
     RECT  33.336 54.301 33.354 56.525 ;
     RECT  34.632 56.497 64.89 56.641 ;
     RECT  93.744 56.395 103.194 56.669 ;
     RECT  34.632 56.641 64.962 56.831 ;
     RECT  96.336 56.669 103.194 57.067 ;
     RECT  96.336 57.067 103.23 57.173 ;
     RECT  96.336 57.173 101.646 57.341 ;
     RECT  102.6 57.173 103.23 57.371 ;
     RECT  90.648 57.307 90.666 57.415 ;
     RECT  101.628 57.341 101.646 57.443 ;
     RECT  96.336 57.341 100.89 57.451 ;
     RECT  102.636 57.371 103.23 57.479 ;
     RECT  93.744 56.669 95.562 57.568 ;
     RECT  96.3 57.451 100.89 57.568 ;
     RECT  90.648 57.415 90.738 57.569 ;
     RECT  93.744 57.568 100.89 57.605 ;
     RECT  90.648 57.569 90.666 57.947 ;
     RECT  74.376 36.787 76.194 58.019 ;
     RECT  88.596 52.979 89.097 58.081 ;
     RECT  102.636 57.479 103.194 58.189 ;
     RECT  101.664 58.153 101.682 58.225 ;
     RECT  102.6 58.189 103.194 58.225 ;
     RECT  88.344 58.081 89.097 58.415 ;
     RECT  93.744 57.605 100.638 58.415 ;
     RECT  67.215 39.281 68.202 58.423 ;
     RECT  93.744 58.415 100.314 58.423 ;
     RECT  77.184 51.197 77.202 58.531 ;
     RECT  66.744 58.423 68.202 58.559 ;
     RECT  101.664 58.225 103.194 58.621 ;
     RECT  76.608 58.531 77.202 58.685 ;
     RECT  76.716 58.685 77.202 58.721 ;
     RECT  103.968 58.693 103.986 58.733 ;
     RECT  101.088 58.621 103.194 58.919 ;
     RECT  93.492 58.423 100.314 59.063 ;
     RECT  93.744 59.063 100.314 59.269 ;
     RECT  101.088 58.919 101.178 59.269 ;
     RECT  101.916 58.919 103.194 59.275 ;
     RECT  101.916 59.275 103.23 59.333 ;
     RECT  93.744 59.269 101.178 59.755 ;
     RECT  101.916 59.333 103.194 59.755 ;
     RECT  90.648 59.341 90.666 59.881 ;
     RECT  90.648 59.881 90.738 60.611 ;
     RECT  93.744 59.755 103.194 60.953 ;
     RECT  93.744 60.953 101.61 61.229 ;
     RECT  91.515 54.635 92.286 61.321 ;
     RECT  102.564 60.953 103.194 61.421 ;
     RECT  100.764 61.229 101.61 61.493 ;
     RECT  90.648 60.611 90.666 61.529 ;
     RECT  91.515 61.321 92.934 61.655 ;
     RECT  102.6 61.421 103.194 61.675 ;
     RECT  93.744 61.229 99.897 61.969 ;
     RECT  102.6 61.675 103.23 62.033 ;
     RECT  104.04 62.011 104.058 62.041 ;
     RECT  103.968 62.041 104.058 62.069 ;
     RECT  103.968 62.069 103.986 62.093 ;
     RECT  93.492 61.969 99.897 62.107 ;
     RECT  100.764 61.493 101.502 62.107 ;
     RECT  93.492 62.107 101.502 62.339 ;
     RECT  93.744 62.339 101.502 62.347 ;
     RECT  102.6 62.033 103.194 62.347 ;
     RECT  93.744 62.347 103.194 63.077 ;
     RECT  101.988 63.077 103.194 63.115 ;
     RECT  101.988 63.115 103.23 63.149 ;
     RECT  102.6 63.149 103.23 63.319 ;
     RECT  102.6 63.319 103.266 63.821 ;
     RECT  102.6 63.821 103.23 63.979 ;
     RECT  93.744 63.077 101.106 64.129 ;
     RECT  90.648 64.021 90.666 64.193 ;
     RECT  91.515 61.655 92.286 64.201 ;
     RECT  93.744 64.129 101.178 64.355 ;
     RECT  102.024 63.979 103.23 64.397 ;
     RECT  91.515 64.201 92.358 64.499 ;
     RECT  93.744 64.355 100.926 64.637 ;
     RECT  102.492 64.397 103.23 64.741 ;
     RECT  102.492 64.741 103.266 65.069 ;
     RECT  102.492 65.069 103.23 65.131 ;
     RECT  101.988 65.131 103.23 65.273 ;
     RECT  100.872 64.637 100.926 65.371 ;
     RECT  100.872 65.371 101.142 65.419 ;
     RECT  93.744 64.637 100.026 65.443 ;
     RECT  100.872 65.419 101.718 65.443 ;
     RECT  93.492 65.443 101.718 65.543 ;
     RECT  93.492 65.543 101.682 65.579 ;
     RECT  69.915 53.933 70.197 65.641 ;
     RECT  71.064 50.657 71.082 65.641 ;
     RECT  93.492 65.579 101.646 65.741 ;
     RECT  102.492 65.273 103.194 66.029 ;
     RECT  69.915 65.641 71.082 66.119 ;
     RECT  93.744 65.741 101.646 66.269 ;
     RECT  102.492 66.029 103.086 66.379 ;
     RECT  101.664 66.379 103.086 66.859 ;
     RECT  93.744 66.269 100.926 66.991 ;
     RECT  101.664 66.859 103.194 66.991 ;
     RECT  103.968 66.955 103.986 66.991 ;
     RECT  103.968 66.991 104.058 67.019 ;
     RECT  104.04 67.019 104.058 67.037 ;
     RECT  82.332 36.887 85.05 67.243 ;
     RECT  86.115 35.069 86.397 67.243 ;
     RECT  67.215 58.559 68.202 67.297 ;
     RECT  66.6 67.297 68.202 67.433 ;
     RECT  72.576 50.657 72.897 67.559 ;
     RECT  82.332 67.243 86.397 67.565 ;
     RECT  93.744 66.991 103.194 67.631 ;
     RECT  87.12 67.567 87.138 67.661 ;
     RECT  93.744 67.631 101.25 67.829 ;
     RECT  90.648 67.873 90.666 67.981 ;
     RECT  90.648 67.981 90.738 68.171 ;
     RECT  100.692 67.829 101.25 68.449 ;
     RECT  101.988 67.631 103.194 68.449 ;
     RECT  100.692 68.449 103.194 68.485 ;
     RECT  93.744 67.829 99.954 68.675 ;
     RECT  96.372 68.675 99.954 68.881 ;
     RECT  100.692 68.485 103.302 68.881 ;
     RECT  96.372 68.881 103.302 69.005 ;
     RECT  90.648 68.171 90.666 69.061 ;
     RECT  90.648 69.061 90.738 69.179 ;
     RECT  90.72 69.179 90.738 69.251 ;
     RECT  93.744 68.675 95.418 69.493 ;
     RECT  93.744 69.493 95.562 69.691 ;
     RECT  93.744 69.691 95.634 69.727 ;
     RECT  96.372 69.005 103.194 69.727 ;
     RECT  93.744 69.727 103.194 69.989 ;
     RECT  90.72 70.105 90.738 70.141 ;
     RECT  90.648 70.141 90.774 70.259 ;
     RECT  90.756 70.259 90.774 70.331 ;
     RECT  34.632 56.831 64.797 70.375 ;
     RECT  71.064 66.119 71.082 70.403 ;
     RECT  93.744 69.989 100.746 70.771 ;
     RECT  101.52 69.989 103.194 70.771 ;
     RECT  93.744 70.771 103.194 70.891 ;
     RECT  93.744 70.891 103.23 70.979 ;
     RECT  76.428 70.843 76.446 71.105 ;
     RECT  93.744 70.979 103.194 71.213 ;
     RECT  34.632 70.375 64.998 71.375 ;
     RECT  82.332 67.565 85.05 71.455 ;
     RECT  90.684 71.311 90.702 71.581 ;
     RECT  82.332 71.455 85.302 71.645 ;
     RECT  93.744 71.213 101.25 71.645 ;
     RECT  101.988 71.213 103.194 71.693 ;
     RECT  96.624 71.645 101.25 71.753 ;
     RECT  102.024 71.693 103.194 71.755 ;
     RECT  90.072 71.581 90.702 71.845 ;
     RECT  67.215 67.433 68.202 71.887 ;
     RECT  90.072 71.845 90.738 71.915 ;
     RECT  89.82 71.947 89.838 71.987 ;
     RECT  102.024 71.755 103.23 71.987 ;
     RECT  90.612 71.915 90.738 72.149 ;
     RECT  66.708 71.887 68.202 72.157 ;
     RECT  93.744 71.645 95.85 72.185 ;
     RECT  90.648 72.149 90.738 72.229 ;
     RECT  91.515 64.499 92.286 72.229 ;
     RECT  90.648 72.229 92.286 72.317 ;
     RECT  66.6 72.157 68.202 72.329 ;
     RECT  90.648 72.317 90.738 72.329 ;
     RECT  95.364 72.185 95.85 72.391 ;
     RECT  96.624 71.753 101.178 72.391 ;
     RECT  34.632 71.375 64.797 72.427 ;
     RECT  34.632 72.427 64.89 72.535 ;
     RECT  34.632 72.535 64.962 72.571 ;
     RECT  102.024 71.987 102.618 72.715 ;
     RECT  95.364 72.391 101.178 72.797 ;
     RECT  101.988 72.715 102.618 72.841 ;
     RECT  65.808 37.859 65.826 73.003 ;
     RECT  93.744 72.185 94.626 73.003 ;
     RECT  95.364 72.797 100.53 73.003 ;
     RECT  101.268 72.841 102.618 73.003 ;
     RECT  66.744 72.329 68.202 73.075 ;
     RECT  34.488 72.571 64.998 73.111 ;
     RECT  65.808 73.003 65.862 73.111 ;
     RECT  101.268 73.003 103.194 73.111 ;
     RECT  93.744 73.003 100.53 73.235 ;
     RECT  91.515 72.317 92.286 73.309 ;
     RECT  91.515 73.309 92.934 73.607 ;
     RECT  34.488 73.111 65.862 73.651 ;
     RECT  66.708 73.075 68.202 73.651 ;
     RECT  95.508 73.235 100.53 73.651 ;
     RECT  101.268 73.111 103.23 73.651 ;
     RECT  93.744 73.235 94.77 74.011 ;
     RECT  95.508 73.651 103.23 74.011 ;
     RECT  93.744 74.011 103.23 74.093 ;
     RECT  93.744 74.093 101.61 74.111 ;
     RECT  101.412 74.111 101.61 74.141 ;
     RECT  102.6 74.093 103.23 74.191 ;
     RECT  34.488 73.651 68.202 74.219 ;
     RECT  34.488 74.219 66.438 74.333 ;
     RECT  102.6 74.191 103.266 74.573 ;
     RECT  34.488 74.333 66.33 74.579 ;
     RECT  101.484 74.141 101.61 74.827 ;
     RECT  102.6 74.573 103.194 74.827 ;
     RECT  101.484 74.827 103.194 75.091 ;
     RECT  93.744 74.111 100.602 75.271 ;
     RECT  93.744 75.271 100.71 75.361 ;
     RECT  101.448 75.091 103.194 75.361 ;
     RECT  90.648 75.973 90.738 76.073 ;
     RECT  90.648 76.073 90.666 76.199 ;
     RECT  93.744 75.361 103.194 76.199 ;
     RECT  93.744 76.199 100.638 76.235 ;
     RECT  93.744 76.235 100.494 76.349 ;
     RECT  34.488 74.579 65.826 76.441 ;
     RECT  34.488 76.441 66.33 76.493 ;
     RECT  102.492 76.199 103.194 76.541 ;
     RECT  102.6 76.541 103.194 76.651 ;
     RECT  102.6 76.651 103.23 76.811 ;
     RECT  34.488 76.493 65.826 76.847 ;
     RECT  101.448 76.199 101.466 76.847 ;
     RECT  93.744 76.349 99.918 77.009 ;
     RECT  100.8 77.017 100.818 77.117 ;
     RECT  95.796 77.009 99.918 77.351 ;
     RECT  96.516 77.351 99.918 77.431 ;
     RECT  102.6 76.811 103.194 77.515 ;
     RECT  102.492 77.515 103.194 77.611 ;
     RECT  102.024 77.611 103.194 77.741 ;
     RECT  93.744 77.009 94.878 77.755 ;
     RECT  96.516 77.431 100.674 77.947 ;
     RECT  102.024 77.741 102.618 77.995 ;
     RECT  96.516 77.947 100.818 78.061 ;
     RECT  101.7 77.995 102.618 78.061 ;
     RECT  32.115 2.413 32.397 78.169 ;
     RECT  32.115 78.169 33.03 78.205 ;
     RECT  93.744 77.755 95.598 78.511 ;
     RECT  96.516 78.061 102.618 78.511 ;
     RECT  93.744 78.511 102.618 78.653 ;
     RECT  90.648 78.745 90.738 78.899 ;
     RECT  90.72 78.899 90.738 79.043 ;
     RECT  95.868 78.653 102.618 79.181 ;
     RECT  32.115 78.205 33.246 79.213 ;
     RECT  32.115 79.213 33.318 79.285 ;
     RECT  34.488 76.847 64.998 79.285 ;
     RECT  95.868 79.181 101.466 79.313 ;
     RECT  102.492 79.181 102.618 79.411 ;
     RECT  93.744 78.653 95.058 79.447 ;
     RECT  95.868 79.313 101.43 79.447 ;
     RECT  93.744 79.447 101.43 79.475 ;
     RECT  102.492 79.411 103.194 79.475 ;
     RECT  102.564 79.475 103.194 79.547 ;
     RECT  91.515 73.607 92.286 79.555 ;
     RECT  95.508 79.475 101.43 79.565 ;
     RECT  102.6 79.547 103.194 79.619 ;
     RECT  102.636 79.619 103.194 79.661 ;
     RECT  100.728 79.565 101.43 79.709 ;
     RECT  95.508 79.565 99.897 79.745 ;
     RECT  102.636 79.661 102.69 79.757 ;
     RECT  102.636 79.757 102.654 79.781 ;
     RECT  91.515 79.555 92.358 79.853 ;
     RECT  95.832 79.745 99.897 79.853 ;
     RECT  95.832 79.853 98.37 79.979 ;
     RECT  100.8 79.709 101.43 79.979 ;
     RECT  95.832 79.979 95.85 80.015 ;
     RECT  96.84 79.979 98.37 80.249 ;
     RECT  101.412 79.979 101.43 80.249 ;
     RECT  93.744 79.475 94.662 80.321 ;
     RECT  96.915 80.249 98.37 80.321 ;
     RECT  91.515 79.853 92.286 81.059 ;
     RECT  90.648 81.067 90.666 81.239 ;
     RECT  96.915 80.321 97.686 82.409 ;
     RECT  78.015 52.979 78.678 82.445 ;
     RECT  32.115 79.285 64.998 82.651 ;
     RECT  65.808 76.847 65.826 84.065 ;
     RECT  32.115 82.651 65.07 84.335 ;
     RECT  69.915 66.119 70.197 85.627 ;
     RECT  78.015 82.445 78.297 85.627 ;
     RECT  69.915 85.627 70.722 85.757 ;
     RECT  78.015 85.627 78.678 85.757 ;
     RECT  99.252 79.853 99.897 85.919 ;
     RECT  74.376 58.019 75.597 85.955 ;
     RECT  67.215 74.219 68.202 88.925 ;
     RECT  32.115 84.335 64.998 89.131 ;
     RECT  82.332 71.645 85.05 89.465 ;
     RECT  88.596 58.415 89.097 90.275 ;
     RECT  69.084 53.933 69.102 90.545 ;
     RECT  32.115 89.131 65.106 90.617 ;
     RECT  83.415 89.465 85.05 90.779 ;
     RECT  77.184 58.721 77.202 90.787 ;
     RECT  82.332 89.465 82.35 90.787 ;
     RECT  82.332 90.787 82.674 90.959 ;
     RECT  32.115 90.617 65.07 92.309 ;
     RECT  32.115 92.309 64.998 96.961 ;
     RECT  32.115 96.961 65.07 98.609 ;
     RECT  32.115 98.609 64.998 101.731 ;
     RECT  83.415 90.779 84.69 101.759 ;
     RECT  75.06 85.955 75.597 102.965 ;
     RECT  2.415 54.329 2.697 103.157 ;
     RECT  5.115 2.413 5.397 103.157 ;
     RECT  7.815 2.413 8.097 103.157 ;
     RECT  10.515 2.413 10.797 103.157 ;
     RECT  13.215 2.413 13.497 103.157 ;
     RECT  15.915 2.413 16.197 103.157 ;
     RECT  18.615 2.413 18.897 103.157 ;
     RECT  21.315 2.413 21.597 103.157 ;
     RECT  24.015 2.413 24.297 103.157 ;
     RECT  26.715 2.413 26.997 103.157 ;
     RECT  29.415 2.413 29.697 103.157 ;
     RECT  32.115 101.731 65.574 103.157 ;
     RECT  69.915 85.757 70.197 103.157 ;
     RECT  72.615 67.559 72.897 103.157 ;
     RECT  75.315 102.965 75.597 103.157 ;
     RECT  78.015 85.757 78.297 103.157 ;
     RECT  80.715 52.745 80.997 103.157 ;
     RECT  83.415 101.759 84.15 103.157 ;
     RECT  86.115 67.565 86.397 103.157 ;
     RECT  88.815 90.275 89.097 103.157 ;
     RECT  91.515 81.059 91.797 103.157 ;
     RECT  96.915 82.409 97.197 103.157 ;
     RECT  99.615 85.919 99.897 103.157 ;
     RECT  82.332 90.959 82.35 103.199 ;
     RECT  67.215 88.925 67.497 103.207 ;
     RECT  77.184 90.787 77.238 103.235 ;
     RECT  93.744 80.321 94.497 103.271 ;
     RECT  66.672 103.207 67.497 103.307 ;
     RECT  83.607 103.157 84.15 103.307 ;
     RECT  70.056 103.157 70.197 103.343 ;
     RECT  2.607 103.157 2.697 103.427 ;
     RECT  5.307 103.157 5.397 103.427 ;
     RECT  8.007 103.157 8.097 103.427 ;
     RECT  10.707 103.157 10.797 103.427 ;
     RECT  13.407 103.157 13.497 103.427 ;
     RECT  16.107 103.157 16.197 103.427 ;
     RECT  18.807 103.157 18.897 103.427 ;
     RECT  21.507 103.157 21.597 103.427 ;
     RECT  24.207 103.157 24.297 103.427 ;
     RECT  26.907 103.157 26.997 103.427 ;
     RECT  29.607 103.157 29.697 103.427 ;
     RECT  32.307 103.157 65.574 103.427 ;
     RECT  66.744 103.307 67.497 103.427 ;
     RECT  70.107 103.343 70.197 103.427 ;
     RECT  72.807 103.157 72.897 103.427 ;
     RECT  75.507 103.157 75.597 103.427 ;
     RECT  78.207 103.157 78.297 103.427 ;
     RECT  80.907 103.157 80.997 103.427 ;
     RECT  83.607 103.307 83.697 103.427 ;
     RECT  86.307 103.157 86.397 103.427 ;
     RECT  89.007 103.157 89.097 103.427 ;
     RECT  91.707 103.157 91.797 103.427 ;
     RECT  94.407 103.271 94.497 103.427 ;
     RECT  97.107 103.157 97.197 103.427 ;
     RECT  99.807 103.157 99.897 103.427 ;
     RECT  66.744 103.427 66.762 103.505 ;
     RECT  77.328 103.351 77.346 103.541 ;
     RECT  32.652 103.427 65.574 103.577 ;
     RECT  32.652 103.577 64.854 104.045 ;
     RECT  64.476 104.045 64.854 104.285 ;
     RECT  32.652 104.045 63.666 105.677 ;
     RECT  32.652 105.677 63.594 105.725 ;
     RECT  32.652 105.725 63.27 105.773 ;
     RECT  32.652 105.773 63.198 105.804 ;
    LAYER M4 ;
     RECT  0.133 51.12 2.408 51.144 ;
     RECT  0.06 54.096 2.408 54.312 ;
     RECT  2.408 2.148 2.512 103.152 ;
     RECT  2.512 2.418 2.6 103.152 ;
     RECT  2.6 2.418 2.704 103.422 ;
     RECT  2.704 53.808 2.819 53.832 ;
     RECT  2.704 32.208 5.108 32.232 ;
     RECT  2.704 51.12 5.108 51.144 ;
     RECT  5.108 2.148 5.212 103.152 ;
     RECT  5.212 2.418 5.3 103.152 ;
     RECT  5.3 2.418 5.404 103.422 ;
     RECT  5.404 32.208 7.808 32.232 ;
     RECT  5.404 51.12 7.808 51.144 ;
     RECT  7.808 2.148 7.912 103.152 ;
     RECT  7.912 2.418 8 103.152 ;
     RECT  8 2.418 8.104 103.422 ;
     RECT  8.104 32.208 10.508 32.232 ;
     RECT  8.104 51.12 10.508 51.144 ;
     RECT  10.508 2.148 10.612 103.152 ;
     RECT  10.612 2.418 10.7 103.152 ;
     RECT  10.7 2.418 10.804 103.422 ;
     RECT  10.804 32.208 13.208 32.232 ;
     RECT  10.804 51.12 13.208 51.144 ;
     RECT  13.208 2.148 13.312 103.152 ;
     RECT  13.312 2.418 13.4 103.152 ;
     RECT  13.4 2.418 13.504 103.422 ;
     RECT  13.504 32.208 15.908 32.232 ;
     RECT  13.504 51.12 15.908 51.144 ;
     RECT  15.908 2.148 16.012 103.152 ;
     RECT  16.012 2.418 16.1 103.152 ;
     RECT  16.1 2.418 16.204 103.422 ;
     RECT  16.204 32.208 18.608 32.232 ;
     RECT  16.204 51.12 18.608 51.144 ;
     RECT  18.608 2.148 18.712 103.152 ;
     RECT  18.712 2.418 18.8 103.152 ;
     RECT  18.8 2.418 18.904 103.422 ;
     RECT  18.904 32.208 21.308 32.232 ;
     RECT  18.904 51.12 21.308 51.144 ;
     RECT  21.308 2.148 21.412 103.152 ;
     RECT  21.412 2.418 21.5 103.152 ;
     RECT  21.5 2.418 21.604 103.422 ;
     RECT  21.604 32.208 24.008 32.232 ;
     RECT  21.604 51.12 24.008 51.144 ;
     RECT  24.008 2.148 24.112 103.152 ;
     RECT  24.112 2.418 24.2 103.152 ;
     RECT  24.2 2.418 24.304 103.422 ;
     RECT  24.304 32.208 26.708 32.232 ;
     RECT  24.304 51.12 26.708 51.144 ;
     RECT  26.708 2.148 26.812 103.152 ;
     RECT  26.812 2.418 26.9 103.152 ;
     RECT  26.9 2.418 27.004 103.422 ;
     RECT  27.004 32.208 29.408 32.232 ;
     RECT  27.004 51.12 29.408 51.144 ;
     RECT  29.408 2.148 29.512 103.152 ;
     RECT  29.512 2.418 29.6 103.152 ;
     RECT  29.6 2.418 29.704 103.422 ;
     RECT  29.704 32.208 32.108 32.232 ;
     RECT  29.704 51.12 32.108 51.144 ;
     RECT  32.108 2.148 32.212 103.152 ;
     RECT  32.212 2.418 32.3 103.152 ;
     RECT  32.3 2.418 32.404 103.422 ;
     RECT  32.404 32.208 34.808 32.232 ;
     RECT  32.404 51.12 34.808 51.144 ;
     RECT  34.453 85.728 34.808 85.752 ;
     RECT  34.441 101.472 34.808 101.496 ;
     RECT  34.808 2.148 34.912 103.152 ;
     RECT  34.912 2.418 35 103.152 ;
     RECT  35 2.418 35.104 103.422 ;
     RECT  35.104 32.208 37.508 32.232 ;
     RECT  35.104 51.12 37.508 51.144 ;
     RECT  35.104 85.728 37.508 85.752 ;
     RECT  37.321 103.152 37.508 103.176 ;
     RECT  37.508 2.148 37.612 103.176 ;
     RECT  37.612 2.418 37.7 103.176 ;
     RECT  37.7 2.418 37.804 103.422 ;
     RECT  37.897 105.744 38.117 105.768 ;
     RECT  37.804 85.632 38.837 85.752 ;
     RECT  37.804 23.568 40.208 23.592 ;
     RECT  39.589 26.592 40.208 26.616 ;
     RECT  37.804 32.208 40.208 32.232 ;
     RECT  37.804 51.12 40.208 51.144 ;
     RECT  38.837 85.728 40.208 85.752 ;
     RECT  39.589 103.2 40.208 103.224 ;
     RECT  40.208 2.148 40.312 103.224 ;
     RECT  40.312 2.418 40.4 103.224 ;
     RECT  40.4 2.418 40.504 103.422 ;
     RECT  41.785 105.744 42.005 105.768 ;
     RECT  40.504 23.568 42.908 23.592 ;
     RECT  40.504 26.592 42.908 26.616 ;
     RECT  40.504 32.208 42.908 32.232 ;
     RECT  40.504 51.12 42.908 51.144 ;
     RECT  42.757 52.128 42.908 52.152 ;
     RECT  40.504 85.728 42.908 85.752 ;
     RECT  42.908 2.148 43.012 103.152 ;
     RECT  43.012 2.418 43.1 103.152 ;
     RECT  43.045 105.696 43.117 105.72 ;
     RECT  43.1 2.418 43.204 103.422 ;
     RECT  43.117 105.696 43.265 105.768 ;
     RECT  43.265 105.696 43.337 105.72 ;
     RECT  43.204 51.12 44.773 51.144 ;
     RECT  44.953 53.136 45.061 53.16 ;
     RECT  43.204 23.568 45.608 23.592 ;
     RECT  43.204 26.592 45.608 26.616 ;
     RECT  43.204 32.208 45.608 32.232 ;
     RECT  44.773 50.736 45.608 51.144 ;
     RECT  45.061 53.136 45.608 53.688 ;
     RECT  43.204 85.728 45.608 85.752 ;
     RECT  45.608 2.148 45.712 103.152 ;
     RECT  45.712 2.418 45.8 103.152 ;
     RECT  45.8 2.418 45.904 103.422 ;
     RECT  46.597 105.696 46.685 105.72 ;
     RECT  45.904 26.496 46.793 26.616 ;
     RECT  45.904 85.632 46.793 85.752 ;
     RECT  45.904 102.048 46.793 103.224 ;
     RECT  45.904 78.144 46.835 79.8 ;
     RECT  46.835 79.68 46.873 79.8 ;
     RECT  46.793 102.048 46.931 102.6 ;
     RECT  45.904 53.568 47.009 53.592 ;
     RECT  45.904 61.776 47.009 61.8 ;
     RECT  46.835 78.432 47.009 78.6 ;
     RECT  46.873 79.68 47.081 79.704 ;
     RECT  46.931 102.528 47.117 102.6 ;
     RECT  46.933 99.744 47.123 99.768 ;
     RECT  47.117 102.576 47.189 102.6 ;
     RECT  45.904 51.12 47.221 51.144 ;
     RECT  47.173 104.832 47.261 104.856 ;
     RECT  46.969 101.424 47.267 101.448 ;
     RECT  47.009 78.576 47.297 78.6 ;
     RECT  47.365 103.728 47.621 103.752 ;
     RECT  47.461 68.352 47.804 68.376 ;
     RECT  47.257 63.216 48.037 63.24 ;
     RECT  47.941 65.664 48.085 65.688 ;
     RECT  48.037 63.216 48.121 63.288 ;
     RECT  48.085 65.232 48.133 65.688 ;
     RECT  48.133 64.944 48.181 65.688 ;
     RECT  45.904 23.568 48.308 23.592 ;
     RECT  46.793 26.592 48.308 26.616 ;
     RECT  45.904 32.208 48.308 32.232 ;
     RECT  47.221 51.12 48.308 51.288 ;
     RECT  47.617 56.976 48.308 57 ;
     RECT  48.193 58.608 48.308 58.632 ;
     RECT  48.121 62.736 48.308 63.288 ;
     RECT  48.181 64.32 48.308 65.688 ;
     RECT  47.804 67.824 48.308 68.376 ;
     RECT  47.989 70.656 48.308 70.68 ;
     RECT  47.653 72.336 48.308 72.36 ;
     RECT  46.793 85.728 48.308 85.752 ;
     RECT  47.557 98.016 48.308 98.04 ;
     RECT  48.308 2.148 48.412 103.422 ;
     RECT  47.653 105.552 48.413 105.768 ;
     RECT  48.412 2.418 48.604 103.422 ;
     RECT  48.604 70.656 48.665 70.68 ;
     RECT  48.604 64.704 48.989 66.264 ;
     RECT  48.413 105.552 48.997 105.672 ;
     RECT  48.989 64.704 49.025 66.168 ;
     RECT  48.604 54.72 49.061 54.744 ;
     RECT  48.604 100.896 49.187 100.92 ;
     RECT  48.604 68.112 49.385 68.376 ;
     RECT  48.997 104.832 49.385 105.672 ;
     RECT  48.604 78.288 49.493 78.312 ;
     RECT  49.385 68.112 49.601 68.328 ;
     RECT  48.604 82.608 49.601 82.632 ;
     RECT  49.765 104.256 49.853 104.28 ;
     RECT  49.669 62.736 49.861 62.76 ;
     RECT  48.604 48.432 49.925 48.456 ;
     RECT  49.573 105.696 49.925 105.72 ;
     RECT  48.604 45.552 50.033 45.576 ;
     RECT  50.053 59.52 50.341 59.544 ;
     RECT  50.341 59.52 50.389 59.832 ;
     RECT  50.389 58.704 50.437 59.832 ;
     RECT  50.437 58.704 50.533 60.408 ;
     RECT  50.149 100.848 50.677 100.872 ;
     RECT  49.601 68.112 50.713 68.136 ;
     RECT  50.677 76.464 50.713 76.488 ;
     RECT  49.025 64.704 50.725 65.544 ;
     RECT  49.861 62.16 50.821 62.76 ;
     RECT  50.725 63.792 50.821 65.544 ;
     RECT  50.785 78.576 50.821 78.696 ;
     RECT  50.677 79.776 50.821 79.8 ;
     RECT  50.821 78.576 50.857 79.8 ;
     RECT  50.497 105.648 50.869 105.672 ;
     RECT  50.869 105.6 50.917 105.672 ;
     RECT  49.957 103.152 50.929 103.176 ;
     RECT  48.604 23.568 51.008 23.592 ;
     RECT  48.604 26.592 51.008 26.616 ;
     RECT  48.604 32.208 51.008 32.232 ;
     RECT  48.604 40.656 51.008 40.68 ;
     RECT  49.957 42.528 51.008 42.552 ;
     RECT  48.604 51.12 51.008 51.144 ;
     RECT  48.604 52.416 51.008 52.44 ;
     RECT  50.533 58.704 51.008 60.984 ;
     RECT  50.821 62.16 51.008 65.544 ;
     RECT  50.713 68.112 51.008 68.424 ;
     RECT  50.581 72.768 51.008 72.792 ;
     RECT  50.713 76.272 51.008 76.488 ;
     RECT  50.857 78.576 51.008 80.088 ;
     RECT  48.604 85.728 51.008 85.752 ;
     RECT  50.677 91.776 51.008 91.944 ;
     RECT  50.749 94.56 51.008 94.584 ;
     RECT  50.677 99.744 51.008 100.872 ;
     RECT  50.929 103.152 51.008 103.56 ;
     RECT  51.008 2.148 51.112 103.56 ;
     RECT  50.917 104.832 51.301 105.672 ;
     RECT  51.112 2.418 51.304 103.56 ;
     RECT  51.301 104.832 51.325 105.72 ;
     RECT  51.304 61.728 51.473 64.728 ;
     RECT  51.304 103.2 51.635 103.224 ;
     RECT  51.325 104.832 51.689 105.768 ;
     RECT  51.304 54.672 51.725 54.792 ;
     RECT  51.304 80.064 51.725 80.088 ;
     RECT  51.304 50.784 51.797 51.144 ;
     RECT  51.304 78.48 51.797 78.936 ;
     RECT  51.689 104.832 51.797 105.72 ;
     RECT  51.797 104.832 51.877 105.672 ;
     RECT  51.473 61.728 51.905 64.392 ;
     RECT  51.797 78.48 51.905 78.504 ;
     RECT  51.877 104.256 51.977 105.672 ;
     RECT  51.304 46.752 52.049 46.776 ;
     RECT  51.725 54.672 52.085 54.696 ;
     RECT  51.304 38.16 52.093 38.184 ;
     RECT  51.905 61.728 52.157 63.816 ;
     RECT  51.977 104.832 52.301 105.672 ;
     RECT  52.301 105.648 52.355 105.672 ;
     RECT  51.304 66.672 52.481 66.696 ;
     RECT  51.304 72.768 52.625 72.792 ;
     RECT  52.157 61.728 52.661 63.24 ;
     RECT  52.661 61.728 52.733 62.184 ;
     RECT  51.304 101.424 52.733 101.448 ;
     RECT  51.304 44.688 52.765 44.712 ;
     RECT  51.304 70.656 52.801 70.68 ;
     RECT  52.741 69.552 52.837 69.576 ;
     RECT  51.304 68.112 52.933 68.136 ;
     RECT  52.837 69.552 52.933 69.624 ;
     RECT  52.309 48.384 52.981 48.408 ;
     RECT  52.933 68.112 53.125 69.624 ;
     RECT  52.801 70.656 53.125 71.208 ;
     RECT  51.304 85.728 53.413 85.752 ;
     RECT  53.029 99.696 53.461 99.72 ;
     RECT  53.461 98.736 53.521 99.72 ;
     RECT  53.516 74.544 53.557 74.568 ;
     RECT  53.413 102.576 53.557 102.6 ;
     RECT  53.521 103.632 53.557 103.656 ;
     RECT  53.557 105.552 53.605 105.576 ;
     RECT  53.557 102.576 53.701 103.656 ;
     RECT  51.304 23.568 53.708 23.592 ;
     RECT  51.304 26.592 53.708 26.616 ;
     RECT  51.304 32.208 53.708 32.232 ;
     RECT  52.981 37.392 53.708 37.416 ;
     RECT  51.304 40.656 53.708 40.68 ;
     RECT  51.304 42.528 53.708 42.552 ;
     RECT  52.765 44.448 53.708 44.712 ;
     RECT  53.269 46.848 53.708 46.872 ;
     RECT  52.981 48.384 53.708 48.456 ;
     RECT  51.797 51.12 53.708 51.144 ;
     RECT  53.125 58.704 53.708 58.728 ;
     RECT  52.733 61.92 53.708 62.184 ;
     RECT  52.661 63.168 53.708 63.24 ;
     RECT  53.125 68.112 53.708 71.208 ;
     RECT  53.557 74.544 53.708 75.24 ;
     RECT  53.461 78.576 53.708 78.792 ;
     RECT  53.413 82.608 53.708 82.632 ;
     RECT  53.413 85.728 53.708 86.664 ;
     RECT  53.413 94.464 53.708 94.776 ;
     RECT  53.521 98.64 53.708 99.72 ;
     RECT  53.701 102.576 53.708 103.752 ;
     RECT  53.708 2.148 53.809 103.752 ;
     RECT  53.809 2.148 53.812 104.28 ;
     RECT  53.812 2.418 53.881 104.28 ;
     RECT  53.605 105.456 53.881 105.576 ;
     RECT  53.881 2.418 53.941 105.576 ;
     RECT  53.941 2.418 54.004 105.624 ;
     RECT  54.004 50.736 54.281 51.672 ;
     RECT  54.004 74.64 54.419 75.24 ;
     RECT  54.281 50.736 54.497 51.384 ;
     RECT  54.004 73.344 54.497 73.368 ;
     RECT  54.004 103.104 54.569 105.624 ;
     RECT  54.569 103.104 54.605 104.76 ;
     RECT  54.004 98.064 54.707 98.088 ;
     RECT  54.004 26.496 54.749 26.616 ;
     RECT  54.004 85.632 54.749 85.752 ;
     RECT  54.004 49.488 54.755 49.56 ;
     RECT  54.004 48.384 54.857 48.408 ;
     RECT  54.004 62.16 54.857 62.184 ;
     RECT  54.004 58.704 54.965 58.728 ;
     RECT  54.004 68.448 55.037 70.104 ;
     RECT  55.037 68.64 55.043 70.104 ;
     RECT  54.004 71.184 55.045 71.832 ;
     RECT  54.605 103.104 55.109 104.568 ;
     RECT  54.755 49.536 55.141 49.56 ;
     RECT  55.043 68.64 55.145 68.664 ;
     RECT  55.033 99.168 55.187 99.192 ;
     RECT  55.043 69.648 55.237 70.104 ;
     RECT  55.045 71.184 55.237 72.408 ;
     RECT  54.853 105.744 55.289 105.768 ;
     RECT  54.497 51.12 55.325 51.384 ;
     RECT  55.237 69.648 55.325 72.408 ;
     RECT  55.141 49.536 55.573 50.136 ;
     RECT  55.325 51.12 55.573 51.144 ;
     RECT  55.525 73.536 55.717 73.56 ;
     RECT  54.419 74.64 55.717 74.664 ;
     RECT  55.909 75.84 56.197 75.864 ;
     RECT  56.101 76.848 56.197 76.872 ;
     RECT  55.717 73.536 56.293 74.664 ;
     RECT  56.197 75.84 56.293 76.872 ;
     RECT  54.004 23.568 56.408 23.592 ;
     RECT  54.749 26.592 56.408 26.616 ;
     RECT  54.004 32.208 56.408 32.232 ;
     RECT  54.004 37.392 56.408 37.416 ;
     RECT  54.004 40.656 56.408 40.68 ;
     RECT  54.004 42.528 56.408 42.552 ;
     RECT  54.004 44.688 56.408 44.712 ;
     RECT  55.573 49.536 56.408 51.144 ;
     RECT  55.285 66.72 56.408 66.744 ;
     RECT  55.325 69.648 56.408 70.92 ;
     RECT  55.325 72.384 56.408 72.408 ;
     RECT  56.293 73.536 56.408 76.872 ;
     RECT  55.501 82.608 56.408 82.632 ;
     RECT  54.749 85.728 56.408 85.752 ;
     RECT  56.005 98.016 56.408 98.04 ;
     RECT  55.109 103.728 56.408 104.568 ;
     RECT  56.041 105.6 56.485 105.672 ;
     RECT  56.408 2.148 56.512 104.568 ;
     RECT  56.512 2.418 56.54 104.568 ;
     RECT  56.485 105.552 56.54 105.672 ;
     RECT  56.54 2.418 56.653 105.672 ;
     RECT  56.653 2.418 56.704 105.768 ;
     RECT  56.704 102.576 56.801 105.768 ;
     RECT  56.801 102.576 56.819 105.624 ;
     RECT  56.704 73.536 56.837 73.56 ;
     RECT  56.819 102.576 56.837 105.576 ;
     RECT  56.704 54.096 56.873 55.272 ;
     RECT  56.704 62.16 56.963 62.184 ;
     RECT  56.837 102.576 56.963 104.856 ;
     RECT  56.704 75.936 57.011 77.976 ;
     RECT  56.963 102.576 57.011 104.568 ;
     RECT  56.704 79.776 57.233 80.376 ;
     RECT  57.011 103.152 57.251 104.568 ;
     RECT  56.704 49.536 57.277 50.136 ;
     RECT  57.233 79.824 57.413 80.376 ;
     RECT  57.251 103.152 57.485 104.28 ;
     RECT  57.011 75.936 57.557 77.544 ;
     RECT  57.413 79.824 57.587 79.848 ;
     RECT  57.277 50.112 57.635 50.136 ;
     RECT  57.485 103.152 57.635 103.992 ;
     RECT  56.873 54.384 57.913 55.272 ;
     RECT  57.733 82.608 58.061 82.632 ;
     RECT  57.913 54.288 58.097 55.272 ;
     RECT  58.097 54.384 58.133 55.272 ;
     RECT  57.635 103.152 58.405 103.176 ;
     RECT  58.405 103.104 58.501 103.176 ;
     RECT  57.557 75.936 58.693 77.496 ;
     RECT  56.704 51.12 58.705 52.008 ;
     RECT  58.705 51.12 58.741 52.056 ;
     RECT  58.693 75.936 58.741 77.592 ;
     RECT  58.501 103.008 58.789 103.176 ;
     RECT  58.741 75.264 58.813 77.592 ;
     RECT  58.741 105.744 58.837 105.768 ;
     RECT  58.837 105.648 58.889 105.768 ;
     RECT  58.889 105.648 58.933 105.672 ;
     RECT  58.741 66 58.981 66.024 ;
     RECT  58.789 103.008 58.997 103.752 ;
     RECT  56.704 23.568 59.108 23.592 ;
     RECT  56.704 26.592 59.108 26.616 ;
     RECT  56.704 32.208 59.108 32.232 ;
     RECT  56.704 37.392 59.108 37.416 ;
     RECT  56.704 40.656 59.108 40.68 ;
     RECT  56.704 42.528 59.108 42.552 ;
     RECT  56.704 44.688 59.108 44.712 ;
     RECT  58.741 51.12 59.108 52.872 ;
     RECT  58.133 54.384 59.108 54.408 ;
     RECT  58.645 55.68 59.108 55.704 ;
     RECT  58.981 65.664 59.108 66.024 ;
     RECT  58.777 70.752 59.108 70.776 ;
     RECT  58.813 74.64 59.108 77.592 ;
     RECT  58.345 78.624 59.108 78.648 ;
     RECT  58.705 82.512 59.108 82.536 ;
     RECT  56.704 85.728 59.108 85.752 ;
     RECT  58.997 103.008 59.108 103.422 ;
     RECT  59.108 2.148 59.212 103.422 ;
     RECT  58.933 105.408 59.365 105.672 ;
     RECT  59.212 2.418 59.404 103.422 ;
     RECT  59.404 59.28 59.651 59.304 ;
     RECT  59.404 82.512 59.651 82.536 ;
     RECT  59.404 75.936 59.681 75.96 ;
     RECT  59.404 77.04 59.681 77.592 ;
     RECT  59.681 77.568 59.753 77.592 ;
     RECT  59.365 104.832 59.789 105.672 ;
     RECT  59.404 74.736 59.861 74.76 ;
     RECT  59.404 66.384 59.897 67.8 ;
     RECT  59.404 70.128 59.897 71.256 ;
     RECT  59.404 55.68 60.005 56.808 ;
     RECT  59.404 97.44 60.005 97.464 ;
     RECT  59.404 102.624 60.083 102.648 ;
     RECT  59.897 70.128 60.185 70.152 ;
     RECT  60.001 105.744 60.365 105.768 ;
     RECT  59.404 68.928 60.401 68.952 ;
     RECT  59.897 66.72 60.421 67.8 ;
     RECT  60.005 56.496 60.437 56.808 ;
     RECT  59.404 65.376 60.437 65.4 ;
     RECT  60.421 66.72 60.517 67.848 ;
     RECT  60.517 66.72 60.797 68.76 ;
     RECT  60.997 103.728 61.085 103.752 ;
     RECT  59.897 71.232 61.381 71.256 ;
     RECT  61.045 58.128 61.405 58.152 ;
     RECT  59.404 85.728 61.405 85.752 ;
     RECT  61.405 90.816 61.429 90.84 ;
     RECT  61.429 90.576 61.484 90.84 ;
     RECT  61.381 71.184 61.513 71.256 ;
     RECT  61.189 104.832 61.517 104.856 ;
     RECT  61.405 85.728 61.525 86.52 ;
     RECT  61.505 98.784 61.525 98.808 ;
     RECT  61.513 102.576 61.525 102.6 ;
     RECT  60.709 72.912 61.621 72.936 ;
     RECT  61.525 85.728 61.765 86.568 ;
     RECT  59.404 23.568 61.808 23.592 ;
     RECT  59.404 26.592 61.808 26.616 ;
     RECT  59.404 32.208 61.808 32.232 ;
     RECT  59.404 37.392 61.808 37.416 ;
     RECT  59.404 40.656 61.808 40.68 ;
     RECT  59.404 42.528 61.808 42.552 ;
     RECT  59.404 44.688 61.808 44.712 ;
     RECT  61.513 48.144 61.808 48.168 ;
     RECT  59.404 51.12 61.808 51.144 ;
     RECT  60.437 56.496 61.808 56.52 ;
     RECT  61.405 57.888 61.808 58.152 ;
     RECT  59.404 60.96 61.808 60.984 ;
     RECT  60.797 66.768 61.808 68.76 ;
     RECT  61.513 70.704 61.808 71.256 ;
     RECT  61.621 72.24 61.808 72.936 ;
     RECT  61.729 76.848 61.808 76.872 ;
     RECT  61.429 78.576 61.808 79.032 ;
     RECT  61.765 85.728 61.808 86.616 ;
     RECT  61.484 90.48 61.808 90.84 ;
     RECT  61.525 94.704 61.808 94.728 ;
     RECT  61.525 98.496 61.808 98.808 ;
     RECT  61.525 102.432 61.808 103.608 ;
     RECT  61.621 104.88 61.811 105.672 ;
     RECT  61.808 2.148 61.912 103.608 ;
     RECT  61.811 104.88 62.003 104.904 ;
     RECT  61.912 2.418 62.104 103.608 ;
     RECT  62.104 66.72 62.129 68.76 ;
     RECT  62.104 57.888 62.237 57.912 ;
     RECT  62.104 75.792 62.243 75.816 ;
     RECT  62.149 103.728 62.309 103.752 ;
     RECT  62.104 72.24 62.531 74.088 ;
     RECT  62.104 49.536 62.569 51.144 ;
     RECT  62.104 56.496 62.597 56.52 ;
     RECT  62.104 102 62.597 102.6 ;
     RECT  62.531 72.384 62.705 74.088 ;
     RECT  62.104 26.496 62.741 26.616 ;
     RECT  62.104 85.632 62.741 85.752 ;
     RECT  62.104 37.296 62.777 37.416 ;
     RECT  62.705 72.96 62.777 74.088 ;
     RECT  62.129 66.72 62.849 68.136 ;
     RECT  62.849 67.344 62.885 67.944 ;
     RECT  62.597 102.528 62.885 102.6 ;
     RECT  62.777 72.96 62.921 72.984 ;
     RECT  62.104 54.336 62.993 55.176 ;
     RECT  62.104 70.704 62.993 71.208 ;
     RECT  62.993 54.576 63.029 55.176 ;
     RECT  62.993 71.184 63.029 71.208 ;
     RECT  62.569 50.016 63.137 51.144 ;
     RECT  63.137 50.592 63.209 51.144 ;
     RECT  63.164 78.096 63.251 78.12 ;
     RECT  62.885 67.344 63.425 67.608 ;
     RECT  63.301 105.696 63.493 105.72 ;
     RECT  63.493 105.648 63.605 105.72 ;
     RECT  63.605 105.648 63.677 105.672 ;
     RECT  62.885 102.576 63.685 102.6 ;
     RECT  62.104 52.416 63.781 52.44 ;
     RECT  62.777 73.968 64.069 74.088 ;
     RECT  64.069 73.872 64.105 74.088 ;
     RECT  64.105 73.872 64.165 74.328 ;
     RECT  62.104 23.568 64.508 23.592 ;
     RECT  62.741 26.592 64.508 26.616 ;
     RECT  62.104 30.864 64.508 31.128 ;
     RECT  62.104 32.208 64.508 32.232 ;
     RECT  62.777 37.392 64.508 37.416 ;
     RECT  62.104 40.656 64.508 40.68 ;
     RECT  62.104 42.528 64.508 42.552 ;
     RECT  62.104 44.688 64.508 44.712 ;
     RECT  62.104 48.144 64.508 48.168 ;
     RECT  63.209 51.12 64.508 51.144 ;
     RECT  63.781 52.416 64.508 52.584 ;
     RECT  63.029 54.576 64.508 54.6 ;
     RECT  63.425 67.344 64.508 67.368 ;
     RECT  64.165 73.68 64.508 74.328 ;
     RECT  64.357 76.32 64.508 76.344 ;
     RECT  63.397 77.472 64.508 77.496 ;
     RECT  64.261 80.928 64.508 80.952 ;
     RECT  62.741 85.728 64.508 85.752 ;
     RECT  63.932 99.744 64.508 99.768 ;
     RECT  63.877 100.848 64.508 100.872 ;
     RECT  63.685 102.576 64.508 103.176 ;
     RECT  64.508 2.148 64.612 103.176 ;
     RECT  64.549 105.456 64.645 105.48 ;
     RECT  64.612 2.418 64.7 103.176 ;
     RECT  64.421 104.256 64.7 104.28 ;
     RECT  64.645 105.36 64.789 105.48 ;
     RECT  64.7 2.418 64.804 104.28 ;
     RECT  64.804 103.536 64.865 104.28 ;
     RECT  64.789 105.36 64.931 105.624 ;
     RECT  64.804 76.32 64.972 77.496 ;
     RECT  64.804 74.304 64.979 74.664 ;
     RECT  64.931 105.456 64.979 105.624 ;
     RECT  64.972 76.32 65.009 77.4 ;
     RECT  64.865 103.536 65.009 103.656 ;
     RECT  64.804 78.672 65.027 78.696 ;
     RECT  64.804 82.608 65.053 82.632 ;
     RECT  64.804 98.64 65.075 98.664 ;
     RECT  65.009 103.632 65.075 103.656 ;
     RECT  65.009 76.32 65.225 76.824 ;
     RECT  65.225 76.608 66.301 76.824 ;
     RECT  64.804 23.568 67.208 23.592 ;
     RECT  64.804 26.592 67.208 26.616 ;
     RECT  64.804 30.864 67.208 31.128 ;
     RECT  64.804 32.208 67.208 32.232 ;
     RECT  64.804 37.392 67.208 37.416 ;
     RECT  64.804 40.656 67.208 40.68 ;
     RECT  64.804 42.528 67.208 42.552 ;
     RECT  64.804 44.688 67.208 44.712 ;
     RECT  64.804 48.144 67.208 48.168 ;
     RECT  64.804 51.12 67.208 51.144 ;
     RECT  64.979 74.304 67.208 74.328 ;
     RECT  66.301 76.464 67.208 76.824 ;
     RECT  64.804 85.728 67.208 85.752 ;
     RECT  67.208 2.148 67.312 103.152 ;
     RECT  67.312 2.418 67.4 103.152 ;
     RECT  67.4 2.418 67.504 103.422 ;
     RECT  67.504 23.568 69.908 23.592 ;
     RECT  67.504 26.592 69.908 26.616 ;
     RECT  67.504 30.864 69.908 31.128 ;
     RECT  67.504 32.208 69.908 32.232 ;
     RECT  67.504 37.392 69.908 37.416 ;
     RECT  67.504 40.656 69.908 40.68 ;
     RECT  67.504 42.528 69.908 42.552 ;
     RECT  67.504 44.688 69.908 44.712 ;
     RECT  67.504 48.144 69.908 48.168 ;
     RECT  67.504 51.12 69.908 51.144 ;
     RECT  67.504 76.464 69.908 76.824 ;
     RECT  67.504 85.728 69.908 85.752 ;
     RECT  69.908 2.148 70.012 103.152 ;
     RECT  70.012 2.418 70.1 103.152 ;
     RECT  70.1 2.418 70.204 103.422 ;
     RECT  70.204 26.496 70.733 26.616 ;
     RECT  70.204 85.632 70.733 85.752 ;
     RECT  70.204 30.864 72.037 31.128 ;
     RECT  70.204 32.208 72.037 32.232 ;
     RECT  70.204 23.568 72.469 23.592 ;
     RECT  72.037 30.864 72.469 32.232 ;
     RECT  72.469 23.328 72.608 23.592 ;
     RECT  70.733 26.592 72.608 26.616 ;
     RECT  72.469 30.336 72.608 32.232 ;
     RECT  70.204 37.392 72.608 37.416 ;
     RECT  70.204 40.656 72.608 40.68 ;
     RECT  70.204 42.528 72.608 42.552 ;
     RECT  70.204 44.688 72.608 44.712 ;
     RECT  70.204 48.144 72.608 48.168 ;
     RECT  70.204 51.12 72.608 51.144 ;
     RECT  70.204 76.464 72.608 76.824 ;
     RECT  70.733 85.728 72.608 85.752 ;
     RECT  72.608 2.148 72.712 103.152 ;
     RECT  72.712 2.418 72.8 103.152 ;
     RECT  72.8 2.418 72.904 103.422 ;
     RECT  72.904 30.864 74.099 31.944 ;
     RECT  74.053 21.936 75.308 21.96 ;
     RECT  72.904 23.328 75.308 23.592 ;
     RECT  72.904 26.592 75.308 26.616 ;
     RECT  74.099 30.864 75.308 31.8 ;
     RECT  72.904 40.656 75.308 40.68 ;
     RECT  72.904 42.528 75.308 42.552 ;
     RECT  72.904 44.688 75.308 44.712 ;
     RECT  72.904 48.144 75.308 48.168 ;
     RECT  72.904 51.12 75.308 51.144 ;
     RECT  72.904 76.464 75.308 76.824 ;
     RECT  72.904 85.728 75.308 85.752 ;
     RECT  75.308 2.148 75.412 103.152 ;
     RECT  75.412 2.418 75.5 103.152 ;
     RECT  75.5 2.418 75.604 103.422 ;
     RECT  75.604 51.12 75.809 51.144 ;
     RECT  75.604 21.936 78.008 21.96 ;
     RECT  75.604 23.328 78.008 23.592 ;
     RECT  75.604 26.592 78.008 26.616 ;
     RECT  75.604 30.864 78.008 31.8 ;
     RECT  75.604 40.656 78.008 40.68 ;
     RECT  75.604 42.528 78.008 42.552 ;
     RECT  75.604 44.688 78.008 44.712 ;
     RECT  75.604 48.144 78.008 48.168 ;
     RECT  77.317 51.168 78.008 51.192 ;
     RECT  75.604 76.464 78.008 76.824 ;
     RECT  75.604 85.728 78.008 85.752 ;
     RECT  78.008 2.148 78.112 103.152 ;
     RECT  78.112 2.418 78.2 103.152 ;
     RECT  78.2 2.418 78.304 103.422 ;
     RECT  78.304 26.496 78.689 26.616 ;
     RECT  78.304 30.816 78.689 31.8 ;
     RECT  78.304 85.632 78.689 85.752 ;
     RECT  78.304 21.936 80.708 21.96 ;
     RECT  78.304 23.328 80.708 23.592 ;
     RECT  78.689 26.592 80.708 26.616 ;
     RECT  78.689 30.864 80.708 31.8 ;
     RECT  78.304 40.656 80.708 40.68 ;
     RECT  78.304 42.528 80.708 42.552 ;
     RECT  78.304 44.688 80.708 44.712 ;
     RECT  78.304 48.144 80.708 48.168 ;
     RECT  78.304 51.168 80.708 51.192 ;
     RECT  78.304 76.464 80.708 76.824 ;
     RECT  78.689 85.728 80.708 85.752 ;
     RECT  80.708 2.148 80.812 103.152 ;
     RECT  80.812 2.418 80.9 103.152 ;
     RECT  80.9 2.418 81.004 103.422 ;
     RECT  81.004 44.688 82.988 44.712 ;
     RECT  81.004 51.168 83.029 51.192 ;
     RECT  81.004 85.728 83.249 85.752 ;
     RECT  81.004 21.936 83.408 21.96 ;
     RECT  81.004 23.328 83.408 23.592 ;
     RECT  81.004 26.592 83.408 26.616 ;
     RECT  81.004 30.864 83.408 31.8 ;
     RECT  81.004 40.656 83.408 40.68 ;
     RECT  81.004 42.528 83.408 42.552 ;
     RECT  82.988 44.688 83.408 45 ;
     RECT  81.004 48.144 83.408 48.168 ;
     RECT  83.029 51.168 83.408 51.288 ;
     RECT  83.141 57.024 83.408 57.048 ;
     RECT  81.004 76.464 83.408 76.824 ;
     RECT  83.249 84.96 83.408 85.752 ;
     RECT  83.408 2.148 83.512 103.152 ;
     RECT  83.512 2.418 83.6 103.152 ;
     RECT  83.6 2.418 83.704 103.422 ;
     RECT  83.704 44.688 84.593 44.952 ;
     RECT  83.704 76.464 84.659 76.824 ;
     RECT  83.704 85.344 84.659 85.512 ;
     RECT  84.659 85.344 84.7 85.368 ;
     RECT  83.704 65.376 84.803 66.12 ;
     RECT  84.733 57.552 84.817 57.576 ;
     RECT  84.803 65.376 84.985 66.024 ;
     RECT  85.517 67.248 85.532 67.272 ;
     RECT  83.704 21.936 86.108 21.96 ;
     RECT  83.704 23.328 86.108 23.592 ;
     RECT  83.704 26.592 86.108 26.616 ;
     RECT  83.704 30.864 86.108 31.8 ;
     RECT  83.704 40.656 86.108 40.68 ;
     RECT  83.704 42.528 86.108 42.552 ;
     RECT  84.593 44.928 86.108 44.952 ;
     RECT  83.704 48.144 86.108 48.168 ;
     RECT  84.985 65.136 86.108 66.024 ;
     RECT  85.532 67.248 86.108 67.56 ;
     RECT  85.573 71.952 86.108 71.976 ;
     RECT  84.659 76.464 86.108 76.488 ;
     RECT  83.704 79.728 86.108 79.752 ;
     RECT  86.108 2.148 86.212 103.152 ;
     RECT  86.212 2.418 86.3 103.152 ;
     RECT  86.3 2.418 86.404 103.422 ;
     RECT  86.404 30.816 86.681 31.8 ;
     RECT  86.404 26.496 86.717 26.616 ;
     RECT  86.404 21.936 88.808 21.96 ;
     RECT  86.404 23.328 88.808 23.592 ;
     RECT  86.717 26.592 88.808 26.616 ;
     RECT  86.681 30.864 88.808 31.8 ;
     RECT  86.404 40.656 88.808 40.68 ;
     RECT  86.404 42.528 88.808 42.552 ;
     RECT  86.404 44.928 88.808 44.952 ;
     RECT  86.404 48.144 88.808 48.168 ;
     RECT  86.404 65.136 88.808 66.024 ;
     RECT  86.404 67.632 88.808 67.656 ;
     RECT  86.404 71.952 88.808 71.976 ;
     RECT  86.404 79.728 88.808 79.752 ;
     RECT  88.808 2.148 88.912 103.152 ;
     RECT  88.912 2.418 89 103.152 ;
     RECT  89 2.418 89.104 103.422 ;
     RECT  89.104 71.952 90.601 71.976 ;
     RECT  90.601 71.856 90.637 71.976 ;
     RECT  89.104 48.144 90.709 48.168 ;
     RECT  89.104 21.936 91.508 21.96 ;
     RECT  89.104 23.328 91.508 23.592 ;
     RECT  89.104 26.592 91.508 26.616 ;
     RECT  89.104 30.864 91.508 31.8 ;
     RECT  89.104 40.656 91.508 40.68 ;
     RECT  89.104 42.528 91.508 42.552 ;
     RECT  89.104 44.928 91.508 44.952 ;
     RECT  90.709 48.144 91.508 48.264 ;
     RECT  89.104 65.136 91.508 66.024 ;
     RECT  89.104 67.632 91.508 67.656 ;
     RECT  90.637 71.856 91.508 72.312 ;
     RECT  89.104 79.728 91.508 79.752 ;
     RECT  91.508 2.148 91.612 103.152 ;
     RECT  91.612 2.418 91.7 103.152 ;
     RECT  91.7 2.418 91.804 103.422 ;
     RECT  91.804 42.528 92.905 42.552 ;
     RECT  91.804 44.928 92.905 44.952 ;
     RECT  92.905 49.632 92.941 49.656 ;
     RECT  92.905 42.528 93.053 43.032 ;
     RECT  92.905 51.744 93.053 51.768 ;
     RECT  92.941 49.632 93.089 50.136 ;
     RECT  92.905 44.064 93.125 44.952 ;
     RECT  93.089 50.112 93.161 50.136 ;
     RECT  92.977 52.8 93.161 52.824 ;
     RECT  91.804 21.936 94.208 21.96 ;
     RECT  91.804 23.328 94.208 23.592 ;
     RECT  91.804 26.592 94.208 26.616 ;
     RECT  91.804 30.864 94.208 31.8 ;
     RECT  91.804 40.656 94.208 40.68 ;
     RECT  93.053 42.528 94.208 42.552 ;
     RECT  93.125 44.928 94.208 44.952 ;
     RECT  91.804 48.24 94.208 48.264 ;
     RECT  94.057 57.12 94.208 57.144 ;
     RECT  91.804 65.136 94.208 66.024 ;
     RECT  91.804 67.632 94.208 67.656 ;
     RECT  91.804 71.952 94.208 71.976 ;
     RECT  94.069 75.12 94.208 75.96 ;
     RECT  91.804 79.728 94.208 79.752 ;
     RECT  94.208 2.148 94.312 103.152 ;
     RECT  94.312 2.418 94.4 103.152 ;
     RECT  94.4 2.418 94.504 103.422 ;
     RECT  94.504 78.624 94.565 79.752 ;
     RECT  94.504 62.544 94.739 73.224 ;
     RECT  94.504 74.304 94.739 75.96 ;
     RECT  94.504 20.976 94.781 24.168 ;
     RECT  94.504 39.792 94.828 61.416 ;
     RECT  94.504 25.152 94.853 28.008 ;
     RECT  94.504 30.864 94.853 38.76 ;
     RECT  94.504 77.472 94.889 77.496 ;
     RECT  94.565 78.624 94.924 79.704 ;
     RECT  94.739 62.544 94.979 72.168 ;
     RECT  94.828 39.792 94.997 58.68 ;
     RECT  94.979 64.32 95.027 71.16 ;
     RECT  94.853 33.408 95.393 38.76 ;
     RECT  95.393 34.752 95.429 38.76 ;
     RECT  95.027 64.416 95.429 69.576 ;
     RECT  94.924 78.624 95.437 78.648 ;
     RECT  94.828 59.712 95.509 61.416 ;
     RECT  94.979 62.544 95.509 63.288 ;
     RECT  94.504 29.52 95.533 29.592 ;
     RECT  94.739 73.2 95.533 73.224 ;
     RECT  94.853 25.152 95.537 27.384 ;
     RECT  94.997 47.232 95.537 58.68 ;
     RECT  94.979 72.144 95.537 72.168 ;
     RECT  94.739 74.4 95.605 75.96 ;
     RECT  94.781 23.04 95.641 24.168 ;
     RECT  95.537 25.152 95.641 27.192 ;
     RECT  94.853 30.864 95.641 32.28 ;
     RECT  95.533 73.2 95.701 73.272 ;
     RECT  95.605 74.4 95.701 76.488 ;
     RECT  95.569 77.76 95.747 77.784 ;
     RECT  95.429 64.608 95.753 69.576 ;
     RECT  95.027 70.608 95.753 71.16 ;
     RECT  95.701 72.384 95.753 76.488 ;
     RECT  95.753 72.384 95.788 75.336 ;
     RECT  95.509 59.712 95.789 63.288 ;
     RECT  94.781 20.976 95.804 22.008 ;
     RECT  95.641 23.04 95.804 27.192 ;
     RECT  95.804 20.976 95.845 27.192 ;
     RECT  94.924 79.68 95.861 79.704 ;
     RECT  95.845 20.592 95.891 27.192 ;
     RECT  95.429 36.144 95.948 38.76 ;
     RECT  94.997 39.792 95.948 46.2 ;
     RECT  95.753 64.848 96.037 69.576 ;
     RECT  95.753 70.992 96.037 71.16 ;
     RECT  95.641 30.816 96.073 32.28 ;
     RECT  95.393 33.408 96.073 33.432 ;
     RECT  95.533 28.656 96.181 29.736 ;
     RECT  95.948 36.144 96.181 46.2 ;
     RECT  96.181 28.656 96.229 29.832 ;
     RECT  96.073 30.816 96.229 33.432 ;
     RECT  95.753 76.32 96.325 76.488 ;
     RECT  95.537 52.224 96.433 58.68 ;
     RECT  95.789 59.712 96.433 60.12 ;
     RECT  96.229 28.656 96.505 33.432 ;
     RECT  95.429 34.752 96.505 34.92 ;
     RECT  96.433 52.224 96.517 60.12 ;
     RECT  95.789 61.2 96.649 63.288 ;
     RECT  96.037 70.992 96.649 71.256 ;
     RECT  95.788 72.384 96.649 73.752 ;
     RECT  95.537 47.232 96.721 51.192 ;
     RECT  96.517 52.176 96.721 60.12 ;
     RECT  96.505 28.656 96.757 34.92 ;
     RECT  96.181 36.144 96.757 46.248 ;
     RECT  96.649 70.992 96.757 73.752 ;
     RECT  95.788 75.12 96.757 75.336 ;
     RECT  96.037 64.848 96.865 69.768 ;
     RECT  96.757 70.992 96.865 75.336 ;
     RECT  96.325 76.32 96.865 76.968 ;
     RECT  95.891 20.592 96.908 22.056 ;
     RECT  95.891 23.04 96.908 27.192 ;
     RECT  96.757 28.656 96.908 46.248 ;
     RECT  96.721 47.232 96.908 60.12 ;
     RECT  96.649 61.2 96.908 63.624 ;
     RECT  96.865 64.608 96.908 69.768 ;
     RECT  96.865 70.992 96.908 76.968 ;
     RECT  96.908 2.148 97.012 103.152 ;
     RECT  97.012 2.418 97.1 103.152 ;
     RECT  97.1 2.418 97.204 103.422 ;
     RECT  97.204 28.32 97.265 54.936 ;
     RECT  97.204 58.944 97.331 68.472 ;
     RECT  97.204 69.504 97.331 76.2 ;
     RECT  97.204 20.496 97.373 27.192 ;
     RECT  97.204 77.76 97.409 79.848 ;
     RECT  97.331 63.216 97.517 68.472 ;
     RECT  97.265 28.32 97.841 54.792 ;
     RECT  97.841 38.688 98.243 54.792 ;
     RECT  97.409 77.76 98.305 79.032 ;
     RECT  98.243 45.168 98.341 54.792 ;
     RECT  97.204 56.352 98.341 57.576 ;
     RECT  97.331 69.504 98.341 76.152 ;
     RECT  98.305 77.52 98.341 79.032 ;
     RECT  97.841 28.32 98.413 37.608 ;
     RECT  97.517 63.216 98.485 67.8 ;
     RECT  98.485 63.216 98.521 68.52 ;
     RECT  98.341 69.504 98.521 79.032 ;
     RECT  97.373 20.496 98.593 26.616 ;
     RECT  97.331 58.944 98.593 62.232 ;
     RECT  98.521 63.216 98.593 79.032 ;
     RECT  98.593 58.704 98.629 79.032 ;
     RECT  98.593 20.496 98.633 26.76 ;
     RECT  98.629 58.656 98.953 79.032 ;
     RECT  98.633 24.912 99.061 26.76 ;
     RECT  98.413 27.744 99.061 37.608 ;
     RECT  98.243 38.688 99.205 44.184 ;
     RECT  98.341 45.168 99.205 57.576 ;
     RECT  99.061 24.912 99.277 37.608 ;
     RECT  99.205 38.688 99.277 57.576 ;
     RECT  98.633 20.592 99.608 23.88 ;
     RECT  99.277 24.912 99.608 57.576 ;
     RECT  98.953 58.656 99.608 79.56 ;
     RECT  99.608 2.148 99.712 103.152 ;
     RECT  99.712 2.418 99.8 103.152 ;
     RECT  99.8 2.418 99.904 103.422 ;
     RECT  99.904 65.664 99.929 76.776 ;
     RECT  99.929 65.664 99.965 76.344 ;
     RECT  99.904 55.44 100.001 57.576 ;
     RECT  99.904 58.656 100.045 58.68 ;
     RECT  99.904 35.76 100.181 54.408 ;
     RECT  100.181 35.76 100.217 52.776 ;
     RECT  100.217 39.408 100.361 52.776 ;
     RECT  100.361 39.408 100.397 52.488 ;
     RECT  99.965 68.928 100.397 76.344 ;
     RECT  99.904 77.808 100.433 79.56 ;
     RECT  99.904 22.752 100.505 34.728 ;
     RECT  100.397 39.408 100.505 51.912 ;
     RECT  100.397 69.504 100.505 76.344 ;
     RECT  99.904 20.16 100.649 21.672 ;
     RECT  100.649 20.16 100.685 21.528 ;
     RECT  100.505 22.752 100.685 24.072 ;
     RECT  99.965 65.664 100.721 67.608 ;
     RECT  100.505 69.504 100.757 76.296 ;
     RECT  99.904 59.664 100.829 64.632 ;
     RECT  100.829 64.56 100.897 64.632 ;
     RECT  100.721 65.664 100.897 67.464 ;
     RECT  100.897 64.56 100.901 67.464 ;
     RECT  100.505 40.656 100.937 51.912 ;
     RECT  100.829 59.664 101.113 62.856 ;
     RECT  100.433 77.808 101.401 79.224 ;
     RECT  100.505 25.248 101.473 34.728 ;
     RECT  100.217 35.76 101.473 38.232 ;
     RECT  100.505 39.408 101.473 39.432 ;
     RECT  100.937 40.656 101.473 49.608 ;
     RECT  100.937 51.072 101.473 51.912 ;
     RECT  100.757 69.504 101.473 71.688 ;
     RECT  100.685 20.16 101.617 20.952 ;
     RECT  100.685 22.992 101.905 24.072 ;
     RECT  101.473 25.2 101.905 34.728 ;
     RECT  101.473 51.072 101.905 52.104 ;
     RECT  100.181 54 101.905 54.408 ;
     RECT  100.001 55.44 101.905 57.48 ;
     RECT  101.617 20.016 101.977 20.952 ;
     RECT  101.905 22.32 101.977 34.728 ;
     RECT  101.473 35.76 101.977 38.28 ;
     RECT  101.473 39.408 101.977 49.608 ;
     RECT  101.113 58.992 101.977 62.856 ;
     RECT  100.901 64.752 101.977 67.464 ;
     RECT  101.473 68.592 101.977 71.688 ;
     RECT  100.757 72.816 101.977 76.296 ;
     RECT  101.977 20.016 102.013 38.28 ;
     RECT  101.977 39.312 102.013 49.608 ;
     RECT  101.905 51.072 102.013 57.48 ;
     RECT  101.977 58.992 102.013 63.048 ;
     RECT  101.977 64.752 102.013 71.688 ;
     RECT  101.977 72.72 102.013 76.296 ;
     RECT  101.401 77.808 102.013 79.368 ;
     RECT  102.013 20.016 102.481 76.296 ;
     RECT  102.013 77.616 102.481 79.368 ;
     RECT  102.481 20.016 102.589 76.488 ;
     RECT  102.481 77.52 102.589 79.368 ;
     RECT  102.589 20.016 102.625 79.464 ;
     RECT  102.625 20.016 102.661 79.56 ;
     RECT  102.661 20.016 103.165 79.752 ;
     RECT  103.165 19.92 104.028 79.752 ;
     RECT  104.028 25.152 104.069 25.176 ;
     RECT  104.028 32.064 104.069 32.088 ;
     RECT  104.028 42.048 104.069 42.072 ;
     RECT  104.028 62.016 104.069 62.04 ;
     RECT  104.028 67.008 104.069 67.032 ;
    LAYER M5 ;
     RECT  2.4 2.137 2.52 2.151 ;
     RECT  5.1 2.137 5.22 2.151 ;
     RECT  7.8 2.137 7.92 2.151 ;
     RECT  10.5 2.137 10.62 2.151 ;
     RECT  13.2 2.137 13.32 2.151 ;
     RECT  15.9 2.137 16.02 2.151 ;
     RECT  18.6 2.137 18.72 2.151 ;
     RECT  21.3 2.137 21.42 2.151 ;
     RECT  24 2.137 24.12 2.151 ;
     RECT  26.7 2.137 26.82 2.151 ;
     RECT  29.4 2.137 29.52 2.151 ;
     RECT  32.1 2.137 32.22 2.151 ;
     RECT  34.8 2.137 34.92 2.151 ;
     RECT  37.5 2.137 37.62 2.151 ;
     RECT  40.2 2.137 40.32 2.151 ;
     RECT  42.9 2.137 43.02 2.151 ;
     RECT  45.6 2.137 45.72 2.151 ;
     RECT  48.3 2.137 48.42 2.151 ;
     RECT  51 2.137 51.12 2.151 ;
     RECT  53.7 2.137 53.82 2.151 ;
     RECT  56.4 2.137 56.52 2.151 ;
     RECT  59.1 2.137 59.22 2.151 ;
     RECT  61.8 2.137 61.92 2.151 ;
     RECT  64.5 2.137 64.62 2.151 ;
     RECT  67.2 2.137 67.32 2.151 ;
     RECT  69.9 2.137 70.02 2.151 ;
     RECT  72.6 2.137 72.72 2.151 ;
     RECT  75.3 2.137 75.42 2.151 ;
     RECT  78 2.137 78.12 2.151 ;
     RECT  80.7 2.137 80.82 2.151 ;
     RECT  83.4 2.137 83.52 2.151 ;
     RECT  86.1 2.137 86.22 2.151 ;
     RECT  88.8 2.137 88.92 2.151 ;
     RECT  91.5 2.137 91.62 2.151 ;
     RECT  94.2 2.137 94.32 2.151 ;
     RECT  96.9 2.137 97.02 2.151 ;
     RECT  99.6 2.137 99.72 2.151 ;
     RECT  94.2 2.151 94.512 20.965 ;
     RECT  96.9 2.151 97.212 21.109 ;
     RECT  99.6 2.151 99.912 21.397 ;
     RECT  94.2 20.965 94.728 21.493 ;
     RECT  95.856 20.581 95.88 21.493 ;
     RECT  94.2 21.493 95.88 22.211 ;
     RECT  96.9 21.109 97.464 22.259 ;
     RECT  99.504 21.397 99.912 22.835 ;
     RECT  72.6 2.151 72.912 23.317 ;
     RECT  94.2 22.211 95.448 23.317 ;
     RECT  94.2 23.317 95.928 24.277 ;
     RECT  96.9 22.259 97.212 24.277 ;
     RECT  94.2 24.277 97.212 24.325 ;
     RECT  94.2 24.325 98.04 24.469 ;
     RECT  94.2 24.469 98.472 24.947 ;
     RECT  96.9 24.947 98.472 25.139 ;
     RECT  40.2 2.151 40.512 26.581 ;
     RECT  94.2 24.947 95.928 26.725 ;
     RECT  96.9 25.139 97.212 26.725 ;
     RECT  94.2 26.725 97.212 28.309 ;
     RECT  94.2 28.309 97.464 28.405 ;
     RECT  98.448 25.139 98.472 28.405 ;
     RECT  94.2 28.405 98.472 28.453 ;
     RECT  99.6 22.835 99.912 28.453 ;
     RECT  94.2 28.453 99.912 30.275 ;
     RECT  102.624 30.757 102.648 30.899 ;
     RECT  103.776 30.757 103.8 30.899 ;
     RECT  94.2 30.275 98.136 30.947 ;
     RECT  72.48 23.317 72.912 30.949 ;
     RECT  99.6 30.275 99.912 31.333 ;
     RECT  95.904 30.947 98.136 31.811 ;
     RECT  72.336 30.949 72.912 31.861 ;
     RECT  74.064 21.925 74.088 31.955 ;
     RECT  2.4 2.151 2.712 32.197 ;
     RECT  96.24 31.811 98.136 33.107 ;
     RECT  96.9 33.107 98.136 34.213 ;
     RECT  96.9 34.213 98.232 34.789 ;
     RECT  99.216 31.333 99.912 34.789 ;
     RECT  96.9 34.789 99.912 36.901 ;
     RECT  96.9 36.901 100.2 37.045 ;
     RECT  96.768 37.045 100.2 37.139 ;
     RECT  72.048 31.861 72.912 37.427 ;
     RECT  96.768 37.139 97.212 37.619 ;
     RECT  51 2.151 51.312 38.149 ;
     RECT  98.208 37.139 100.2 38.243 ;
     RECT  98.208 38.243 99.912 38.723 ;
     RECT  96.9 37.619 97.212 39.109 ;
     RECT  98.208 38.723 98.472 40.021 ;
     RECT  99.6 38.723 99.912 40.021 ;
     RECT  96 39.109 97.212 41.651 ;
     RECT  98.208 40.021 99.912 41.651 ;
     RECT  99.6 41.651 99.912 43.285 ;
     RECT  96.096 41.651 97.212 44.389 ;
     RECT  98.208 41.651 98.232 44.389 ;
     RECT  96.096 44.389 98.232 44.435 ;
     RECT  51 38.149 52.056 44.437 ;
     RECT  53.7 2.151 54.012 44.437 ;
     RECT  51 44.437 54.012 44.723 ;
     RECT  83.4 2.151 83.712 44.965 ;
     RECT  48.3 2.151 48.612 45.541 ;
     RECT  96.096 44.435 98.136 45.731 ;
     RECT  94.2 30.947 94.512 46.069 ;
     RECT  96.288 45.731 98.136 46.069 ;
     RECT  99.216 43.285 99.912 46.069 ;
     RECT  96.288 46.069 99.912 46.211 ;
     RECT  94.2 46.069 94.776 46.787 ;
     RECT  96.9 46.211 99.912 46.787 ;
     RECT  96.9 46.787 98.232 47.317 ;
     RECT  95.952 47.317 98.232 48.035 ;
     RECT  98.208 48.035 98.232 48.323 ;
     RECT  52.8 44.723 54.012 48.373 ;
     RECT  95.952 48.035 97.212 48.899 ;
     RECT  52.32 48.373 54.84 49.525 ;
     RECT  56.4 2.151 56.712 49.525 ;
     RECT  61.8 2.151 62.112 49.525 ;
     RECT  52.32 49.525 57.24 50.101 ;
     RECT  94.2 46.787 94.512 50.101 ;
     RECT  99.6 46.787 99.912 50.389 ;
     RECT  94.2 50.101 95.304 51.061 ;
     RECT  96.9 48.899 97.212 51.061 ;
     RECT  99.6 50.389 100.008 51.155 ;
     RECT  83.04 44.965 83.712 51.299 ;
     RECT  99.6 51.155 99.912 51.397 ;
     RECT  99.504 51.397 99.912 53.653 ;
     RECT  2.4 32.197 2.808 53.843 ;
     RECT  0.144 51.109 0.168 54.085 ;
     RECT  0.144 54.085 0.312 54.131 ;
     RECT  0.288 54.131 0.312 54.227 ;
     RECT  59.1 2.151 59.412 55.669 ;
     RECT  94.2 51.061 97.212 56.243 ;
     RECT  99.216 53.653 99.912 57.011 ;
     RECT  83.184 51.299 83.712 57.059 ;
     RECT  94.2 56.243 95.736 58.645 ;
     RECT  99.456 57.011 99.912 58.645 ;
     RECT  58.656 55.669 59.412 59.269 ;
     RECT  48.3 45.541 49.368 59.509 ;
     RECT  51 44.723 51.312 59.509 ;
     RECT  98.64 58.645 100.008 59.749 ;
     RECT  98.4 59.749 100.008 60.323 ;
     RECT  98.4 60.323 99.912 60.371 ;
     RECT  98.832 60.371 99.912 61.187 ;
     RECT  96.768 56.243 97.212 61.667 ;
     RECT  48.3 59.509 51.312 61.717 ;
     RECT  52.32 50.101 57.624 61.717 ;
     RECT  45.6 2.151 45.912 61.765 ;
     RECT  47.232 51.253 47.256 61.765 ;
     RECT  96.9 61.667 97.212 62.053 ;
     RECT  94.2 58.645 95.784 62.629 ;
     RECT  45.6 61.765 47.256 63.205 ;
     RECT  48.3 61.717 57.624 63.205 ;
     RECT  94.2 62.629 95.928 63.299 ;
     RECT  96.9 62.053 97.32 63.539 ;
     RECT  84.768 57.541 84.792 65.509 ;
     RECT  86.1 2.151 86.412 65.509 ;
     RECT  99.264 61.187 99.912 65.509 ;
     RECT  98.88 65.509 99.912 65.557 ;
     RECT  98.64 65.557 99.912 65.987 ;
     RECT  83.4 57.059 83.712 66.085 ;
     RECT  84.768 65.509 86.412 66.085 ;
     RECT  61.8 49.525 62.52 66.757 ;
     RECT  58.656 59.269 59.64 66.901 ;
     RECT  99.36 65.987 99.912 67.237 ;
     RECT  61.632 66.757 62.52 67.285 ;
     RECT  58.656 66.901 60.264 67.765 ;
     RECT  61.488 67.285 62.52 67.765 ;
     RECT  94.2 63.299 95.784 67.765 ;
     RECT  96.9 63.539 97.212 67.765 ;
     RECT  98.448 67.237 99.912 67.811 ;
     RECT  99.12 67.811 99.912 69.587 ;
     RECT  99.36 69.587 99.912 71.315 ;
     RECT  94.2 67.765 97.212 71.651 ;
     RECT  83.4 66.085 86.412 71.987 ;
     RECT  95.712 71.651 97.212 72.419 ;
     RECT  94.2 71.651 94.512 72.901 ;
     RECT  58.656 67.765 62.52 72.949 ;
     RECT  58.656 72.949 62.568 73.429 ;
     RECT  64.5 2.151 64.812 73.669 ;
     RECT  64.176 73.669 64.812 73.861 ;
     RECT  58.656 73.429 62.664 73.957 ;
     RECT  64.08 73.861 64.812 73.957 ;
     RECT  96.72 72.419 97.212 74.053 ;
     RECT  98.352 72.661 98.376 74.053 ;
     RECT  99.456 71.315 99.912 74.053 ;
     RECT  58.656 73.957 64.812 74.293 ;
     RECT  94.2 72.901 94.728 74.339 ;
     RECT  58.656 74.293 64.92 74.629 ;
     RECT  94.2 74.339 94.512 75.109 ;
     RECT  96.72 74.053 97.32 75.155 ;
     RECT  94.08 75.109 94.512 75.971 ;
     RECT  95.712 72.419 95.736 76.309 ;
     RECT  96.9 75.155 97.32 76.309 ;
     RECT  45.6 63.205 57.624 76.405 ;
     RECT  58.656 74.629 64.968 76.405 ;
     RECT  83.4 71.987 84.648 76.453 ;
     RECT  85.728 71.987 86.412 76.499 ;
     RECT  98.352 74.053 99.912 76.499 ;
     RECT  83.28 76.453 84.648 76.835 ;
     RECT  95.712 76.309 97.32 76.979 ;
     RECT  99.36 76.499 99.912 76.979 ;
     RECT  98.352 76.499 98.376 77.267 ;
     RECT  94.2 75.971 94.512 77.461 ;
     RECT  95.712 76.979 95.736 77.461 ;
     RECT  94.2 77.461 95.736 77.795 ;
     RECT  96.9 76.979 97.32 78.085 ;
     RECT  45.6 76.405 64.968 78.661 ;
     RECT  96.9 78.085 98.28 79.043 ;
     RECT  94.2 77.795 95.4 79.715 ;
     RECT  83.28 76.835 83.712 79.717 ;
     RECT  96.9 79.043 97.32 79.859 ;
     RECT  45.6 78.661 65.016 82.643 ;
     RECT  83.28 79.717 84.648 84.995 ;
     RECT  83.4 84.995 84.648 85.523 ;
     RECT  37.5 2.151 37.812 85.621 ;
     RECT  34.8 2.151 35.112 85.717 ;
     RECT  37.5 85.621 37.944 85.763 ;
     RECT  45.6 82.643 64.968 98.629 ;
     RECT  34.464 85.717 35.112 101.507 ;
     RECT  39.6 26.581 40.512 103.235 ;
     RECT  2.4 53.843 2.712 103.419 ;
     RECT  5.1 2.151 5.412 103.419 ;
     RECT  7.8 2.151 8.112 103.419 ;
     RECT  10.5 2.151 10.812 103.419 ;
     RECT  13.2 2.151 13.512 103.419 ;
     RECT  15.9 2.151 16.212 103.419 ;
     RECT  18.6 2.151 18.912 103.419 ;
     RECT  21.3 2.151 21.612 103.419 ;
     RECT  24 2.151 24.312 103.419 ;
     RECT  26.7 2.151 27.012 103.419 ;
     RECT  29.4 2.151 29.712 103.419 ;
     RECT  32.1 2.151 32.412 103.419 ;
     RECT  34.8 101.507 35.112 103.419 ;
     RECT  37.5 85.763 37.812 103.419 ;
     RECT  40.2 103.235 40.512 103.419 ;
     RECT  42.9 2.151 43.212 103.419 ;
     RECT  45.6 98.629 65.064 103.419 ;
     RECT  67.2 2.151 67.512 103.419 ;
     RECT  69.9 2.151 70.212 103.419 ;
     RECT  72.6 37.427 72.912 103.419 ;
     RECT  75.3 2.151 75.612 103.419 ;
     RECT  78 2.151 78.312 103.419 ;
     RECT  80.7 2.151 81.012 103.419 ;
     RECT  83.4 85.523 83.712 103.419 ;
     RECT  86.1 76.499 86.412 103.419 ;
     RECT  88.8 2.151 89.112 103.419 ;
     RECT  91.5 2.151 91.812 103.419 ;
     RECT  94.2 79.715 94.512 103.419 ;
     RECT  96.9 79.859 97.212 103.419 ;
     RECT  99.6 76.979 99.912 103.419 ;
     RECT  2.592 103.419 2.712 103.433 ;
     RECT  5.292 103.419 5.412 103.433 ;
     RECT  7.992 103.419 8.112 103.433 ;
     RECT  10.692 103.419 10.812 103.433 ;
     RECT  13.392 103.419 13.512 103.433 ;
     RECT  16.092 103.419 16.212 103.433 ;
     RECT  18.792 103.419 18.912 103.433 ;
     RECT  21.492 103.419 21.612 103.433 ;
     RECT  24.192 103.419 24.312 103.433 ;
     RECT  26.892 103.419 27.012 103.433 ;
     RECT  29.592 103.419 29.712 103.433 ;
     RECT  32.292 103.419 32.412 103.433 ;
     RECT  34.992 103.419 35.112 103.433 ;
     RECT  37.692 103.419 37.812 103.433 ;
     RECT  40.392 103.419 40.512 103.433 ;
     RECT  43.092 103.419 43.212 103.433 ;
     RECT  45.792 103.419 65.064 103.433 ;
     RECT  67.392 103.419 67.512 103.433 ;
     RECT  70.092 103.419 70.212 103.433 ;
     RECT  72.792 103.419 72.912 103.433 ;
     RECT  75.492 103.419 75.612 103.433 ;
     RECT  78.192 103.419 78.312 103.433 ;
     RECT  80.892 103.419 81.012 103.433 ;
     RECT  83.592 103.419 83.712 103.433 ;
     RECT  86.292 103.419 86.412 103.433 ;
     RECT  88.992 103.419 89.112 103.433 ;
     RECT  91.692 103.419 91.812 103.433 ;
     RECT  94.392 103.419 94.512 103.433 ;
     RECT  97.092 103.419 97.212 103.433 ;
     RECT  99.792 103.419 99.912 103.433 ;
     RECT  46.704 103.433 65.064 103.667 ;
     RECT  46.704 103.667 64.968 105.685 ;
     RECT  46.608 105.685 64.968 105.744 ;
  END
END qfd_rlyh0_600_EN_104x106
END LIBRARY
